###############################################################
#  Generated by:      Cadence Innovus 21.14-e032_1
#  OS:                Linux x86_64(Host ID scc767089)
#  Generated on:      Thu Mar 16 00:29:08 2023
#  Design:            scr1_pipe_top
#  Command:           write_lef_abstract scr1_pipe_top.lef -top_layer 9 -stripe_pins
###############################################################

VERSION 5.8 ;

BUSBITCHARS "[]" ;
DIVIDERCHAR "/" ;

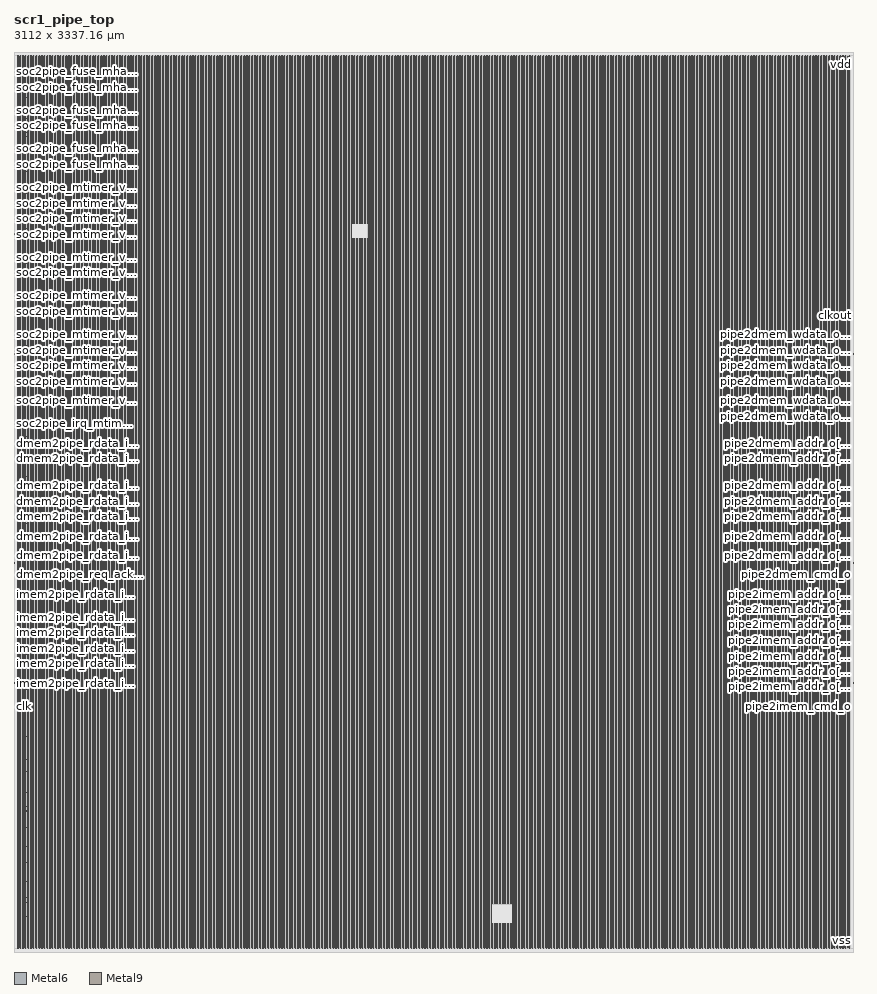
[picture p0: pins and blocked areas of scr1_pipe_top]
MACRO scr1_pipe_top
  CLASS BLOCK ;
  SIZE 3112.000000 BY 3337.160000 ;
  FOREIGN scr1_pipe_top 0.000000 0.000000 ;
  ORIGIN 0 0 ;
  SYMMETRY X Y R90 ;
  PIN pipe_rst_n
    DIRECTION INPUT ;
    USE SIGNAL ;
    PORT
      LAYER Metal6 ;
        RECT 0.000000 896.965000 0.290000 897.035000 ;
    END
  END pipe_rst_n
  PIN clk
    DIRECTION INPUT ;
    USE SIGNAL ;
    PORT
      LAYER Metal6 ;
        RECT 0.000000 911.315000 0.290000 911.385000 ;
    END
  END clk
  PIN pipe2imem_req_o
    DIRECTION OUTPUT ;
    USE SIGNAL ;
    PORT
      LAYER Metal6 ;
        RECT 3111.710000 896.965000 3112.000000 897.035000 ;
    END
  END pipe2imem_req_o
  PIN pipe2imem_cmd_o
    DIRECTION OUTPUT ;
    USE SIGNAL ;
    PORT
      LAYER Metal6 ;
        RECT 3111.710000 911.315000 3112.000000 911.385000 ;
    END
  END pipe2imem_cmd_o
  PIN pipe2imem_addr_o[31]
    DIRECTION OUTPUT ;
    USE SIGNAL ;
    PORT
      LAYER Metal6 ;
        RECT 3111.710000 925.670000 3112.000000 925.740000 ;
    END
  END pipe2imem_addr_o[31]
  PIN pipe2imem_addr_o[30]
    DIRECTION OUTPUT ;
    USE SIGNAL ;
    PORT
      LAYER Metal6 ;
        RECT 3111.710000 940.020000 3112.000000 940.090000 ;
    END
  END pipe2imem_addr_o[30]
  PIN pipe2imem_addr_o[29]
    DIRECTION OUTPUT ;
    USE SIGNAL ;
    PORT
      LAYER Metal6 ;
        RECT 3111.710000 954.375000 3112.000000 954.445000 ;
    END
  END pipe2imem_addr_o[29]
  PIN pipe2imem_addr_o[28]
    DIRECTION OUTPUT ;
    USE SIGNAL ;
    PORT
      LAYER Metal6 ;
        RECT 3111.710000 968.725000 3112.000000 968.795000 ;
    END
  END pipe2imem_addr_o[28]
  PIN pipe2imem_addr_o[27]
    DIRECTION OUTPUT ;
    USE SIGNAL ;
    PORT
      LAYER Metal6 ;
        RECT 3111.710000 983.075000 3112.000000 983.145000 ;
    END
  END pipe2imem_addr_o[27]
  PIN pipe2imem_addr_o[26]
    DIRECTION OUTPUT ;
    USE SIGNAL ;
    PORT
      LAYER Metal6 ;
        RECT 3111.710000 997.430000 3112.000000 997.500000 ;
    END
  END pipe2imem_addr_o[26]
  PIN pipe2imem_addr_o[25]
    DIRECTION OUTPUT ;
    USE SIGNAL ;
    PORT
      LAYER Metal6 ;
        RECT 3111.710000 1011.780000 3112.000000 1011.850000 ;
    END
  END pipe2imem_addr_o[25]
  PIN pipe2imem_addr_o[24]
    DIRECTION OUTPUT ;
    USE SIGNAL ;
    PORT
      LAYER Metal6 ;
        RECT 3111.710000 1026.135000 3112.000000 1026.205000 ;
    END
  END pipe2imem_addr_o[24]
  PIN pipe2imem_addr_o[23]
    DIRECTION OUTPUT ;
    USE SIGNAL ;
    PORT
      LAYER Metal6 ;
        RECT 3111.710000 1040.485000 3112.000000 1040.555000 ;
    END
  END pipe2imem_addr_o[23]
  PIN pipe2imem_addr_o[22]
    DIRECTION OUTPUT ;
    USE SIGNAL ;
    PORT
      LAYER Metal6 ;
        RECT 3111.710000 1054.835000 3112.000000 1054.905000 ;
    END
  END pipe2imem_addr_o[22]
  PIN pipe2imem_addr_o[21]
    DIRECTION OUTPUT ;
    USE SIGNAL ;
    PORT
      LAYER Metal6 ;
        RECT 3111.710000 1069.190000 3112.000000 1069.260000 ;
    END
  END pipe2imem_addr_o[21]
  PIN pipe2imem_addr_o[20]
    DIRECTION OUTPUT ;
    USE SIGNAL ;
    PORT
      LAYER Metal6 ;
        RECT 3111.710000 1083.540000 3112.000000 1083.610000 ;
    END
  END pipe2imem_addr_o[20]
  PIN pipe2imem_addr_o[19]
    DIRECTION OUTPUT ;
    USE SIGNAL ;
    PORT
      LAYER Metal6 ;
        RECT 3111.710000 1097.895000 3112.000000 1097.965000 ;
    END
  END pipe2imem_addr_o[19]
  PIN pipe2imem_addr_o[18]
    DIRECTION OUTPUT ;
    USE SIGNAL ;
    PORT
      LAYER Metal6 ;
        RECT 3111.710000 1112.245000 3112.000000 1112.315000 ;
    END
  END pipe2imem_addr_o[18]
  PIN pipe2imem_addr_o[17]
    DIRECTION OUTPUT ;
    USE SIGNAL ;
    PORT
      LAYER Metal6 ;
        RECT 3111.710000 1126.595000 3112.000000 1126.665000 ;
    END
  END pipe2imem_addr_o[17]
  PIN pipe2imem_addr_o[16]
    DIRECTION OUTPUT ;
    USE SIGNAL ;
    PORT
      LAYER Metal6 ;
        RECT 3111.710000 1140.950000 3112.000000 1141.020000 ;
    END
  END pipe2imem_addr_o[16]
  PIN pipe2imem_addr_o[15]
    DIRECTION OUTPUT ;
    USE SIGNAL ;
    PORT
      LAYER Metal6 ;
        RECT 3111.710000 1155.300000 3112.000000 1155.370000 ;
    END
  END pipe2imem_addr_o[15]
  PIN pipe2imem_addr_o[14]
    DIRECTION OUTPUT ;
    USE SIGNAL ;
    PORT
      LAYER Metal6 ;
        RECT 3111.710000 1169.655000 3112.000000 1169.725000 ;
    END
  END pipe2imem_addr_o[14]
  PIN pipe2imem_addr_o[13]
    DIRECTION OUTPUT ;
    USE SIGNAL ;
    PORT
      LAYER Metal6 ;
        RECT 3111.710000 1184.005000 3112.000000 1184.075000 ;
    END
  END pipe2imem_addr_o[13]
  PIN pipe2imem_addr_o[12]
    DIRECTION OUTPUT ;
    USE SIGNAL ;
    PORT
      LAYER Metal6 ;
        RECT 3111.710000 1198.355000 3112.000000 1198.425000 ;
    END
  END pipe2imem_addr_o[12]
  PIN pipe2imem_addr_o[11]
    DIRECTION OUTPUT ;
    USE SIGNAL ;
    PORT
      LAYER Metal6 ;
        RECT 3111.710000 1212.710000 3112.000000 1212.780000 ;
    END
  END pipe2imem_addr_o[11]
  PIN pipe2imem_addr_o[10]
    DIRECTION OUTPUT ;
    USE SIGNAL ;
    PORT
      LAYER Metal6 ;
        RECT 3111.710000 1227.060000 3112.000000 1227.130000 ;
    END
  END pipe2imem_addr_o[10]
  PIN pipe2imem_addr_o[9]
    DIRECTION OUTPUT ;
    USE SIGNAL ;
    PORT
      LAYER Metal6 ;
        RECT 3111.710000 1241.415000 3112.000000 1241.485000 ;
    END
  END pipe2imem_addr_o[9]
  PIN pipe2imem_addr_o[8]
    DIRECTION OUTPUT ;
    USE SIGNAL ;
    PORT
      LAYER Metal6 ;
        RECT 3111.710000 1255.765000 3112.000000 1255.835000 ;
    END
  END pipe2imem_addr_o[8]
  PIN pipe2imem_addr_o[7]
    DIRECTION OUTPUT ;
    USE SIGNAL ;
    PORT
      LAYER Metal6 ;
        RECT 3111.710000 1270.115000 3112.000000 1270.185000 ;
    END
  END pipe2imem_addr_o[7]
  PIN pipe2imem_addr_o[6]
    DIRECTION OUTPUT ;
    USE SIGNAL ;
    PORT
      LAYER Metal6 ;
        RECT 3111.710000 1284.470000 3112.000000 1284.540000 ;
    END
  END pipe2imem_addr_o[6]
  PIN pipe2imem_addr_o[5]
    DIRECTION OUTPUT ;
    USE SIGNAL ;
    PORT
      LAYER Metal6 ;
        RECT 3111.710000 1298.820000 3112.000000 1298.890000 ;
    END
  END pipe2imem_addr_o[5]
  PIN pipe2imem_addr_o[4]
    DIRECTION OUTPUT ;
    USE SIGNAL ;
    PORT
      LAYER Metal6 ;
        RECT 3111.710000 1313.175000 3112.000000 1313.245000 ;
    END
  END pipe2imem_addr_o[4]
  PIN pipe2imem_addr_o[3]
    DIRECTION OUTPUT ;
    USE SIGNAL ;
    PORT
      LAYER Metal6 ;
        RECT 3111.710000 1327.525000 3112.000000 1327.595000 ;
    END
  END pipe2imem_addr_o[3]
  PIN pipe2imem_addr_o[2]
    DIRECTION OUTPUT ;
    USE SIGNAL ;
    PORT
      LAYER Metal6 ;
        RECT 3111.710000 1341.875000 3112.000000 1341.945000 ;
    END
  END pipe2imem_addr_o[2]
  PIN pipe2imem_addr_o[1]
    DIRECTION OUTPUT ;
    USE SIGNAL ;
    PORT
      LAYER Metal6 ;
        RECT 3111.710000 1356.230000 3112.000000 1356.300000 ;
    END
  END pipe2imem_addr_o[1]
  PIN pipe2imem_addr_o[0]
    DIRECTION OUTPUT ;
    USE SIGNAL ;
    PORT
      LAYER Metal6 ;
        RECT 3111.710000 1370.580000 3112.000000 1370.650000 ;
    END
  END pipe2imem_addr_o[0]
  PIN imem2pipe_req_ack_i
    DIRECTION INPUT ;
    USE SIGNAL ;
    PORT
      LAYER Metal6 ;
        RECT 0.000000 925.670000 0.290000 925.740000 ;
    END
  END imem2pipe_req_ack_i
  PIN imem2pipe_rdata_i[31]
    DIRECTION INPUT ;
    USE SIGNAL ;
    PORT
      LAYER Metal6 ;
        RECT 0.000000 940.020000 0.290000 940.090000 ;
    END
  END imem2pipe_rdata_i[31]
  PIN imem2pipe_rdata_i[30]
    DIRECTION INPUT ;
    USE SIGNAL ;
    PORT
      LAYER Metal6 ;
        RECT 0.000000 954.375000 0.290000 954.445000 ;
    END
  END imem2pipe_rdata_i[30]
  PIN imem2pipe_rdata_i[29]
    DIRECTION INPUT ;
    USE SIGNAL ;
    PORT
      LAYER Metal6 ;
        RECT 0.000000 968.725000 0.290000 968.795000 ;
    END
  END imem2pipe_rdata_i[29]
  PIN imem2pipe_rdata_i[28]
    DIRECTION INPUT ;
    USE SIGNAL ;
    PORT
      LAYER Metal6 ;
        RECT 0.000000 983.075000 0.290000 983.145000 ;
    END
  END imem2pipe_rdata_i[28]
  PIN imem2pipe_rdata_i[27]
    DIRECTION INPUT ;
    USE SIGNAL ;
    PORT
      LAYER Metal6 ;
        RECT 0.000000 997.430000 0.290000 997.500000 ;
    END
  END imem2pipe_rdata_i[27]
  PIN imem2pipe_rdata_i[26]
    DIRECTION INPUT ;
    USE SIGNAL ;
    PORT
      LAYER Metal6 ;
        RECT 0.000000 1011.780000 0.290000 1011.850000 ;
    END
  END imem2pipe_rdata_i[26]
  PIN imem2pipe_rdata_i[25]
    DIRECTION INPUT ;
    USE SIGNAL ;
    PORT
      LAYER Metal6 ;
        RECT 0.000000 1026.135000 0.290000 1026.205000 ;
    END
  END imem2pipe_rdata_i[25]
  PIN imem2pipe_rdata_i[24]
    DIRECTION INPUT ;
    USE SIGNAL ;
    PORT
      LAYER Metal6 ;
        RECT 0.000000 1040.485000 0.290000 1040.555000 ;
    END
  END imem2pipe_rdata_i[24]
  PIN imem2pipe_rdata_i[23]
    DIRECTION INPUT ;
    USE SIGNAL ;
    PORT
      LAYER Metal6 ;
        RECT 0.000000 1054.835000 0.290000 1054.905000 ;
    END
  END imem2pipe_rdata_i[23]
  PIN imem2pipe_rdata_i[22]
    DIRECTION INPUT ;
    USE SIGNAL ;
    PORT
      LAYER Metal6 ;
        RECT 0.000000 1069.190000 0.290000 1069.260000 ;
    END
  END imem2pipe_rdata_i[22]
  PIN imem2pipe_rdata_i[21]
    DIRECTION INPUT ;
    USE SIGNAL ;
    PORT
      LAYER Metal6 ;
        RECT 0.000000 1083.540000 0.290000 1083.610000 ;
    END
  END imem2pipe_rdata_i[21]
  PIN imem2pipe_rdata_i[20]
    DIRECTION INPUT ;
    USE SIGNAL ;
    PORT
      LAYER Metal6 ;
        RECT 0.000000 1097.895000 0.290000 1097.965000 ;
    END
  END imem2pipe_rdata_i[20]
  PIN imem2pipe_rdata_i[19]
    DIRECTION INPUT ;
    USE SIGNAL ;
    PORT
      LAYER Metal6 ;
        RECT 0.000000 1112.245000 0.290000 1112.315000 ;
    END
  END imem2pipe_rdata_i[19]
  PIN imem2pipe_rdata_i[18]
    DIRECTION INPUT ;
    USE SIGNAL ;
    PORT
      LAYER Metal6 ;
        RECT 0.000000 1126.595000 0.290000 1126.665000 ;
    END
  END imem2pipe_rdata_i[18]
  PIN imem2pipe_rdata_i[17]
    DIRECTION INPUT ;
    USE SIGNAL ;
    PORT
      LAYER Metal6 ;
        RECT 0.000000 1140.950000 0.290000 1141.020000 ;
    END
  END imem2pipe_rdata_i[17]
  PIN imem2pipe_rdata_i[16]
    DIRECTION INPUT ;
    USE SIGNAL ;
    PORT
      LAYER Metal6 ;
        RECT 0.000000 1155.300000 0.290000 1155.370000 ;
    END
  END imem2pipe_rdata_i[16]
  PIN imem2pipe_rdata_i[15]
    DIRECTION INPUT ;
    USE SIGNAL ;
    PORT
      LAYER Metal6 ;
        RECT 0.000000 1169.655000 0.290000 1169.725000 ;
    END
  END imem2pipe_rdata_i[15]
  PIN imem2pipe_rdata_i[14]
    DIRECTION INPUT ;
    USE SIGNAL ;
    PORT
      LAYER Metal6 ;
        RECT 0.000000 1184.005000 0.290000 1184.075000 ;
    END
  END imem2pipe_rdata_i[14]
  PIN imem2pipe_rdata_i[13]
    DIRECTION INPUT ;
    USE SIGNAL ;
    PORT
      LAYER Metal6 ;
        RECT 0.000000 1198.355000 0.290000 1198.425000 ;
    END
  END imem2pipe_rdata_i[13]
  PIN imem2pipe_rdata_i[12]
    DIRECTION INPUT ;
    USE SIGNAL ;
    PORT
      LAYER Metal6 ;
        RECT 0.000000 1212.710000 0.290000 1212.780000 ;
    END
  END imem2pipe_rdata_i[12]
  PIN imem2pipe_rdata_i[11]
    DIRECTION INPUT ;
    USE SIGNAL ;
    PORT
      LAYER Metal6 ;
        RECT 0.000000 1227.060000 0.290000 1227.130000 ;
    END
  END imem2pipe_rdata_i[11]
  PIN imem2pipe_rdata_i[10]
    DIRECTION INPUT ;
    USE SIGNAL ;
    PORT
      LAYER Metal6 ;
        RECT 0.000000 1241.415000 0.290000 1241.485000 ;
    END
  END imem2pipe_rdata_i[10]
  PIN imem2pipe_rdata_i[9]
    DIRECTION INPUT ;
    USE SIGNAL ;
    PORT
      LAYER Metal6 ;
        RECT 0.000000 1255.765000 0.290000 1255.835000 ;
    END
  END imem2pipe_rdata_i[9]
  PIN imem2pipe_rdata_i[8]
    DIRECTION INPUT ;
    USE SIGNAL ;
    PORT
      LAYER Metal6 ;
        RECT 0.000000 1270.115000 0.290000 1270.185000 ;
    END
  END imem2pipe_rdata_i[8]
  PIN imem2pipe_rdata_i[7]
    DIRECTION INPUT ;
    USE SIGNAL ;
    PORT
      LAYER Metal6 ;
        RECT 0.000000 1284.470000 0.290000 1284.540000 ;
    END
  END imem2pipe_rdata_i[7]
  PIN imem2pipe_rdata_i[6]
    DIRECTION INPUT ;
    USE SIGNAL ;
    PORT
      LAYER Metal6 ;
        RECT 0.000000 1298.820000 0.290000 1298.890000 ;
    END
  END imem2pipe_rdata_i[6]
  PIN imem2pipe_rdata_i[5]
    DIRECTION INPUT ;
    USE SIGNAL ;
    PORT
      LAYER Metal6 ;
        RECT 0.000000 1313.175000 0.290000 1313.245000 ;
    END
  END imem2pipe_rdata_i[5]
  PIN imem2pipe_rdata_i[4]
    DIRECTION INPUT ;
    USE SIGNAL ;
    PORT
      LAYER Metal6 ;
        RECT 0.000000 1327.525000 0.290000 1327.595000 ;
    END
  END imem2pipe_rdata_i[4]
  PIN imem2pipe_rdata_i[3]
    DIRECTION INPUT ;
    USE SIGNAL ;
    PORT
      LAYER Metal6 ;
        RECT 0.000000 1341.875000 0.290000 1341.945000 ;
    END
  END imem2pipe_rdata_i[3]
  PIN imem2pipe_rdata_i[2]
    DIRECTION INPUT ;
    USE SIGNAL ;
    PORT
      LAYER Metal6 ;
        RECT 0.000000 1356.230000 0.290000 1356.300000 ;
    END
  END imem2pipe_rdata_i[2]
  PIN imem2pipe_rdata_i[1]
    DIRECTION INPUT ;
    USE SIGNAL ;
    PORT
      LAYER Metal6 ;
        RECT 0.000000 1370.580000 0.290000 1370.650000 ;
    END
  END imem2pipe_rdata_i[1]
  PIN imem2pipe_rdata_i[0]
    DIRECTION INPUT ;
    USE SIGNAL ;
    PORT
      LAYER Metal6 ;
        RECT 0.000000 1384.935000 0.290000 1385.005000 ;
    END
  END imem2pipe_rdata_i[0]
  PIN imem2pipe_resp_i[1]
    DIRECTION INPUT ;
    USE SIGNAL ;
    PORT
      LAYER Metal6 ;
        RECT 0.000000 1399.285000 0.290000 1399.355000 ;
    END
  END imem2pipe_resp_i[1]
  PIN imem2pipe_resp_i[0]
    DIRECTION INPUT ;
    USE SIGNAL ;
    PORT
      LAYER Metal6 ;
        RECT 0.000000 1413.635000 0.290000 1413.705000 ;
    END
  END imem2pipe_resp_i[0]
  PIN pipe2dmem_req_o
    DIRECTION OUTPUT ;
    USE SIGNAL ;
    PORT
      LAYER Metal6 ;
        RECT 3111.710000 1384.935000 3112.000000 1385.005000 ;
    END
  END pipe2dmem_req_o
  PIN pipe2dmem_cmd_o
    DIRECTION OUTPUT ;
    USE SIGNAL ;
    PORT
      LAYER Metal6 ;
        RECT 3111.710000 1399.285000 3112.000000 1399.355000 ;
    END
  END pipe2dmem_cmd_o
  PIN pipe2dmem_width_o[1]
    DIRECTION OUTPUT ;
    USE SIGNAL ;
    PORT
      LAYER Metal6 ;
        RECT 3111.710000 1413.635000 3112.000000 1413.705000 ;
    END
  END pipe2dmem_width_o[1]
  PIN pipe2dmem_width_o[0]
    DIRECTION OUTPUT ;
    USE SIGNAL ;
    PORT
      LAYER Metal6 ;
        RECT 3111.710000 1427.990000 3112.000000 1428.060000 ;
    END
  END pipe2dmem_width_o[0]
  PIN pipe2dmem_addr_o[31]
    DIRECTION OUTPUT ;
    USE SIGNAL ;
    PORT
      LAYER Metal6 ;
        RECT 3111.710000 1442.340000 3112.000000 1442.410000 ;
    END
  END pipe2dmem_addr_o[31]
  PIN pipe2dmem_addr_o[30]
    DIRECTION OUTPUT ;
    USE SIGNAL ;
    PORT
      LAYER Metal6 ;
        RECT 3111.710000 1456.695000 3112.000000 1456.765000 ;
    END
  END pipe2dmem_addr_o[30]
  PIN pipe2dmem_addr_o[29]
    DIRECTION OUTPUT ;
    USE SIGNAL ;
    PORT
      LAYER Metal6 ;
        RECT 3111.710000 1471.045000 3112.000000 1471.115000 ;
    END
  END pipe2dmem_addr_o[29]
  PIN pipe2dmem_addr_o[28]
    DIRECTION OUTPUT ;
    USE SIGNAL ;
    PORT
      LAYER Metal6 ;
        RECT 3111.710000 1485.395000 3112.000000 1485.465000 ;
    END
  END pipe2dmem_addr_o[28]
  PIN pipe2dmem_addr_o[27]
    DIRECTION OUTPUT ;
    USE SIGNAL ;
    PORT
      LAYER Metal6 ;
        RECT 3111.710000 1499.750000 3112.000000 1499.820000 ;
    END
  END pipe2dmem_addr_o[27]
  PIN pipe2dmem_addr_o[26]
    DIRECTION OUTPUT ;
    USE SIGNAL ;
    PORT
      LAYER Metal6 ;
        RECT 3111.710000 1514.100000 3112.000000 1514.170000 ;
    END
  END pipe2dmem_addr_o[26]
  PIN pipe2dmem_addr_o[25]
    DIRECTION OUTPUT ;
    USE SIGNAL ;
    PORT
      LAYER Metal6 ;
        RECT 3111.710000 1528.455000 3112.000000 1528.525000 ;
    END
  END pipe2dmem_addr_o[25]
  PIN pipe2dmem_addr_o[24]
    DIRECTION OUTPUT ;
    USE SIGNAL ;
    PORT
      LAYER Metal6 ;
        RECT 3111.710000 1542.805000 3112.000000 1542.875000 ;
    END
  END pipe2dmem_addr_o[24]
  PIN pipe2dmem_addr_o[23]
    DIRECTION OUTPUT ;
    USE SIGNAL ;
    PORT
      LAYER Metal6 ;
        RECT 3111.710000 1557.155000 3112.000000 1557.225000 ;
    END
  END pipe2dmem_addr_o[23]
  PIN pipe2dmem_addr_o[22]
    DIRECTION OUTPUT ;
    USE SIGNAL ;
    PORT
      LAYER Metal6 ;
        RECT 3111.710000 1571.510000 3112.000000 1571.580000 ;
    END
  END pipe2dmem_addr_o[22]
  PIN pipe2dmem_addr_o[21]
    DIRECTION OUTPUT ;
    USE SIGNAL ;
    PORT
      LAYER Metal6 ;
        RECT 3111.710000 1585.860000 3112.000000 1585.930000 ;
    END
  END pipe2dmem_addr_o[21]
  PIN pipe2dmem_addr_o[20]
    DIRECTION OUTPUT ;
    USE SIGNAL ;
    PORT
      LAYER Metal6 ;
        RECT 3111.710000 1600.215000 3112.000000 1600.285000 ;
    END
  END pipe2dmem_addr_o[20]
  PIN pipe2dmem_addr_o[19]
    DIRECTION OUTPUT ;
    USE SIGNAL ;
    PORT
      LAYER Metal6 ;
        RECT 3111.710000 1614.565000 3112.000000 1614.635000 ;
    END
  END pipe2dmem_addr_o[19]
  PIN pipe2dmem_addr_o[18]
    DIRECTION OUTPUT ;
    USE SIGNAL ;
    PORT
      LAYER Metal6 ;
        RECT 3111.710000 1628.915000 3112.000000 1628.985000 ;
    END
  END pipe2dmem_addr_o[18]
  PIN pipe2dmem_addr_o[17]
    DIRECTION OUTPUT ;
    USE SIGNAL ;
    PORT
      LAYER Metal6 ;
        RECT 3111.710000 1643.270000 3112.000000 1643.340000 ;
    END
  END pipe2dmem_addr_o[17]
  PIN pipe2dmem_addr_o[16]
    DIRECTION OUTPUT ;
    USE SIGNAL ;
    PORT
      LAYER Metal6 ;
        RECT 3111.710000 1657.620000 3112.000000 1657.690000 ;
    END
  END pipe2dmem_addr_o[16]
  PIN pipe2dmem_addr_o[15]
    DIRECTION OUTPUT ;
    USE SIGNAL ;
    PORT
      LAYER Metal6 ;
        RECT 3111.710000 1671.975000 3112.000000 1672.045000 ;
    END
  END pipe2dmem_addr_o[15]
  PIN pipe2dmem_addr_o[14]
    DIRECTION OUTPUT ;
    USE SIGNAL ;
    PORT
      LAYER Metal6 ;
        RECT 3111.710000 1686.325000 3112.000000 1686.395000 ;
    END
  END pipe2dmem_addr_o[14]
  PIN pipe2dmem_addr_o[13]
    DIRECTION OUTPUT ;
    USE SIGNAL ;
    PORT
      LAYER Metal6 ;
        RECT 3111.710000 1700.675000 3112.000000 1700.745000 ;
    END
  END pipe2dmem_addr_o[13]
  PIN pipe2dmem_addr_o[12]
    DIRECTION OUTPUT ;
    USE SIGNAL ;
    PORT
      LAYER Metal6 ;
        RECT 3111.710000 1715.030000 3112.000000 1715.100000 ;
    END
  END pipe2dmem_addr_o[12]
  PIN pipe2dmem_addr_o[11]
    DIRECTION OUTPUT ;
    USE SIGNAL ;
    PORT
      LAYER Metal6 ;
        RECT 3111.710000 1729.380000 3112.000000 1729.450000 ;
    END
  END pipe2dmem_addr_o[11]
  PIN pipe2dmem_addr_o[10]
    DIRECTION OUTPUT ;
    USE SIGNAL ;
    PORT
      LAYER Metal6 ;
        RECT 3111.710000 1743.735000 3112.000000 1743.805000 ;
    END
  END pipe2dmem_addr_o[10]
  PIN pipe2dmem_addr_o[9]
    DIRECTION OUTPUT ;
    USE SIGNAL ;
    PORT
      LAYER Metal6 ;
        RECT 3111.710000 1758.085000 3112.000000 1758.155000 ;
    END
  END pipe2dmem_addr_o[9]
  PIN pipe2dmem_addr_o[8]
    DIRECTION OUTPUT ;
    USE SIGNAL ;
    PORT
      LAYER Metal6 ;
        RECT 3111.710000 1772.435000 3112.000000 1772.505000 ;
    END
  END pipe2dmem_addr_o[8]
  PIN pipe2dmem_addr_o[7]
    DIRECTION OUTPUT ;
    USE SIGNAL ;
    PORT
      LAYER Metal6 ;
        RECT 3111.710000 1786.790000 3112.000000 1786.860000 ;
    END
  END pipe2dmem_addr_o[7]
  PIN pipe2dmem_addr_o[6]
    DIRECTION OUTPUT ;
    USE SIGNAL ;
    PORT
      LAYER Metal6 ;
        RECT 3111.710000 1801.140000 3112.000000 1801.210000 ;
    END
  END pipe2dmem_addr_o[6]
  PIN pipe2dmem_addr_o[5]
    DIRECTION OUTPUT ;
    USE SIGNAL ;
    PORT
      LAYER Metal6 ;
        RECT 3111.710000 1815.495000 3112.000000 1815.565000 ;
    END
  END pipe2dmem_addr_o[5]
  PIN pipe2dmem_addr_o[4]
    DIRECTION OUTPUT ;
    USE SIGNAL ;
    PORT
      LAYER Metal6 ;
        RECT 3111.710000 1829.845000 3112.000000 1829.915000 ;
    END
  END pipe2dmem_addr_o[4]
  PIN pipe2dmem_addr_o[3]
    DIRECTION OUTPUT ;
    USE SIGNAL ;
    PORT
      LAYER Metal6 ;
        RECT 3111.710000 1844.195000 3112.000000 1844.265000 ;
    END
  END pipe2dmem_addr_o[3]
  PIN pipe2dmem_addr_o[2]
    DIRECTION OUTPUT ;
    USE SIGNAL ;
    PORT
      LAYER Metal6 ;
        RECT 3111.710000 1858.550000 3112.000000 1858.620000 ;
    END
  END pipe2dmem_addr_o[2]
  PIN pipe2dmem_addr_o[1]
    DIRECTION OUTPUT ;
    USE SIGNAL ;
    PORT
      LAYER Metal6 ;
        RECT 3111.710000 1872.900000 3112.000000 1872.970000 ;
    END
  END pipe2dmem_addr_o[1]
  PIN pipe2dmem_addr_o[0]
    DIRECTION OUTPUT ;
    USE SIGNAL ;
    PORT
      LAYER Metal6 ;
        RECT 3111.710000 1887.255000 3112.000000 1887.325000 ;
    END
  END pipe2dmem_addr_o[0]
  PIN pipe2dmem_wdata_o[31]
    DIRECTION OUTPUT ;
    USE SIGNAL ;
    PORT
      LAYER Metal6 ;
        RECT 3111.710000 1901.605000 3112.000000 1901.675000 ;
    END
  END pipe2dmem_wdata_o[31]
  PIN pipe2dmem_wdata_o[30]
    DIRECTION OUTPUT ;
    USE SIGNAL ;
    PORT
      LAYER Metal6 ;
        RECT 3111.710000 1915.955000 3112.000000 1916.025000 ;
    END
  END pipe2dmem_wdata_o[30]
  PIN pipe2dmem_wdata_o[29]
    DIRECTION OUTPUT ;
    USE SIGNAL ;
    PORT
      LAYER Metal6 ;
        RECT 3111.710000 1930.310000 3112.000000 1930.380000 ;
    END
  END pipe2dmem_wdata_o[29]
  PIN pipe2dmem_wdata_o[28]
    DIRECTION OUTPUT ;
    USE SIGNAL ;
    PORT
      LAYER Metal6 ;
        RECT 3111.710000 1944.660000 3112.000000 1944.730000 ;
    END
  END pipe2dmem_wdata_o[28]
  PIN pipe2dmem_wdata_o[27]
    DIRECTION OUTPUT ;
    USE SIGNAL ;
    PORT
      LAYER Metal6 ;
        RECT 3111.710000 1959.015000 3112.000000 1959.085000 ;
    END
  END pipe2dmem_wdata_o[27]
  PIN pipe2dmem_wdata_o[26]
    DIRECTION OUTPUT ;
    USE SIGNAL ;
    PORT
      LAYER Metal6 ;
        RECT 3111.710000 1973.365000 3112.000000 1973.435000 ;
    END
  END pipe2dmem_wdata_o[26]
  PIN pipe2dmem_wdata_o[25]
    DIRECTION OUTPUT ;
    USE SIGNAL ;
    PORT
      LAYER Metal6 ;
        RECT 3111.710000 1987.715000 3112.000000 1987.785000 ;
    END
  END pipe2dmem_wdata_o[25]
  PIN pipe2dmem_wdata_o[24]
    DIRECTION OUTPUT ;
    USE SIGNAL ;
    PORT
      LAYER Metal6 ;
        RECT 3111.710000 2002.070000 3112.000000 2002.140000 ;
    END
  END pipe2dmem_wdata_o[24]
  PIN pipe2dmem_wdata_o[23]
    DIRECTION OUTPUT ;
    USE SIGNAL ;
    PORT
      LAYER Metal6 ;
        RECT 3111.710000 2016.420000 3112.000000 2016.490000 ;
    END
  END pipe2dmem_wdata_o[23]
  PIN pipe2dmem_wdata_o[22]
    DIRECTION OUTPUT ;
    USE SIGNAL ;
    PORT
      LAYER Metal6 ;
        RECT 3111.710000 2030.775000 3112.000000 2030.845000 ;
    END
  END pipe2dmem_wdata_o[22]
  PIN pipe2dmem_wdata_o[21]
    DIRECTION OUTPUT ;
    USE SIGNAL ;
    PORT
      LAYER Metal6 ;
        RECT 3111.710000 2045.125000 3112.000000 2045.195000 ;
    END
  END pipe2dmem_wdata_o[21]
  PIN pipe2dmem_wdata_o[20]
    DIRECTION OUTPUT ;
    USE SIGNAL ;
    PORT
      LAYER Metal6 ;
        RECT 3111.710000 2059.475000 3112.000000 2059.545000 ;
    END
  END pipe2dmem_wdata_o[20]
  PIN pipe2dmem_wdata_o[19]
    DIRECTION OUTPUT ;
    USE SIGNAL ;
    PORT
      LAYER Metal6 ;
        RECT 3111.710000 2073.830000 3112.000000 2073.900000 ;
    END
  END pipe2dmem_wdata_o[19]
  PIN pipe2dmem_wdata_o[18]
    DIRECTION OUTPUT ;
    USE SIGNAL ;
    PORT
      LAYER Metal6 ;
        RECT 3111.710000 2088.180000 3112.000000 2088.250000 ;
    END
  END pipe2dmem_wdata_o[18]
  PIN pipe2dmem_wdata_o[17]
    DIRECTION OUTPUT ;
    USE SIGNAL ;
    PORT
      LAYER Metal6 ;
        RECT 3111.710000 2102.535000 3112.000000 2102.605000 ;
    END
  END pipe2dmem_wdata_o[17]
  PIN pipe2dmem_wdata_o[16]
    DIRECTION OUTPUT ;
    USE SIGNAL ;
    PORT
      LAYER Metal6 ;
        RECT 3111.710000 2116.885000 3112.000000 2116.955000 ;
    END
  END pipe2dmem_wdata_o[16]
  PIN pipe2dmem_wdata_o[15]
    DIRECTION OUTPUT ;
    USE SIGNAL ;
    PORT
      LAYER Metal6 ;
        RECT 3111.710000 2131.235000 3112.000000 2131.305000 ;
    END
  END pipe2dmem_wdata_o[15]
  PIN pipe2dmem_wdata_o[14]
    DIRECTION OUTPUT ;
    USE SIGNAL ;
    PORT
      LAYER Metal6 ;
        RECT 3111.710000 2145.590000 3112.000000 2145.660000 ;
    END
  END pipe2dmem_wdata_o[14]
  PIN pipe2dmem_wdata_o[13]
    DIRECTION OUTPUT ;
    USE SIGNAL ;
    PORT
      LAYER Metal6 ;
        RECT 3111.710000 2159.940000 3112.000000 2160.010000 ;
    END
  END pipe2dmem_wdata_o[13]
  PIN pipe2dmem_wdata_o[12]
    DIRECTION OUTPUT ;
    USE SIGNAL ;
    PORT
      LAYER Metal6 ;
        RECT 3111.710000 2174.295000 3112.000000 2174.365000 ;
    END
  END pipe2dmem_wdata_o[12]
  PIN pipe2dmem_wdata_o[11]
    DIRECTION OUTPUT ;
    USE SIGNAL ;
    PORT
      LAYER Metal6 ;
        RECT 3111.710000 2188.645000 3112.000000 2188.715000 ;
    END
  END pipe2dmem_wdata_o[11]
  PIN pipe2dmem_wdata_o[10]
    DIRECTION OUTPUT ;
    USE SIGNAL ;
    PORT
      LAYER Metal6 ;
        RECT 3111.710000 2202.995000 3112.000000 2203.065000 ;
    END
  END pipe2dmem_wdata_o[10]
  PIN pipe2dmem_wdata_o[9]
    DIRECTION OUTPUT ;
    USE SIGNAL ;
    PORT
      LAYER Metal6 ;
        RECT 3111.710000 2217.350000 3112.000000 2217.420000 ;
    END
  END pipe2dmem_wdata_o[9]
  PIN pipe2dmem_wdata_o[8]
    DIRECTION OUTPUT ;
    USE SIGNAL ;
    PORT
      LAYER Metal6 ;
        RECT 3111.710000 2231.700000 3112.000000 2231.770000 ;
    END
  END pipe2dmem_wdata_o[8]
  PIN pipe2dmem_wdata_o[7]
    DIRECTION OUTPUT ;
    USE SIGNAL ;
    PORT
      LAYER Metal6 ;
        RECT 3111.710000 2246.055000 3112.000000 2246.125000 ;
    END
  END pipe2dmem_wdata_o[7]
  PIN pipe2dmem_wdata_o[6]
    DIRECTION OUTPUT ;
    USE SIGNAL ;
    PORT
      LAYER Metal6 ;
        RECT 3111.710000 2260.405000 3112.000000 2260.475000 ;
    END
  END pipe2dmem_wdata_o[6]
  PIN pipe2dmem_wdata_o[5]
    DIRECTION OUTPUT ;
    USE SIGNAL ;
    PORT
      LAYER Metal6 ;
        RECT 3111.710000 2274.755000 3112.000000 2274.825000 ;
    END
  END pipe2dmem_wdata_o[5]
  PIN pipe2dmem_wdata_o[4]
    DIRECTION OUTPUT ;
    USE SIGNAL ;
    PORT
      LAYER Metal6 ;
        RECT 3111.710000 2289.110000 3112.000000 2289.180000 ;
    END
  END pipe2dmem_wdata_o[4]
  PIN pipe2dmem_wdata_o[3]
    DIRECTION OUTPUT ;
    USE SIGNAL ;
    PORT
      LAYER Metal6 ;
        RECT 3111.710000 2303.460000 3112.000000 2303.530000 ;
    END
  END pipe2dmem_wdata_o[3]
  PIN pipe2dmem_wdata_o[2]
    DIRECTION OUTPUT ;
    USE SIGNAL ;
    PORT
      LAYER Metal6 ;
        RECT 3111.710000 2317.815000 3112.000000 2317.885000 ;
    END
  END pipe2dmem_wdata_o[2]
  PIN pipe2dmem_wdata_o[1]
    DIRECTION OUTPUT ;
    USE SIGNAL ;
    PORT
      LAYER Metal6 ;
        RECT 3111.710000 2332.165000 3112.000000 2332.235000 ;
    END
  END pipe2dmem_wdata_o[1]
  PIN pipe2dmem_wdata_o[0]
    DIRECTION OUTPUT ;
    USE SIGNAL ;
    PORT
      LAYER Metal6 ;
        RECT 3111.710000 2346.515000 3112.000000 2346.585000 ;
    END
  END pipe2dmem_wdata_o[0]
  PIN dmem2pipe_req_ack_i
    DIRECTION INPUT ;
    USE SIGNAL ;
    PORT
      LAYER Metal6 ;
        RECT 0.000000 1427.990000 0.290000 1428.060000 ;
    END
  END dmem2pipe_req_ack_i
  PIN dmem2pipe_rdata_i[31]
    DIRECTION INPUT ;
    USE SIGNAL ;
    PORT
      LAYER Metal6 ;
        RECT 0.000000 1442.340000 0.290000 1442.410000 ;
    END
  END dmem2pipe_rdata_i[31]
  PIN dmem2pipe_rdata_i[30]
    DIRECTION INPUT ;
    USE SIGNAL ;
    PORT
      LAYER Metal6 ;
        RECT 0.000000 1456.695000 0.290000 1456.765000 ;
    END
  END dmem2pipe_rdata_i[30]
  PIN dmem2pipe_rdata_i[29]
    DIRECTION INPUT ;
    USE SIGNAL ;
    PORT
      LAYER Metal6 ;
        RECT 0.000000 1471.045000 0.290000 1471.115000 ;
    END
  END dmem2pipe_rdata_i[29]
  PIN dmem2pipe_rdata_i[28]
    DIRECTION INPUT ;
    USE SIGNAL ;
    PORT
      LAYER Metal6 ;
        RECT 0.000000 1485.395000 0.290000 1485.465000 ;
    END
  END dmem2pipe_rdata_i[28]
  PIN dmem2pipe_rdata_i[27]
    DIRECTION INPUT ;
    USE SIGNAL ;
    PORT
      LAYER Metal6 ;
        RECT 0.000000 1499.750000 0.290000 1499.820000 ;
    END
  END dmem2pipe_rdata_i[27]
  PIN dmem2pipe_rdata_i[26]
    DIRECTION INPUT ;
    USE SIGNAL ;
    PORT
      LAYER Metal6 ;
        RECT 0.000000 1514.100000 0.290000 1514.170000 ;
    END
  END dmem2pipe_rdata_i[26]
  PIN dmem2pipe_rdata_i[25]
    DIRECTION INPUT ;
    USE SIGNAL ;
    PORT
      LAYER Metal6 ;
        RECT 0.000000 1528.455000 0.290000 1528.525000 ;
    END
  END dmem2pipe_rdata_i[25]
  PIN dmem2pipe_rdata_i[24]
    DIRECTION INPUT ;
    USE SIGNAL ;
    PORT
      LAYER Metal6 ;
        RECT 0.000000 1542.805000 0.290000 1542.875000 ;
    END
  END dmem2pipe_rdata_i[24]
  PIN dmem2pipe_rdata_i[23]
    DIRECTION INPUT ;
    USE SIGNAL ;
    PORT
      LAYER Metal6 ;
        RECT 0.000000 1557.155000 0.290000 1557.225000 ;
    END
  END dmem2pipe_rdata_i[23]
  PIN dmem2pipe_rdata_i[22]
    DIRECTION INPUT ;
    USE SIGNAL ;
    PORT
      LAYER Metal6 ;
        RECT 0.000000 1571.510000 0.290000 1571.580000 ;
    END
  END dmem2pipe_rdata_i[22]
  PIN dmem2pipe_rdata_i[21]
    DIRECTION INPUT ;
    USE SIGNAL ;
    PORT
      LAYER Metal6 ;
        RECT 0.000000 1585.860000 0.290000 1585.930000 ;
    END
  END dmem2pipe_rdata_i[21]
  PIN dmem2pipe_rdata_i[20]
    DIRECTION INPUT ;
    USE SIGNAL ;
    PORT
      LAYER Metal6 ;
        RECT 0.000000 1600.215000 0.290000 1600.285000 ;
    END
  END dmem2pipe_rdata_i[20]
  PIN dmem2pipe_rdata_i[19]
    DIRECTION INPUT ;
    USE SIGNAL ;
    PORT
      LAYER Metal6 ;
        RECT 0.000000 1614.565000 0.290000 1614.635000 ;
    END
  END dmem2pipe_rdata_i[19]
  PIN dmem2pipe_rdata_i[18]
    DIRECTION INPUT ;
    USE SIGNAL ;
    PORT
      LAYER Metal6 ;
        RECT 0.000000 1628.915000 0.290000 1628.985000 ;
    END
  END dmem2pipe_rdata_i[18]
  PIN dmem2pipe_rdata_i[17]
    DIRECTION INPUT ;
    USE SIGNAL ;
    PORT
      LAYER Metal6 ;
        RECT 0.000000 1643.270000 0.290000 1643.340000 ;
    END
  END dmem2pipe_rdata_i[17]
  PIN dmem2pipe_rdata_i[16]
    DIRECTION INPUT ;
    USE SIGNAL ;
    PORT
      LAYER Metal6 ;
        RECT 0.000000 1657.620000 0.290000 1657.690000 ;
    END
  END dmem2pipe_rdata_i[16]
  PIN dmem2pipe_rdata_i[15]
    DIRECTION INPUT ;
    USE SIGNAL ;
    PORT
      LAYER Metal6 ;
        RECT 0.000000 1671.975000 0.290000 1672.045000 ;
    END
  END dmem2pipe_rdata_i[15]
  PIN dmem2pipe_rdata_i[14]
    DIRECTION INPUT ;
    USE SIGNAL ;
    PORT
      LAYER Metal6 ;
        RECT 0.000000 1686.325000 0.290000 1686.395000 ;
    END
  END dmem2pipe_rdata_i[14]
  PIN dmem2pipe_rdata_i[13]
    DIRECTION INPUT ;
    USE SIGNAL ;
    PORT
      LAYER Metal6 ;
        RECT 0.000000 1700.675000 0.290000 1700.745000 ;
    END
  END dmem2pipe_rdata_i[13]
  PIN dmem2pipe_rdata_i[12]
    DIRECTION INPUT ;
    USE SIGNAL ;
    PORT
      LAYER Metal6 ;
        RECT 0.000000 1715.030000 0.290000 1715.100000 ;
    END
  END dmem2pipe_rdata_i[12]
  PIN dmem2pipe_rdata_i[11]
    DIRECTION INPUT ;
    USE SIGNAL ;
    PORT
      LAYER Metal6 ;
        RECT 0.000000 1729.380000 0.290000 1729.450000 ;
    END
  END dmem2pipe_rdata_i[11]
  PIN dmem2pipe_rdata_i[10]
    DIRECTION INPUT ;
    USE SIGNAL ;
    PORT
      LAYER Metal6 ;
        RECT 0.000000 1743.735000 0.290000 1743.805000 ;
    END
  END dmem2pipe_rdata_i[10]
  PIN dmem2pipe_rdata_i[9]
    DIRECTION INPUT ;
    USE SIGNAL ;
    PORT
      LAYER Metal6 ;
        RECT 0.000000 1758.085000 0.290000 1758.155000 ;
    END
  END dmem2pipe_rdata_i[9]
  PIN dmem2pipe_rdata_i[8]
    DIRECTION INPUT ;
    USE SIGNAL ;
    PORT
      LAYER Metal6 ;
        RECT 0.000000 1772.435000 0.290000 1772.505000 ;
    END
  END dmem2pipe_rdata_i[8]
  PIN dmem2pipe_rdata_i[7]
    DIRECTION INPUT ;
    USE SIGNAL ;
    PORT
      LAYER Metal6 ;
        RECT 0.000000 1786.790000 0.290000 1786.860000 ;
    END
  END dmem2pipe_rdata_i[7]
  PIN dmem2pipe_rdata_i[6]
    DIRECTION INPUT ;
    USE SIGNAL ;
    PORT
      LAYER Metal6 ;
        RECT 0.000000 1801.140000 0.290000 1801.210000 ;
    END
  END dmem2pipe_rdata_i[6]
  PIN dmem2pipe_rdata_i[5]
    DIRECTION INPUT ;
    USE SIGNAL ;
    PORT
      LAYER Metal6 ;
        RECT 0.000000 1815.495000 0.290000 1815.565000 ;
    END
  END dmem2pipe_rdata_i[5]
  PIN dmem2pipe_rdata_i[4]
    DIRECTION INPUT ;
    USE SIGNAL ;
    PORT
      LAYER Metal6 ;
        RECT 0.000000 1829.845000 0.290000 1829.915000 ;
    END
  END dmem2pipe_rdata_i[4]
  PIN dmem2pipe_rdata_i[3]
    DIRECTION INPUT ;
    USE SIGNAL ;
    PORT
      LAYER Metal6 ;
        RECT 0.000000 1844.195000 0.290000 1844.265000 ;
    END
  END dmem2pipe_rdata_i[3]
  PIN dmem2pipe_rdata_i[2]
    DIRECTION INPUT ;
    USE SIGNAL ;
    PORT
      LAYER Metal6 ;
        RECT 0.000000 1858.550000 0.290000 1858.620000 ;
    END
  END dmem2pipe_rdata_i[2]
  PIN dmem2pipe_rdata_i[1]
    DIRECTION INPUT ;
    USE SIGNAL ;
    PORT
      LAYER Metal6 ;
        RECT 0.000000 1872.900000 0.290000 1872.970000 ;
    END
  END dmem2pipe_rdata_i[1]
  PIN dmem2pipe_rdata_i[0]
    DIRECTION INPUT ;
    USE SIGNAL ;
    PORT
      LAYER Metal6 ;
        RECT 0.000000 1887.255000 0.290000 1887.325000 ;
    END
  END dmem2pipe_rdata_i[0]
  PIN dmem2pipe_resp_i[1]
    DIRECTION INPUT ;
    USE SIGNAL ;
    PORT
      LAYER Metal6 ;
        RECT 0.000000 1901.605000 0.290000 1901.675000 ;
    END
  END dmem2pipe_resp_i[1]
  PIN dmem2pipe_resp_i[0]
    DIRECTION INPUT ;
    USE SIGNAL ;
    PORT
      LAYER Metal6 ;
        RECT 0.000000 1915.955000 0.290000 1916.025000 ;
    END
  END dmem2pipe_resp_i[0]
  PIN soc2pipe_irq_ext_i
    DIRECTION INPUT ;
    USE SIGNAL ;
    PORT
      LAYER Metal6 ;
        RECT 0.000000 1930.310000 0.290000 1930.380000 ;
    END
  END soc2pipe_irq_ext_i
  PIN soc2pipe_irq_soft_i
    DIRECTION INPUT ;
    USE SIGNAL ;
    PORT
      LAYER Metal6 ;
        RECT 0.000000 1944.660000 0.290000 1944.730000 ;
    END
  END soc2pipe_irq_soft_i
  PIN soc2pipe_irq_mtimer_i
    DIRECTION INPUT ;
    USE SIGNAL ;
    PORT
      LAYER Metal6 ;
        RECT 0.000000 1959.015000 0.290000 1959.085000 ;
    END
  END soc2pipe_irq_mtimer_i
  PIN soc2pipe_mtimer_val_i[63]
    DIRECTION INPUT ;
    USE SIGNAL ;
    PORT
      LAYER Metal6 ;
        RECT 0.000000 1973.365000 0.290000 1973.435000 ;
    END
  END soc2pipe_mtimer_val_i[63]
  PIN soc2pipe_mtimer_val_i[62]
    DIRECTION INPUT ;
    USE SIGNAL ;
    PORT
      LAYER Metal6 ;
        RECT 0.000000 1987.715000 0.290000 1987.785000 ;
    END
  END soc2pipe_mtimer_val_i[62]
  PIN soc2pipe_mtimer_val_i[61]
    DIRECTION INPUT ;
    USE SIGNAL ;
    PORT
      LAYER Metal6 ;
        RECT 0.000000 2002.070000 0.290000 2002.140000 ;
    END
  END soc2pipe_mtimer_val_i[61]
  PIN soc2pipe_mtimer_val_i[60]
    DIRECTION INPUT ;
    USE SIGNAL ;
    PORT
      LAYER Metal6 ;
        RECT 0.000000 2016.420000 0.290000 2016.490000 ;
    END
  END soc2pipe_mtimer_val_i[60]
  PIN soc2pipe_mtimer_val_i[59]
    DIRECTION INPUT ;
    USE SIGNAL ;
    PORT
      LAYER Metal6 ;
        RECT 0.000000 2030.775000 0.290000 2030.845000 ;
    END
  END soc2pipe_mtimer_val_i[59]
  PIN soc2pipe_mtimer_val_i[58]
    DIRECTION INPUT ;
    USE SIGNAL ;
    PORT
      LAYER Metal6 ;
        RECT 0.000000 2045.125000 0.290000 2045.195000 ;
    END
  END soc2pipe_mtimer_val_i[58]
  PIN soc2pipe_mtimer_val_i[57]
    DIRECTION INPUT ;
    USE SIGNAL ;
    PORT
      LAYER Metal6 ;
        RECT 0.000000 2059.475000 0.290000 2059.545000 ;
    END
  END soc2pipe_mtimer_val_i[57]
  PIN soc2pipe_mtimer_val_i[56]
    DIRECTION INPUT ;
    USE SIGNAL ;
    PORT
      LAYER Metal6 ;
        RECT 0.000000 2073.830000 0.290000 2073.900000 ;
    END
  END soc2pipe_mtimer_val_i[56]
  PIN soc2pipe_mtimer_val_i[55]
    DIRECTION INPUT ;
    USE SIGNAL ;
    PORT
      LAYER Metal6 ;
        RECT 0.000000 2088.180000 0.290000 2088.250000 ;
    END
  END soc2pipe_mtimer_val_i[55]
  PIN soc2pipe_mtimer_val_i[54]
    DIRECTION INPUT ;
    USE SIGNAL ;
    PORT
      LAYER Metal6 ;
        RECT 0.000000 2102.535000 0.290000 2102.605000 ;
    END
  END soc2pipe_mtimer_val_i[54]
  PIN soc2pipe_mtimer_val_i[53]
    DIRECTION INPUT ;
    USE SIGNAL ;
    PORT
      LAYER Metal6 ;
        RECT 0.000000 2116.885000 0.290000 2116.955000 ;
    END
  END soc2pipe_mtimer_val_i[53]
  PIN soc2pipe_mtimer_val_i[52]
    DIRECTION INPUT ;
    USE SIGNAL ;
    PORT
      LAYER Metal6 ;
        RECT 0.000000 2131.235000 0.290000 2131.305000 ;
    END
  END soc2pipe_mtimer_val_i[52]
  PIN soc2pipe_mtimer_val_i[51]
    DIRECTION INPUT ;
    USE SIGNAL ;
    PORT
      LAYER Metal6 ;
        RECT 0.000000 2145.590000 0.290000 2145.660000 ;
    END
  END soc2pipe_mtimer_val_i[51]
  PIN soc2pipe_mtimer_val_i[50]
    DIRECTION INPUT ;
    USE SIGNAL ;
    PORT
      LAYER Metal6 ;
        RECT 0.000000 2159.940000 0.290000 2160.010000 ;
    END
  END soc2pipe_mtimer_val_i[50]
  PIN soc2pipe_mtimer_val_i[49]
    DIRECTION INPUT ;
    USE SIGNAL ;
    PORT
      LAYER Metal6 ;
        RECT 0.000000 2174.295000 0.290000 2174.365000 ;
    END
  END soc2pipe_mtimer_val_i[49]
  PIN soc2pipe_mtimer_val_i[48]
    DIRECTION INPUT ;
    USE SIGNAL ;
    PORT
      LAYER Metal6 ;
        RECT 0.000000 2188.645000 0.290000 2188.715000 ;
    END
  END soc2pipe_mtimer_val_i[48]
  PIN soc2pipe_mtimer_val_i[47]
    DIRECTION INPUT ;
    USE SIGNAL ;
    PORT
      LAYER Metal6 ;
        RECT 0.000000 2202.995000 0.290000 2203.065000 ;
    END
  END soc2pipe_mtimer_val_i[47]
  PIN soc2pipe_mtimer_val_i[46]
    DIRECTION INPUT ;
    USE SIGNAL ;
    PORT
      LAYER Metal6 ;
        RECT 0.000000 2217.350000 0.290000 2217.420000 ;
    END
  END soc2pipe_mtimer_val_i[46]
  PIN soc2pipe_mtimer_val_i[45]
    DIRECTION INPUT ;
    USE SIGNAL ;
    PORT
      LAYER Metal6 ;
        RECT 0.000000 2231.700000 0.290000 2231.770000 ;
    END
  END soc2pipe_mtimer_val_i[45]
  PIN soc2pipe_mtimer_val_i[44]
    DIRECTION INPUT ;
    USE SIGNAL ;
    PORT
      LAYER Metal6 ;
        RECT 0.000000 2246.055000 0.290000 2246.125000 ;
    END
  END soc2pipe_mtimer_val_i[44]
  PIN soc2pipe_mtimer_val_i[43]
    DIRECTION INPUT ;
    USE SIGNAL ;
    PORT
      LAYER Metal6 ;
        RECT 0.000000 2260.405000 0.290000 2260.475000 ;
    END
  END soc2pipe_mtimer_val_i[43]
  PIN soc2pipe_mtimer_val_i[42]
    DIRECTION INPUT ;
    USE SIGNAL ;
    PORT
      LAYER Metal6 ;
        RECT 0.000000 2274.755000 0.290000 2274.825000 ;
    END
  END soc2pipe_mtimer_val_i[42]
  PIN soc2pipe_mtimer_val_i[41]
    DIRECTION INPUT ;
    USE SIGNAL ;
    PORT
      LAYER Metal6 ;
        RECT 0.000000 2289.110000 0.290000 2289.180000 ;
    END
  END soc2pipe_mtimer_val_i[41]
  PIN soc2pipe_mtimer_val_i[40]
    DIRECTION INPUT ;
    USE SIGNAL ;
    PORT
      LAYER Metal6 ;
        RECT 0.000000 2303.460000 0.290000 2303.530000 ;
    END
  END soc2pipe_mtimer_val_i[40]
  PIN soc2pipe_mtimer_val_i[39]
    DIRECTION INPUT ;
    USE SIGNAL ;
    PORT
      LAYER Metal6 ;
        RECT 0.000000 2317.815000 0.290000 2317.885000 ;
    END
  END soc2pipe_mtimer_val_i[39]
  PIN soc2pipe_mtimer_val_i[38]
    DIRECTION INPUT ;
    USE SIGNAL ;
    PORT
      LAYER Metal6 ;
        RECT 0.000000 2332.165000 0.290000 2332.235000 ;
    END
  END soc2pipe_mtimer_val_i[38]
  PIN soc2pipe_mtimer_val_i[37]
    DIRECTION INPUT ;
    USE SIGNAL ;
    PORT
      LAYER Metal6 ;
        RECT 0.000000 2346.515000 0.290000 2346.585000 ;
    END
  END soc2pipe_mtimer_val_i[37]
  PIN soc2pipe_mtimer_val_i[36]
    DIRECTION INPUT ;
    USE SIGNAL ;
    PORT
      LAYER Metal6 ;
        RECT 0.000000 2360.870000 0.290000 2360.940000 ;
    END
  END soc2pipe_mtimer_val_i[36]
  PIN soc2pipe_mtimer_val_i[35]
    DIRECTION INPUT ;
    USE SIGNAL ;
    PORT
      LAYER Metal6 ;
        RECT 0.000000 2375.220000 0.290000 2375.290000 ;
    END
  END soc2pipe_mtimer_val_i[35]
  PIN soc2pipe_mtimer_val_i[34]
    DIRECTION INPUT ;
    USE SIGNAL ;
    PORT
      LAYER Metal6 ;
        RECT 0.000000 2389.575000 0.290000 2389.645000 ;
    END
  END soc2pipe_mtimer_val_i[34]
  PIN soc2pipe_mtimer_val_i[33]
    DIRECTION INPUT ;
    USE SIGNAL ;
    PORT
      LAYER Metal6 ;
        RECT 0.000000 2403.925000 0.290000 2403.995000 ;
    END
  END soc2pipe_mtimer_val_i[33]
  PIN soc2pipe_mtimer_val_i[32]
    DIRECTION INPUT ;
    USE SIGNAL ;
    PORT
      LAYER Metal6 ;
        RECT 0.000000 2418.275000 0.290000 2418.345000 ;
    END
  END soc2pipe_mtimer_val_i[32]
  PIN soc2pipe_mtimer_val_i[31]
    DIRECTION INPUT ;
    USE SIGNAL ;
    PORT
      LAYER Metal6 ;
        RECT 0.000000 2432.630000 0.290000 2432.700000 ;
    END
  END soc2pipe_mtimer_val_i[31]
  PIN soc2pipe_mtimer_val_i[30]
    DIRECTION INPUT ;
    USE SIGNAL ;
    PORT
      LAYER Metal6 ;
        RECT 0.000000 2446.980000 0.290000 2447.050000 ;
    END
  END soc2pipe_mtimer_val_i[30]
  PIN soc2pipe_mtimer_val_i[29]
    DIRECTION INPUT ;
    USE SIGNAL ;
    PORT
      LAYER Metal6 ;
        RECT 0.000000 2461.335000 0.290000 2461.405000 ;
    END
  END soc2pipe_mtimer_val_i[29]
  PIN soc2pipe_mtimer_val_i[28]
    DIRECTION INPUT ;
    USE SIGNAL ;
    PORT
      LAYER Metal6 ;
        RECT 0.000000 2475.685000 0.290000 2475.755000 ;
    END
  END soc2pipe_mtimer_val_i[28]
  PIN soc2pipe_mtimer_val_i[27]
    DIRECTION INPUT ;
    USE SIGNAL ;
    PORT
      LAYER Metal6 ;
        RECT 0.000000 2490.035000 0.290000 2490.105000 ;
    END
  END soc2pipe_mtimer_val_i[27]
  PIN soc2pipe_mtimer_val_i[26]
    DIRECTION INPUT ;
    USE SIGNAL ;
    PORT
      LAYER Metal6 ;
        RECT 0.000000 2504.390000 0.290000 2504.460000 ;
    END
  END soc2pipe_mtimer_val_i[26]
  PIN soc2pipe_mtimer_val_i[25]
    DIRECTION INPUT ;
    USE SIGNAL ;
    PORT
      LAYER Metal6 ;
        RECT 0.000000 2518.740000 0.290000 2518.810000 ;
    END
  END soc2pipe_mtimer_val_i[25]
  PIN soc2pipe_mtimer_val_i[24]
    DIRECTION INPUT ;
    USE SIGNAL ;
    PORT
      LAYER Metal6 ;
        RECT 0.000000 2533.095000 0.290000 2533.165000 ;
    END
  END soc2pipe_mtimer_val_i[24]
  PIN soc2pipe_mtimer_val_i[23]
    DIRECTION INPUT ;
    USE SIGNAL ;
    PORT
      LAYER Metal6 ;
        RECT 0.000000 2547.445000 0.290000 2547.515000 ;
    END
  END soc2pipe_mtimer_val_i[23]
  PIN soc2pipe_mtimer_val_i[22]
    DIRECTION INPUT ;
    USE SIGNAL ;
    PORT
      LAYER Metal6 ;
        RECT 0.000000 2561.795000 0.290000 2561.865000 ;
    END
  END soc2pipe_mtimer_val_i[22]
  PIN soc2pipe_mtimer_val_i[21]
    DIRECTION INPUT ;
    USE SIGNAL ;
    PORT
      LAYER Metal6 ;
        RECT 0.000000 2576.150000 0.290000 2576.220000 ;
    END
  END soc2pipe_mtimer_val_i[21]
  PIN soc2pipe_mtimer_val_i[20]
    DIRECTION INPUT ;
    USE SIGNAL ;
    PORT
      LAYER Metal6 ;
        RECT 0.000000 2590.500000 0.290000 2590.570000 ;
    END
  END soc2pipe_mtimer_val_i[20]
  PIN soc2pipe_mtimer_val_i[19]
    DIRECTION INPUT ;
    USE SIGNAL ;
    PORT
      LAYER Metal6 ;
        RECT 0.000000 2604.855000 0.290000 2604.925000 ;
    END
  END soc2pipe_mtimer_val_i[19]
  PIN soc2pipe_mtimer_val_i[18]
    DIRECTION INPUT ;
    USE SIGNAL ;
    PORT
      LAYER Metal6 ;
        RECT 0.000000 2619.205000 0.290000 2619.275000 ;
    END
  END soc2pipe_mtimer_val_i[18]
  PIN soc2pipe_mtimer_val_i[17]
    DIRECTION INPUT ;
    USE SIGNAL ;
    PORT
      LAYER Metal6 ;
        RECT 0.000000 2633.555000 0.290000 2633.625000 ;
    END
  END soc2pipe_mtimer_val_i[17]
  PIN soc2pipe_mtimer_val_i[16]
    DIRECTION INPUT ;
    USE SIGNAL ;
    PORT
      LAYER Metal6 ;
        RECT 0.000000 2647.910000 0.290000 2647.980000 ;
    END
  END soc2pipe_mtimer_val_i[16]
  PIN soc2pipe_mtimer_val_i[15]
    DIRECTION INPUT ;
    USE SIGNAL ;
    PORT
      LAYER Metal6 ;
        RECT 0.000000 2662.260000 0.290000 2662.330000 ;
    END
  END soc2pipe_mtimer_val_i[15]
  PIN soc2pipe_mtimer_val_i[14]
    DIRECTION INPUT ;
    USE SIGNAL ;
    PORT
      LAYER Metal6 ;
        RECT 0.000000 2676.615000 0.290000 2676.685000 ;
    END
  END soc2pipe_mtimer_val_i[14]
  PIN soc2pipe_mtimer_val_i[13]
    DIRECTION INPUT ;
    USE SIGNAL ;
    PORT
      LAYER Metal6 ;
        RECT 0.000000 2690.965000 0.290000 2691.035000 ;
    END
  END soc2pipe_mtimer_val_i[13]
  PIN soc2pipe_mtimer_val_i[12]
    DIRECTION INPUT ;
    USE SIGNAL ;
    PORT
      LAYER Metal6 ;
        RECT 0.000000 2705.315000 0.290000 2705.385000 ;
    END
  END soc2pipe_mtimer_val_i[12]
  PIN soc2pipe_mtimer_val_i[11]
    DIRECTION INPUT ;
    USE SIGNAL ;
    PORT
      LAYER Metal6 ;
        RECT 0.000000 2719.670000 0.290000 2719.740000 ;
    END
  END soc2pipe_mtimer_val_i[11]
  PIN soc2pipe_mtimer_val_i[10]
    DIRECTION INPUT ;
    USE SIGNAL ;
    PORT
      LAYER Metal6 ;
        RECT 0.000000 2734.020000 0.290000 2734.090000 ;
    END
  END soc2pipe_mtimer_val_i[10]
  PIN soc2pipe_mtimer_val_i[9]
    DIRECTION INPUT ;
    USE SIGNAL ;
    PORT
      LAYER Metal6 ;
        RECT 0.000000 2748.375000 0.290000 2748.445000 ;
    END
  END soc2pipe_mtimer_val_i[9]
  PIN soc2pipe_mtimer_val_i[8]
    DIRECTION INPUT ;
    USE SIGNAL ;
    PORT
      LAYER Metal6 ;
        RECT 0.000000 2762.725000 0.290000 2762.795000 ;
    END
  END soc2pipe_mtimer_val_i[8]
  PIN soc2pipe_mtimer_val_i[7]
    DIRECTION INPUT ;
    USE SIGNAL ;
    PORT
      LAYER Metal6 ;
        RECT 0.000000 2777.075000 0.290000 2777.145000 ;
    END
  END soc2pipe_mtimer_val_i[7]
  PIN soc2pipe_mtimer_val_i[6]
    DIRECTION INPUT ;
    USE SIGNAL ;
    PORT
      LAYER Metal6 ;
        RECT 0.000000 2791.430000 0.290000 2791.500000 ;
    END
  END soc2pipe_mtimer_val_i[6]
  PIN soc2pipe_mtimer_val_i[5]
    DIRECTION INPUT ;
    USE SIGNAL ;
    PORT
      LAYER Metal6 ;
        RECT 0.000000 2805.780000 0.290000 2805.850000 ;
    END
  END soc2pipe_mtimer_val_i[5]
  PIN soc2pipe_mtimer_val_i[4]
    DIRECTION INPUT ;
    USE SIGNAL ;
    PORT
      LAYER Metal6 ;
        RECT 0.000000 2820.135000 0.290000 2820.205000 ;
    END
  END soc2pipe_mtimer_val_i[4]
  PIN soc2pipe_mtimer_val_i[3]
    DIRECTION INPUT ;
    USE SIGNAL ;
    PORT
      LAYER Metal6 ;
        RECT 0.000000 2834.485000 0.290000 2834.555000 ;
    END
  END soc2pipe_mtimer_val_i[3]
  PIN soc2pipe_mtimer_val_i[2]
    DIRECTION INPUT ;
    USE SIGNAL ;
    PORT
      LAYER Metal6 ;
        RECT 0.000000 2848.835000 0.290000 2848.905000 ;
    END
  END soc2pipe_mtimer_val_i[2]
  PIN soc2pipe_mtimer_val_i[1]
    DIRECTION INPUT ;
    USE SIGNAL ;
    PORT
      LAYER Metal6 ;
        RECT 0.000000 2863.190000 0.290000 2863.260000 ;
    END
  END soc2pipe_mtimer_val_i[1]
  PIN soc2pipe_mtimer_val_i[0]
    DIRECTION INPUT ;
    USE SIGNAL ;
    PORT
      LAYER Metal6 ;
        RECT 0.000000 2877.540000 0.290000 2877.610000 ;
    END
  END soc2pipe_mtimer_val_i[0]
  PIN soc2pipe_fuse_mhartid_i[31]
    DIRECTION INPUT ;
    USE SIGNAL ;
    PORT
      LAYER Metal6 ;
        RECT 0.000000 2891.895000 0.290000 2891.965000 ;
    END
  END soc2pipe_fuse_mhartid_i[31]
  PIN soc2pipe_fuse_mhartid_i[30]
    DIRECTION INPUT ;
    USE SIGNAL ;
    PORT
      LAYER Metal6 ;
        RECT 0.000000 2906.245000 0.290000 2906.315000 ;
    END
  END soc2pipe_fuse_mhartid_i[30]
  PIN soc2pipe_fuse_mhartid_i[29]
    DIRECTION INPUT ;
    USE SIGNAL ;
    PORT
      LAYER Metal6 ;
        RECT 0.000000 2920.595000 0.290000 2920.665000 ;
    END
  END soc2pipe_fuse_mhartid_i[29]
  PIN soc2pipe_fuse_mhartid_i[28]
    DIRECTION INPUT ;
    USE SIGNAL ;
    PORT
      LAYER Metal6 ;
        RECT 0.000000 2934.950000 0.290000 2935.020000 ;
    END
  END soc2pipe_fuse_mhartid_i[28]
  PIN soc2pipe_fuse_mhartid_i[27]
    DIRECTION INPUT ;
    USE SIGNAL ;
    PORT
      LAYER Metal6 ;
        RECT 0.000000 2949.300000 0.290000 2949.370000 ;
    END
  END soc2pipe_fuse_mhartid_i[27]
  PIN soc2pipe_fuse_mhartid_i[26]
    DIRECTION INPUT ;
    USE SIGNAL ;
    PORT
      LAYER Metal6 ;
        RECT 0.000000 2963.655000 0.290000 2963.725000 ;
    END
  END soc2pipe_fuse_mhartid_i[26]
  PIN soc2pipe_fuse_mhartid_i[25]
    DIRECTION INPUT ;
    USE SIGNAL ;
    PORT
      LAYER Metal6 ;
        RECT 0.000000 2978.005000 0.290000 2978.075000 ;
    END
  END soc2pipe_fuse_mhartid_i[25]
  PIN soc2pipe_fuse_mhartid_i[24]
    DIRECTION INPUT ;
    USE SIGNAL ;
    PORT
      LAYER Metal6 ;
        RECT 0.000000 2992.355000 0.290000 2992.425000 ;
    END
  END soc2pipe_fuse_mhartid_i[24]
  PIN soc2pipe_fuse_mhartid_i[23]
    DIRECTION INPUT ;
    USE SIGNAL ;
    PORT
      LAYER Metal6 ;
        RECT 0.000000 3006.710000 0.290000 3006.780000 ;
    END
  END soc2pipe_fuse_mhartid_i[23]
  PIN soc2pipe_fuse_mhartid_i[22]
    DIRECTION INPUT ;
    USE SIGNAL ;
    PORT
      LAYER Metal6 ;
        RECT 0.000000 3021.060000 0.290000 3021.130000 ;
    END
  END soc2pipe_fuse_mhartid_i[22]
  PIN soc2pipe_fuse_mhartid_i[21]
    DIRECTION INPUT ;
    USE SIGNAL ;
    PORT
      LAYER Metal6 ;
        RECT 0.000000 3035.415000 0.290000 3035.485000 ;
    END
  END soc2pipe_fuse_mhartid_i[21]
  PIN soc2pipe_fuse_mhartid_i[20]
    DIRECTION INPUT ;
    USE SIGNAL ;
    PORT
      LAYER Metal6 ;
        RECT 0.000000 3049.765000 0.290000 3049.835000 ;
    END
  END soc2pipe_fuse_mhartid_i[20]
  PIN soc2pipe_fuse_mhartid_i[19]
    DIRECTION INPUT ;
    USE SIGNAL ;
    PORT
      LAYER Metal6 ;
        RECT 0.000000 3064.115000 0.290000 3064.185000 ;
    END
  END soc2pipe_fuse_mhartid_i[19]
  PIN soc2pipe_fuse_mhartid_i[18]
    DIRECTION INPUT ;
    USE SIGNAL ;
    PORT
      LAYER Metal6 ;
        RECT 0.000000 3078.470000 0.290000 3078.540000 ;
    END
  END soc2pipe_fuse_mhartid_i[18]
  PIN soc2pipe_fuse_mhartid_i[17]
    DIRECTION INPUT ;
    USE SIGNAL ;
    PORT
      LAYER Metal6 ;
        RECT 0.000000 3092.820000 0.290000 3092.890000 ;
    END
  END soc2pipe_fuse_mhartid_i[17]
  PIN soc2pipe_fuse_mhartid_i[16]
    DIRECTION INPUT ;
    USE SIGNAL ;
    PORT
      LAYER Metal6 ;
        RECT 0.000000 3107.175000 0.290000 3107.245000 ;
    END
  END soc2pipe_fuse_mhartid_i[16]
  PIN soc2pipe_fuse_mhartid_i[15]
    DIRECTION INPUT ;
    USE SIGNAL ;
    PORT
      LAYER Metal6 ;
        RECT 0.000000 3121.525000 0.290000 3121.595000 ;
    END
  END soc2pipe_fuse_mhartid_i[15]
  PIN soc2pipe_fuse_mhartid_i[14]
    DIRECTION INPUT ;
    USE SIGNAL ;
    PORT
      LAYER Metal6 ;
        RECT 0.000000 3135.875000 0.290000 3135.945000 ;
    END
  END soc2pipe_fuse_mhartid_i[14]
  PIN soc2pipe_fuse_mhartid_i[13]
    DIRECTION INPUT ;
    USE SIGNAL ;
    PORT
      LAYER Metal6 ;
        RECT 0.000000 3150.230000 0.290000 3150.300000 ;
    END
  END soc2pipe_fuse_mhartid_i[13]
  PIN soc2pipe_fuse_mhartid_i[12]
    DIRECTION INPUT ;
    USE SIGNAL ;
    PORT
      LAYER Metal6 ;
        RECT 0.000000 3164.580000 0.290000 3164.650000 ;
    END
  END soc2pipe_fuse_mhartid_i[12]
  PIN soc2pipe_fuse_mhartid_i[11]
    DIRECTION INPUT ;
    USE SIGNAL ;
    PORT
      LAYER Metal6 ;
        RECT 0.000000 3178.935000 0.290000 3179.005000 ;
    END
  END soc2pipe_fuse_mhartid_i[11]
  PIN soc2pipe_fuse_mhartid_i[10]
    DIRECTION INPUT ;
    USE SIGNAL ;
    PORT
      LAYER Metal6 ;
        RECT 0.000000 3193.285000 0.290000 3193.355000 ;
    END
  END soc2pipe_fuse_mhartid_i[10]
  PIN soc2pipe_fuse_mhartid_i[9]
    DIRECTION INPUT ;
    USE SIGNAL ;
    PORT
      LAYER Metal6 ;
        RECT 0.000000 3207.635000 0.290000 3207.705000 ;
    END
  END soc2pipe_fuse_mhartid_i[9]
  PIN soc2pipe_fuse_mhartid_i[8]
    DIRECTION INPUT ;
    USE SIGNAL ;
    PORT
      LAYER Metal6 ;
        RECT 0.000000 3221.990000 0.290000 3222.060000 ;
    END
  END soc2pipe_fuse_mhartid_i[8]
  PIN soc2pipe_fuse_mhartid_i[7]
    DIRECTION INPUT ;
    USE SIGNAL ;
    PORT
      LAYER Metal6 ;
        RECT 0.000000 3236.340000 0.290000 3236.410000 ;
    END
  END soc2pipe_fuse_mhartid_i[7]
  PIN soc2pipe_fuse_mhartid_i[6]
    DIRECTION INPUT ;
    USE SIGNAL ;
    PORT
      LAYER Metal6 ;
        RECT 0.000000 3250.695000 0.290000 3250.765000 ;
    END
  END soc2pipe_fuse_mhartid_i[6]
  PIN soc2pipe_fuse_mhartid_i[5]
    DIRECTION INPUT ;
    USE SIGNAL ;
    PORT
      LAYER Metal6 ;
        RECT 0.000000 3265.045000 0.290000 3265.115000 ;
    END
  END soc2pipe_fuse_mhartid_i[5]
  PIN soc2pipe_fuse_mhartid_i[4]
    DIRECTION INPUT ;
    USE SIGNAL ;
    PORT
      LAYER Metal6 ;
        RECT 0.000000 3279.395000 0.290000 3279.465000 ;
    END
  END soc2pipe_fuse_mhartid_i[4]
  PIN soc2pipe_fuse_mhartid_i[3]
    DIRECTION INPUT ;
    USE SIGNAL ;
    PORT
      LAYER Metal6 ;
        RECT 0.000000 3293.750000 0.290000 3293.820000 ;
    END
  END soc2pipe_fuse_mhartid_i[3]
  PIN soc2pipe_fuse_mhartid_i[2]
    DIRECTION INPUT ;
    USE SIGNAL ;
    PORT
      LAYER Metal6 ;
        RECT 0.000000 3308.100000 0.290000 3308.170000 ;
    END
  END soc2pipe_fuse_mhartid_i[2]
  PIN soc2pipe_fuse_mhartid_i[1]
    DIRECTION INPUT ;
    USE SIGNAL ;
    PORT
      LAYER Metal6 ;
        RECT 0.000000 3322.455000 0.290000 3322.525000 ;
    END
  END soc2pipe_fuse_mhartid_i[1]
  PIN soc2pipe_fuse_mhartid_i[0]
    DIRECTION INPUT ;
    USE SIGNAL ;
    PORT
      LAYER Metal6 ;
        RECT 0.000000 3336.805000 0.290000 3336.875000 ;
    END
  END soc2pipe_fuse_mhartid_i[0]
  PIN clkout
    DIRECTION OUTPUT ;
    USE SIGNAL ;
    PORT
      LAYER Metal6 ;
        RECT 3111.710000 2360.870000 3112.000000 2360.940000 ;
    END
  END clkout
  PIN vdd
    DIRECTION INPUT ;
    USE POWER ;

# P/G power stripe data as pin
    PORT
      LAYER Metal9 ;
        RECT 20.000000 17.140000 21.000000 3320.020000 ;
        RECT 1780.000000 179.025000 1781.000000 3320.020000 ;
        RECT 1310.000000 17.140000 1311.000000 2644.515000 ;
        RECT 1300.000000 17.140000 1301.000000 2644.335000 ;
        RECT 1290.000000 17.140000 1291.000000 2644.335000 ;
        RECT 1280.000000 17.140000 1281.000000 2644.335000 ;
        RECT 1270.000000 17.140000 1271.000000 2644.335000 ;
        RECT 1260.000000 17.140000 1261.000000 2644.335000 ;
        RECT 3093.000000 17.140000 3095.000000 3320.020000 ;
        RECT 17.000000 17.140000 19.000000 3320.020000 ;
        RECT 17.000000 54.280000 19.935000 54.400000 ;
        RECT 17.000000 132.940000 19.995000 133.060000 ;
        RECT 45.405000 132.940000 51.000000 133.060000 ;
        RECT 17.000000 184.240000 19.980000 184.360000 ;
        RECT 17.000000 201.340000 19.515000 201.460000 ;
        RECT 45.420000 184.240000 51.000000 184.360000 ;
        RECT 45.815000 201.340000 51.000000 201.460000 ;
        RECT 17.000000 262.900000 19.955000 263.020000 ;
        RECT 45.445000 262.900000 51.000000 263.020000 ;
        RECT 17.000000 331.300000 19.515000 331.420000 ;
        RECT 45.770000 331.300000 51.000000 331.420000 ;
        RECT 17.000000 392.860000 19.515000 392.980000 ;
        RECT 45.770000 392.860000 51.000000 392.980000 ;
        RECT 17.000000 461.260000 19.955000 461.380000 ;
        RECT 45.445000 461.260000 51.000000 461.380000 ;
        RECT 17.000000 522.820000 19.515000 522.940000 ;
        RECT 17.000000 539.920000 19.980000 540.040000 ;
        RECT 45.815000 522.820000 51.000000 522.940000 ;
        RECT 45.420000 539.920000 51.000000 540.040000 ;
        RECT 17.000000 591.220000 19.995000 591.340000 ;
        RECT 45.405000 591.220000 51.000000 591.340000 ;
        RECT 17.000000 669.880000 19.935000 670.000000 ;
        RECT 45.480000 669.880000 51.000000 670.000000 ;
        RECT 17.000000 714.340000 19.515000 714.460000 ;
        RECT 45.815000 714.340000 51.000000 714.460000 ;
        RECT 17.000000 799.840000 19.515000 799.960000 ;
        RECT 45.790000 799.840000 51.000000 799.960000 ;
        RECT 1150.000000 132.940000 1152.595000 133.060000 ;
        RECT 1150.000000 184.240000 1152.580000 184.360000 ;
        RECT 1150.000000 201.340000 1152.185000 201.460000 ;
        RECT 1150.000000 262.900000 1152.555000 263.020000 ;
        RECT 1150.000000 331.300000 1152.230000 331.420000 ;
        RECT 1150.000000 392.860000 1152.230000 392.980000 ;
        RECT 1150.000000 461.260000 1152.555000 461.380000 ;
        RECT 1150.000000 522.820000 1152.185000 522.940000 ;
        RECT 1150.000000 539.920000 1152.580000 540.040000 ;
        RECT 1150.000000 584.380000 1152.105000 584.500000 ;
        RECT 1150.000000 591.220000 1152.595000 591.340000 ;
        RECT 1150.000000 669.880000 1152.520000 670.000000 ;
        RECT 1150.000000 714.340000 1152.185000 714.460000 ;
        RECT 1150.000000 799.840000 1152.210000 799.960000 ;
        RECT 17.000000 844.300000 19.515000 844.420000 ;
        RECT 17.000000 974.260000 19.955000 974.380000 ;
        RECT 45.445000 974.260000 51.000000 974.380000 ;
        RECT 17.000000 1052.920000 19.980000 1053.040000 ;
        RECT 45.420000 1052.920000 51.000000 1053.040000 ;
        RECT 17.000000 1104.220000 19.995000 1104.340000 ;
        RECT 17.000000 1121.320000 19.515000 1121.440000 ;
        RECT 45.405000 1104.220000 51.000000 1104.340000 ;
        RECT 45.790000 1121.320000 51.000000 1121.440000 ;
        RECT 17.000000 1182.880000 19.935000 1183.000000 ;
        RECT 45.480000 1182.880000 51.000000 1183.000000 ;
        RECT 17.000000 1251.280000 19.935000 1251.400000 ;
        RECT 45.480000 1251.280000 51.000000 1251.400000 ;
        RECT 45.445000 1459.900000 51.000000 1460.020000 ;
        RECT 17.000000 1459.900000 19.955000 1460.020000 ;
        RECT 17.000000 1312.840000 19.515000 1312.960000 ;
        RECT 17.000000 1329.940000 19.995000 1330.060000 ;
        RECT 45.790000 1312.840000 51.000000 1312.960000 ;
        RECT 45.405000 1329.940000 51.000000 1330.060000 ;
        RECT 17.000000 1381.240000 19.980000 1381.360000 ;
        RECT 45.420000 1381.240000 51.000000 1381.360000 ;
        RECT 17.000000 1589.860000 19.515000 1589.980000 ;
        RECT 45.770000 1589.860000 51.000000 1589.980000 ;
        RECT 17.000000 1634.320000 19.515000 1634.440000 ;
        RECT 1150.000000 974.260000 1152.555000 974.380000 ;
        RECT 1150.000000 981.100000 1151.315000 981.220000 ;
        RECT 1150.000000 991.360000 1152.155000 991.480000 ;
        RECT 1150.000000 1052.920000 1152.580000 1053.040000 ;
        RECT 1150.000000 1104.220000 1152.595000 1104.340000 ;
        RECT 1150.000000 1121.320000 1152.210000 1121.440000 ;
        RECT 1150.000000 1182.880000 1152.520000 1183.000000 ;
        RECT 1150.000000 1251.280000 1152.520000 1251.400000 ;
        RECT 1150.000000 1459.900000 1152.555000 1460.020000 ;
        RECT 1150.000000 1312.840000 1152.210000 1312.960000 ;
        RECT 1150.000000 1329.940000 1152.595000 1330.060000 ;
        RECT 1150.000000 1381.240000 1152.580000 1381.360000 ;
        RECT 1150.000000 1589.860000 1152.230000 1589.980000 ;
        RECT 1780.000000 17.140000 1781.000000 105.375000 ;
        RECT 3092.080000 54.280000 3095.000000 54.400000 ;
        RECT 3092.005000 132.940000 3095.000000 133.060000 ;
        RECT 3092.020000 184.240000 3095.000000 184.360000 ;
        RECT 3092.485000 201.340000 3095.000000 201.460000 ;
        RECT 3092.045000 262.900000 3095.000000 263.020000 ;
        RECT 3092.485000 331.300000 3095.000000 331.420000 ;
        RECT 3092.485000 392.860000 3095.000000 392.980000 ;
        RECT 3092.045000 461.260000 3095.000000 461.380000 ;
        RECT 3092.485000 522.820000 3095.000000 522.940000 ;
        RECT 3092.020000 539.920000 3095.000000 540.040000 ;
        RECT 3092.005000 591.220000 3095.000000 591.340000 ;
        RECT 3092.080000 669.880000 3095.000000 670.000000 ;
        RECT 3092.485000 714.340000 3095.000000 714.460000 ;
        RECT 3092.485000 799.840000 3095.000000 799.960000 ;
        RECT 3092.485000 844.300000 3095.000000 844.420000 ;
        RECT 3092.045000 974.260000 3095.000000 974.380000 ;
        RECT 3092.020000 1052.920000 3095.000000 1053.040000 ;
        RECT 3092.005000 1104.220000 3095.000000 1104.340000 ;
        RECT 3092.485000 1121.320000 3095.000000 1121.440000 ;
        RECT 3092.080000 1182.880000 3095.000000 1183.000000 ;
        RECT 3092.080000 1251.280000 3095.000000 1251.400000 ;
        RECT 3092.045000 1459.900000 3095.000000 1460.020000 ;
        RECT 3092.485000 1312.840000 3095.000000 1312.960000 ;
        RECT 3092.005000 1329.940000 3095.000000 1330.060000 ;
        RECT 3092.020000 1381.240000 3095.000000 1381.360000 ;
        RECT 3092.485000 1589.860000 3095.000000 1589.980000 ;
        RECT 3092.485000 1634.320000 3095.000000 1634.440000 ;
        RECT 17.000000 1719.820000 19.515000 1719.940000 ;
        RECT 45.815000 1719.820000 51.000000 1719.940000 ;
        RECT 17.000000 1764.280000 19.935000 1764.400000 ;
        RECT 45.480000 1764.280000 51.000000 1764.400000 ;
        RECT 17.000000 1842.940000 19.995000 1843.060000 ;
        RECT 45.405000 1842.940000 51.000000 1843.060000 ;
        RECT 17.000000 1894.240000 19.980000 1894.360000 ;
        RECT 17.000000 1911.340000 19.515000 1911.460000 ;
        RECT 45.420000 1894.240000 51.000000 1894.360000 ;
        RECT 45.815000 1911.340000 51.000000 1911.460000 ;
        RECT 17.000000 1972.900000 19.955000 1973.020000 ;
        RECT 45.445000 1972.900000 51.000000 1973.020000 ;
        RECT 17.000000 2041.300000 19.515000 2041.420000 ;
        RECT 45.770000 2041.300000 51.000000 2041.420000 ;
        RECT 17.000000 2102.860000 19.515000 2102.980000 ;
        RECT 45.770000 2102.860000 51.000000 2102.980000 ;
        RECT 17.000000 2171.260000 19.955000 2171.380000 ;
        RECT 45.445000 2171.260000 51.000000 2171.380000 ;
        RECT 17.000000 2232.820000 19.515000 2232.940000 ;
        RECT 45.815000 2232.820000 51.000000 2232.940000 ;
        RECT 17.000000 2249.920000 19.980000 2250.040000 ;
        RECT 45.420000 2249.920000 51.000000 2250.040000 ;
        RECT 17.000000 2301.220000 19.995000 2301.340000 ;
        RECT 45.405000 2301.220000 51.000000 2301.340000 ;
        RECT 17.000000 2379.880000 19.935000 2380.000000 ;
        RECT 45.480000 2379.880000 51.000000 2380.000000 ;
        RECT 17.000000 2424.340000 19.515000 2424.460000 ;
        RECT 45.815000 2424.340000 51.000000 2424.460000 ;
        RECT 1150.000000 1719.820000 1152.185000 1719.940000 ;
        RECT 1150.000000 1764.280000 1152.520000 1764.400000 ;
        RECT 1150.000000 1842.940000 1152.595000 1843.060000 ;
        RECT 1150.000000 1860.040000 1151.315000 1860.160000 ;
        RECT 1150.000000 1894.240000 1152.580000 1894.360000 ;
        RECT 1150.000000 1911.340000 1152.185000 1911.460000 ;
        RECT 1150.000000 1972.900000 1152.555000 1973.020000 ;
        RECT 1150.000000 2041.300000 1152.230000 2041.420000 ;
        RECT 1150.000000 2102.860000 1152.230000 2102.980000 ;
        RECT 1150.000000 2171.260000 1152.555000 2171.380000 ;
        RECT 1150.000000 2232.820000 1152.185000 2232.940000 ;
        RECT 1150.000000 2249.920000 1152.580000 2250.040000 ;
        RECT 1150.000000 2301.220000 1152.595000 2301.340000 ;
        RECT 1150.000000 2379.880000 1152.520000 2380.000000 ;
        RECT 1150.000000 2424.340000 1152.185000 2424.460000 ;
        RECT 17.000000 2509.840000 19.515000 2509.960000 ;
        RECT 17.000000 2554.300000 19.515000 2554.420000 ;
        RECT 45.770000 2554.300000 51.000000 2554.420000 ;
        RECT 17.000000 2684.260000 19.955000 2684.380000 ;
        RECT 45.445000 2684.260000 51.000000 2684.380000 ;
        RECT 17.000000 2762.920000 19.980000 2763.040000 ;
        RECT 45.420000 2762.920000 51.000000 2763.040000 ;
        RECT 17.000000 2814.220000 19.995000 2814.340000 ;
        RECT 45.405000 2814.220000 51.000000 2814.340000 ;
        RECT 17.000000 2831.320000 19.515000 2831.440000 ;
        RECT 45.790000 2831.320000 51.000000 2831.440000 ;
        RECT 17.000000 2892.880000 19.935000 2893.000000 ;
        RECT 45.480000 2892.880000 51.000000 2893.000000 ;
        RECT 17.000000 2961.280000 19.935000 2961.400000 ;
        RECT 45.480000 2961.280000 51.000000 2961.400000 ;
        RECT 17.000000 3022.840000 19.515000 3022.960000 ;
        RECT 45.790000 3022.840000 51.000000 3022.960000 ;
        RECT 17.000000 3039.940000 19.995000 3040.060000 ;
        RECT 45.405000 3039.940000 51.000000 3040.060000 ;
        RECT 17.000000 3091.240000 19.980000 3091.360000 ;
        RECT 45.420000 3091.240000 51.000000 3091.360000 ;
        RECT 17.000000 3169.900000 19.955000 3170.020000 ;
        RECT 45.445000 3169.900000 51.000000 3170.020000 ;
        RECT 17.000000 3299.860000 19.515000 3299.980000 ;
        RECT 1310.000000 2700.705000 1311.000000 3320.020000 ;
        RECT 1300.000000 2700.885000 1301.000000 3320.020000 ;
        RECT 1290.000000 2700.885000 1291.000000 3320.020000 ;
        RECT 1280.000000 2700.885000 1281.000000 3320.020000 ;
        RECT 1270.000000 2700.885000 1271.000000 3320.020000 ;
        RECT 1260.000000 2700.885000 1261.000000 3320.020000 ;
        RECT 1150.000000 2554.300000 1152.230000 2554.420000 ;
        RECT 1150.000000 2684.260000 1152.555000 2684.380000 ;
        RECT 1150.000000 2701.360000 1152.155000 2701.480000 ;
        RECT 1150.000000 2762.920000 1152.580000 2763.040000 ;
        RECT 1150.000000 2814.220000 1152.595000 2814.340000 ;
        RECT 1150.000000 2831.320000 1152.210000 2831.440000 ;
        RECT 1150.000000 2892.880000 1152.520000 2893.000000 ;
        RECT 1150.000000 2961.280000 1152.520000 2961.400000 ;
        RECT 1150.000000 3022.840000 1152.210000 3022.960000 ;
        RECT 1150.000000 3039.940000 1152.595000 3040.060000 ;
        RECT 1150.000000 3091.240000 1152.580000 3091.360000 ;
        RECT 1150.000000 3152.800000 1152.155000 3152.920000 ;
        RECT 1150.000000 3169.900000 1152.555000 3170.020000 ;
        RECT 3092.485000 1719.820000 3095.000000 1719.940000 ;
        RECT 3092.080000 1764.280000 3095.000000 1764.400000 ;
        RECT 3092.005000 1842.940000 3095.000000 1843.060000 ;
        RECT 3092.020000 1894.240000 3095.000000 1894.360000 ;
        RECT 3092.485000 1911.340000 3095.000000 1911.460000 ;
        RECT 3092.045000 1972.900000 3095.000000 1973.020000 ;
        RECT 3092.485000 2041.300000 3095.000000 2041.420000 ;
        RECT 3092.485000 2102.860000 3095.000000 2102.980000 ;
        RECT 3092.045000 2171.260000 3095.000000 2171.380000 ;
        RECT 3092.485000 2232.820000 3095.000000 2232.940000 ;
        RECT 3092.020000 2249.920000 3095.000000 2250.040000 ;
        RECT 3092.005000 2301.220000 3095.000000 2301.340000 ;
        RECT 3092.080000 2379.880000 3095.000000 2380.000000 ;
        RECT 3092.485000 2424.340000 3095.000000 2424.460000 ;
        RECT 1820.000000 2684.260000 1821.315000 2684.380000 ;
        RECT 1820.000000 2831.320000 1821.315000 2831.440000 ;
        RECT 1820.000000 2892.880000 1821.315000 2893.000000 ;
        RECT 1820.000000 2961.280000 1821.315000 2961.400000 ;
        RECT 1820.000000 3022.840000 1821.315000 3022.960000 ;
        RECT 1820.000000 3039.940000 1821.315000 3040.060000 ;
        RECT 1820.000000 3091.240000 1821.315000 3091.360000 ;
        RECT 1820.000000 3169.900000 1821.315000 3170.020000 ;
        RECT 3092.485000 2509.840000 3095.000000 2509.960000 ;
        RECT 3092.485000 2554.300000 3095.000000 2554.420000 ;
        RECT 3092.045000 2684.260000 3095.000000 2684.380000 ;
        RECT 3092.020000 2762.920000 3095.000000 2763.040000 ;
        RECT 3092.005000 2814.220000 3095.000000 2814.340000 ;
        RECT 3092.485000 2831.320000 3095.000000 2831.440000 ;
        RECT 3092.080000 2892.880000 3095.000000 2893.000000 ;
        RECT 3092.080000 2961.280000 3095.000000 2961.400000 ;
        RECT 3092.485000 3022.840000 3095.000000 3022.960000 ;
        RECT 3092.005000 3039.940000 3095.000000 3040.060000 ;
        RECT 3092.020000 3091.240000 3095.000000 3091.360000 ;
        RECT 3092.045000 3169.900000 3095.000000 3170.020000 ;
        RECT 3092.485000 3299.860000 3095.000000 3299.980000 ;
        RECT 1320.000000 17.140000 1321.000000 3320.020000 ;
        RECT 1330.000000 17.140000 1331.000000 3320.020000 ;
        RECT 1340.000000 17.140000 1341.000000 3320.020000 ;
        RECT 1350.000000 17.140000 1351.000000 3320.020000 ;
        RECT 1360.000000 17.140000 1361.000000 3320.020000 ;
        RECT 1370.000000 17.140000 1371.000000 3320.020000 ;
        RECT 1380.000000 17.140000 1381.000000 3320.020000 ;
        RECT 1390.000000 17.140000 1391.000000 3320.020000 ;
        RECT 1400.000000 17.140000 1401.000000 3320.020000 ;
        RECT 1410.000000 17.140000 1411.000000 3320.020000 ;
        RECT 1420.000000 17.140000 1421.000000 3320.020000 ;
        RECT 1430.000000 17.140000 1431.000000 3320.020000 ;
        RECT 1440.000000 17.140000 1441.000000 3320.020000 ;
        RECT 1450.000000 17.140000 1451.000000 3320.020000 ;
        RECT 1460.000000 17.140000 1461.000000 3320.020000 ;
        RECT 1470.000000 17.140000 1471.000000 3320.020000 ;
        RECT 1480.000000 17.140000 1481.000000 3320.020000 ;
        RECT 1490.000000 17.140000 1491.000000 3320.020000 ;
        RECT 1500.000000 17.140000 1501.000000 3320.020000 ;
        RECT 1510.000000 17.140000 1511.000000 3320.020000 ;
        RECT 1520.000000 17.140000 1521.000000 3320.020000 ;
        RECT 1530.000000 17.140000 1531.000000 3320.020000 ;
        RECT 1540.000000 17.140000 1541.000000 3320.020000 ;
        RECT 1550.000000 17.140000 1551.000000 3320.020000 ;
        RECT 1560.000000 17.140000 1561.000000 3320.020000 ;
        RECT 1570.000000 17.140000 1571.000000 3320.020000 ;
        RECT 1580.000000 17.140000 1581.000000 3320.020000 ;
        RECT 1590.000000 17.140000 1591.000000 3320.020000 ;
        RECT 1600.000000 17.140000 1601.000000 3320.020000 ;
        RECT 1610.000000 17.140000 1611.000000 3320.020000 ;
        RECT 1620.000000 17.140000 1621.000000 3320.020000 ;
        RECT 1630.000000 17.140000 1631.000000 3320.020000 ;
        RECT 1640.000000 17.140000 1641.000000 3320.020000 ;
        RECT 1650.000000 17.140000 1651.000000 3320.020000 ;
        RECT 1660.000000 17.140000 1661.000000 3320.020000 ;
        RECT 1670.000000 17.140000 1671.000000 3320.020000 ;
        RECT 1680.000000 17.140000 1681.000000 3320.020000 ;
        RECT 1690.000000 17.140000 1691.000000 3320.020000 ;
        RECT 1700.000000 17.140000 1701.000000 3320.020000 ;
        RECT 1710.000000 17.140000 1711.000000 3320.020000 ;
        RECT 1720.000000 17.140000 1721.000000 3320.020000 ;
        RECT 1730.000000 17.140000 1731.000000 3320.020000 ;
        RECT 1740.000000 17.140000 1741.000000 3320.020000 ;
        RECT 1750.000000 17.140000 1751.000000 3320.020000 ;
        RECT 1760.000000 17.140000 1761.000000 3320.020000 ;
        RECT 1770.000000 17.140000 1771.000000 3320.020000 ;
        RECT 30.000000 17.140000 31.000000 3320.020000 ;
        RECT 40.000000 17.140000 41.000000 3320.020000 ;
        RECT 50.000000 17.140000 51.000000 3320.020000 ;
        RECT 60.000000 17.140000 61.000000 3320.020000 ;
        RECT 70.000000 17.140000 71.000000 3320.020000 ;
        RECT 80.000000 17.140000 81.000000 3320.020000 ;
        RECT 90.000000 17.140000 91.000000 3320.020000 ;
        RECT 100.000000 17.140000 101.000000 3320.020000 ;
        RECT 110.000000 17.140000 111.000000 3320.020000 ;
        RECT 120.000000 17.140000 121.000000 3320.020000 ;
        RECT 130.000000 17.140000 131.000000 3320.020000 ;
        RECT 140.000000 17.140000 141.000000 3320.020000 ;
        RECT 150.000000 17.140000 151.000000 3320.020000 ;
        RECT 160.000000 17.140000 161.000000 3320.020000 ;
        RECT 170.000000 17.140000 171.000000 3320.020000 ;
        RECT 180.000000 17.140000 181.000000 3320.020000 ;
        RECT 190.000000 17.140000 191.000000 3320.020000 ;
        RECT 200.000000 17.140000 201.000000 3320.020000 ;
        RECT 210.000000 17.140000 211.000000 3320.020000 ;
        RECT 220.000000 17.140000 221.000000 3320.020000 ;
        RECT 230.000000 17.140000 231.000000 3320.020000 ;
        RECT 240.000000 17.140000 241.000000 3320.020000 ;
        RECT 250.000000 17.140000 251.000000 3320.020000 ;
        RECT 260.000000 17.140000 261.000000 3320.020000 ;
        RECT 270.000000 17.140000 271.000000 3320.020000 ;
        RECT 280.000000 17.140000 281.000000 3320.020000 ;
        RECT 290.000000 17.140000 291.000000 3320.020000 ;
        RECT 300.000000 17.140000 301.000000 3320.020000 ;
        RECT 310.000000 17.140000 311.000000 3320.020000 ;
        RECT 320.000000 17.140000 321.000000 3320.020000 ;
        RECT 330.000000 17.140000 331.000000 3320.020000 ;
        RECT 340.000000 17.140000 341.000000 3320.020000 ;
        RECT 350.000000 17.140000 351.000000 3320.020000 ;
        RECT 360.000000 17.140000 361.000000 3320.020000 ;
        RECT 370.000000 17.140000 371.000000 3320.020000 ;
        RECT 380.000000 17.140000 381.000000 3320.020000 ;
        RECT 390.000000 17.140000 391.000000 3320.020000 ;
        RECT 400.000000 17.140000 401.000000 3320.020000 ;
        RECT 410.000000 17.140000 411.000000 3320.020000 ;
        RECT 420.000000 17.140000 421.000000 3320.020000 ;
        RECT 430.000000 17.140000 431.000000 3320.020000 ;
        RECT 440.000000 17.140000 441.000000 3320.020000 ;
        RECT 450.000000 17.140000 451.000000 3320.020000 ;
        RECT 460.000000 17.140000 461.000000 3320.020000 ;
        RECT 470.000000 17.140000 471.000000 3320.020000 ;
        RECT 480.000000 17.140000 481.000000 3320.020000 ;
        RECT 490.000000 17.140000 491.000000 3320.020000 ;
        RECT 500.000000 17.140000 501.000000 3320.020000 ;
        RECT 510.000000 17.140000 511.000000 3320.020000 ;
        RECT 520.000000 17.140000 521.000000 3320.020000 ;
        RECT 530.000000 17.140000 531.000000 3320.020000 ;
        RECT 540.000000 17.140000 541.000000 3320.020000 ;
        RECT 550.000000 17.140000 551.000000 3320.020000 ;
        RECT 560.000000 17.140000 561.000000 3320.020000 ;
        RECT 570.000000 17.140000 571.000000 3320.020000 ;
        RECT 580.000000 17.140000 581.000000 3320.020000 ;
        RECT 590.000000 17.140000 591.000000 3320.020000 ;
        RECT 600.000000 17.140000 601.000000 3320.020000 ;
        RECT 610.000000 17.140000 611.000000 3320.020000 ;
        RECT 620.000000 17.140000 621.000000 3320.020000 ;
        RECT 630.000000 17.140000 631.000000 3320.020000 ;
        RECT 640.000000 17.140000 641.000000 3320.020000 ;
        RECT 650.000000 17.140000 651.000000 3320.020000 ;
        RECT 660.000000 17.140000 661.000000 3320.020000 ;
        RECT 670.000000 17.140000 671.000000 3320.020000 ;
        RECT 680.000000 17.140000 681.000000 3320.020000 ;
        RECT 690.000000 17.140000 691.000000 3320.020000 ;
        RECT 700.000000 17.140000 701.000000 3320.020000 ;
        RECT 710.000000 17.140000 711.000000 3320.020000 ;
        RECT 720.000000 17.140000 721.000000 3320.020000 ;
        RECT 730.000000 17.140000 731.000000 3320.020000 ;
        RECT 740.000000 17.140000 741.000000 3320.020000 ;
        RECT 750.000000 17.140000 751.000000 3320.020000 ;
        RECT 760.000000 17.140000 761.000000 3320.020000 ;
        RECT 770.000000 17.140000 771.000000 3320.020000 ;
        RECT 780.000000 17.140000 781.000000 3320.020000 ;
        RECT 790.000000 17.140000 791.000000 3320.020000 ;
        RECT 800.000000 17.140000 801.000000 3320.020000 ;
        RECT 810.000000 17.140000 811.000000 3320.020000 ;
        RECT 820.000000 17.140000 821.000000 3320.020000 ;
        RECT 830.000000 17.140000 831.000000 3320.020000 ;
        RECT 840.000000 17.140000 841.000000 3320.020000 ;
        RECT 850.000000 17.140000 851.000000 3320.020000 ;
        RECT 860.000000 17.140000 861.000000 3320.020000 ;
        RECT 870.000000 17.140000 871.000000 3320.020000 ;
        RECT 880.000000 17.140000 881.000000 3320.020000 ;
        RECT 890.000000 17.140000 891.000000 3320.020000 ;
        RECT 900.000000 17.140000 901.000000 3320.020000 ;
        RECT 910.000000 17.140000 911.000000 3320.020000 ;
        RECT 920.000000 17.140000 921.000000 3320.020000 ;
        RECT 930.000000 17.140000 931.000000 3320.020000 ;
        RECT 940.000000 17.140000 941.000000 3320.020000 ;
        RECT 950.000000 17.140000 951.000000 3320.020000 ;
        RECT 960.000000 17.140000 961.000000 3320.020000 ;
        RECT 970.000000 17.140000 971.000000 3320.020000 ;
        RECT 980.000000 17.140000 981.000000 3320.020000 ;
        RECT 990.000000 17.140000 991.000000 3320.020000 ;
        RECT 1000.000000 17.140000 1001.000000 3320.020000 ;
        RECT 1010.000000 17.140000 1011.000000 3320.020000 ;
        RECT 1020.000000 17.140000 1021.000000 3320.020000 ;
        RECT 1030.000000 17.140000 1031.000000 3320.020000 ;
        RECT 1040.000000 17.140000 1041.000000 3320.020000 ;
        RECT 1050.000000 17.140000 1051.000000 3320.020000 ;
        RECT 1060.000000 17.140000 1061.000000 3320.020000 ;
        RECT 1070.000000 17.140000 1071.000000 3320.020000 ;
        RECT 1080.000000 17.140000 1081.000000 3320.020000 ;
        RECT 1090.000000 17.140000 1091.000000 3320.020000 ;
        RECT 1100.000000 17.140000 1101.000000 3320.020000 ;
        RECT 1110.000000 17.140000 1111.000000 3320.020000 ;
        RECT 1120.000000 17.140000 1121.000000 3320.020000 ;
        RECT 1130.000000 17.140000 1131.000000 3320.020000 ;
        RECT 1140.000000 17.140000 1141.000000 3320.020000 ;
        RECT 1150.000000 17.140000 1151.000000 3320.020000 ;
        RECT 1160.000000 17.140000 1161.000000 3320.020000 ;
        RECT 1170.000000 17.140000 1171.000000 3320.020000 ;
        RECT 1180.000000 17.140000 1181.000000 3320.020000 ;
        RECT 1190.000000 17.140000 1191.000000 3320.020000 ;
        RECT 1200.000000 17.140000 1201.000000 3320.020000 ;
        RECT 1210.000000 17.140000 1211.000000 3320.020000 ;
        RECT 1220.000000 17.140000 1221.000000 3320.020000 ;
        RECT 1230.000000 17.140000 1231.000000 3320.020000 ;
        RECT 1240.000000 17.140000 1241.000000 3320.020000 ;
        RECT 1250.000000 17.140000 1251.000000 3320.020000 ;
        RECT 1850.000000 17.140000 1851.000000 3320.020000 ;
        RECT 1860.000000 17.140000 1861.000000 3320.020000 ;
        RECT 1870.000000 17.140000 1871.000000 3320.020000 ;
        RECT 1880.000000 17.140000 1881.000000 3320.020000 ;
        RECT 1890.000000 17.140000 1891.000000 3320.020000 ;
        RECT 1900.000000 17.140000 1901.000000 3320.020000 ;
        RECT 1910.000000 17.140000 1911.000000 3320.020000 ;
        RECT 1920.000000 17.140000 1921.000000 3320.020000 ;
        RECT 1930.000000 17.140000 1931.000000 3320.020000 ;
        RECT 1940.000000 17.140000 1941.000000 3320.020000 ;
        RECT 1950.000000 17.140000 1951.000000 3320.020000 ;
        RECT 1960.000000 17.140000 1961.000000 3320.020000 ;
        RECT 1970.000000 17.140000 1971.000000 3320.020000 ;
        RECT 1980.000000 17.140000 1981.000000 3320.020000 ;
        RECT 1990.000000 17.140000 1991.000000 3320.020000 ;
        RECT 2000.000000 17.140000 2001.000000 3320.020000 ;
        RECT 2010.000000 17.140000 2011.000000 3320.020000 ;
        RECT 2020.000000 17.140000 2021.000000 3320.020000 ;
        RECT 2030.000000 17.140000 2031.000000 3320.020000 ;
        RECT 2040.000000 17.140000 2041.000000 3320.020000 ;
        RECT 2050.000000 17.140000 2051.000000 3320.020000 ;
        RECT 2060.000000 17.140000 2061.000000 3320.020000 ;
        RECT 2070.000000 17.140000 2071.000000 3320.020000 ;
        RECT 2080.000000 17.140000 2081.000000 3320.020000 ;
        RECT 2090.000000 17.140000 2091.000000 3320.020000 ;
        RECT 2100.000000 17.140000 2101.000000 3320.020000 ;
        RECT 2110.000000 17.140000 2111.000000 3320.020000 ;
        RECT 2120.000000 17.140000 2121.000000 3320.020000 ;
        RECT 2130.000000 17.140000 2131.000000 3320.020000 ;
        RECT 2140.000000 17.140000 2141.000000 3320.020000 ;
        RECT 2150.000000 17.140000 2151.000000 3320.020000 ;
        RECT 2160.000000 17.140000 2161.000000 3320.020000 ;
        RECT 2170.000000 17.140000 2171.000000 3320.020000 ;
        RECT 2180.000000 17.140000 2181.000000 3320.020000 ;
        RECT 2190.000000 17.140000 2191.000000 3320.020000 ;
        RECT 2200.000000 17.140000 2201.000000 3320.020000 ;
        RECT 2210.000000 17.140000 2211.000000 3320.020000 ;
        RECT 2220.000000 17.140000 2221.000000 3320.020000 ;
        RECT 2230.000000 17.140000 2231.000000 3320.020000 ;
        RECT 2240.000000 17.140000 2241.000000 3320.020000 ;
        RECT 2250.000000 17.140000 2251.000000 3320.020000 ;
        RECT 2260.000000 17.140000 2261.000000 3320.020000 ;
        RECT 2270.000000 17.140000 2271.000000 3320.020000 ;
        RECT 2280.000000 17.140000 2281.000000 3320.020000 ;
        RECT 2290.000000 17.140000 2291.000000 3320.020000 ;
        RECT 2300.000000 17.140000 2301.000000 3320.020000 ;
        RECT 2310.000000 17.140000 2311.000000 3320.020000 ;
        RECT 2320.000000 17.140000 2321.000000 3320.020000 ;
        RECT 2330.000000 17.140000 2331.000000 3320.020000 ;
        RECT 2340.000000 17.140000 2341.000000 3320.020000 ;
        RECT 2350.000000 17.140000 2351.000000 3320.020000 ;
        RECT 2360.000000 17.140000 2361.000000 3320.020000 ;
        RECT 2370.000000 17.140000 2371.000000 3320.020000 ;
        RECT 2380.000000 17.140000 2381.000000 3320.020000 ;
        RECT 2390.000000 17.140000 2391.000000 3320.020000 ;
        RECT 2400.000000 17.140000 2401.000000 3320.020000 ;
        RECT 2410.000000 17.140000 2411.000000 3320.020000 ;
        RECT 2420.000000 17.140000 2421.000000 3320.020000 ;
        RECT 2430.000000 17.140000 2431.000000 3320.020000 ;
        RECT 2440.000000 17.140000 2441.000000 3320.020000 ;
        RECT 2450.000000 17.140000 2451.000000 3320.020000 ;
        RECT 2460.000000 17.140000 2461.000000 3320.020000 ;
        RECT 2470.000000 17.140000 2471.000000 3320.020000 ;
        RECT 2480.000000 17.140000 2481.000000 3320.020000 ;
        RECT 2490.000000 17.140000 2491.000000 3320.020000 ;
        RECT 2500.000000 17.140000 2501.000000 3320.020000 ;
        RECT 2510.000000 17.140000 2511.000000 3320.020000 ;
        RECT 2520.000000 17.140000 2521.000000 3320.020000 ;
        RECT 2530.000000 17.140000 2531.000000 3320.020000 ;
        RECT 2540.000000 17.140000 2541.000000 3320.020000 ;
        RECT 2550.000000 17.140000 2551.000000 3320.020000 ;
        RECT 2560.000000 17.140000 2561.000000 3320.020000 ;
        RECT 2570.000000 17.140000 2571.000000 3320.020000 ;
        RECT 2580.000000 17.140000 2581.000000 3320.020000 ;
        RECT 2590.000000 17.140000 2591.000000 3320.020000 ;
        RECT 2600.000000 17.140000 2601.000000 3320.020000 ;
        RECT 2610.000000 17.140000 2611.000000 3320.020000 ;
        RECT 2620.000000 17.140000 2621.000000 3320.020000 ;
        RECT 2630.000000 17.140000 2631.000000 3320.020000 ;
        RECT 2640.000000 17.140000 2641.000000 3320.020000 ;
        RECT 2650.000000 17.140000 2651.000000 3320.020000 ;
        RECT 2660.000000 17.140000 2661.000000 3320.020000 ;
        RECT 2670.000000 17.140000 2671.000000 3320.020000 ;
        RECT 2680.000000 17.140000 2681.000000 3320.020000 ;
        RECT 2690.000000 17.140000 2691.000000 3320.020000 ;
        RECT 2700.000000 17.140000 2701.000000 3320.020000 ;
        RECT 2710.000000 17.140000 2711.000000 3320.020000 ;
        RECT 2720.000000 17.140000 2721.000000 3320.020000 ;
        RECT 2730.000000 17.140000 2731.000000 3320.020000 ;
        RECT 2740.000000 17.140000 2741.000000 3320.020000 ;
        RECT 2750.000000 17.140000 2751.000000 3320.020000 ;
        RECT 2760.000000 17.140000 2761.000000 3320.020000 ;
        RECT 2770.000000 17.140000 2771.000000 3320.020000 ;
        RECT 2780.000000 17.140000 2781.000000 3320.020000 ;
        RECT 2790.000000 17.140000 2791.000000 3320.020000 ;
        RECT 2800.000000 17.140000 2801.000000 3320.020000 ;
        RECT 2810.000000 17.140000 2811.000000 3320.020000 ;
        RECT 2820.000000 17.140000 2821.000000 3320.020000 ;
        RECT 2830.000000 17.140000 2831.000000 3320.020000 ;
        RECT 2840.000000 17.140000 2841.000000 3320.020000 ;
        RECT 2850.000000 17.140000 2851.000000 3320.020000 ;
        RECT 2860.000000 17.140000 2861.000000 3320.020000 ;
        RECT 2870.000000 17.140000 2871.000000 3320.020000 ;
        RECT 2880.000000 17.140000 2881.000000 3320.020000 ;
        RECT 2890.000000 17.140000 2891.000000 3320.020000 ;
        RECT 2900.000000 17.140000 2901.000000 3320.020000 ;
        RECT 2910.000000 17.140000 2911.000000 3320.020000 ;
        RECT 2920.000000 17.140000 2921.000000 3320.020000 ;
        RECT 2930.000000 17.140000 2931.000000 3320.020000 ;
        RECT 2940.000000 17.140000 2941.000000 3320.020000 ;
        RECT 2950.000000 17.140000 2951.000000 3320.020000 ;
        RECT 2960.000000 17.140000 2961.000000 3320.020000 ;
        RECT 2970.000000 17.140000 2971.000000 3320.020000 ;
        RECT 2980.000000 17.140000 2981.000000 3320.020000 ;
        RECT 2990.000000 17.140000 2991.000000 3320.020000 ;
        RECT 3000.000000 17.140000 3001.000000 3320.020000 ;
        RECT 3010.000000 17.140000 3011.000000 3320.020000 ;
        RECT 3020.000000 17.140000 3021.000000 3320.020000 ;
        RECT 3030.000000 17.140000 3031.000000 3320.020000 ;
        RECT 3040.000000 17.140000 3041.000000 3320.020000 ;
        RECT 3050.000000 17.140000 3051.000000 3320.020000 ;
        RECT 3060.000000 17.140000 3061.000000 3320.020000 ;
        RECT 3070.000000 17.140000 3071.000000 3320.020000 ;
        RECT 3080.000000 17.140000 3081.000000 3320.020000 ;
        RECT 3090.000000 17.140000 3091.000000 3320.020000 ;
        RECT 1790.000000 179.025000 1791.000000 3320.020000 ;
        RECT 1800.000000 179.025000 1801.000000 3320.020000 ;
        RECT 1810.000000 179.025000 1811.000000 3320.020000 ;
        RECT 1820.000000 179.025000 1821.000000 3320.020000 ;
        RECT 1830.000000 179.025000 1831.000000 3320.020000 ;
        RECT 1840.000000 179.025000 1841.000000 3320.020000 ;
        RECT 1790.000000 17.140000 1791.000000 105.375000 ;
        RECT 1800.000000 17.140000 1801.000000 105.375000 ;
        RECT 1810.000000 17.140000 1811.000000 105.375000 ;
        RECT 1820.000000 17.140000 1821.000000 105.375000 ;
        RECT 1830.000000 17.140000 1831.000000 105.375000 ;
        RECT 1840.000000 17.140000 1841.000000 105.375000 ;
        RECT 19.935000 20.130000 20.065000 20.210000 ;
        RECT 19.935000 30.340000 20.065000 30.460000 ;
        RECT 19.935000 26.920000 21.000000 27.040000 ;
        RECT 19.935000 37.180000 21.000000 37.300000 ;
        RECT 19.935000 47.440000 21.000000 47.560000 ;
        RECT 19.935000 50.860000 20.065000 50.980000 ;
        RECT 19.935000 40.600000 20.065000 40.720000 ;
        RECT 19.775000 54.280000 20.060000 54.400000 ;
        RECT 19.935000 57.700000 21.000000 57.820000 ;
        RECT 19.935000 64.540000 21.000000 64.660000 ;
        RECT 19.935000 67.960000 21.000000 68.080000 ;
        RECT 19.965000 132.940000 20.095000 133.060000 ;
        RECT 19.935000 160.300000 20.065000 160.420000 ;
        RECT 19.935000 170.560000 20.065000 170.680000 ;
        RECT 19.935000 180.820000 20.065000 180.940000 ;
        RECT 19.965000 184.240000 20.095000 184.360000 ;
        RECT 19.935000 194.500000 21.000000 194.620000 ;
        RECT 19.935000 197.920000 21.000000 198.040000 ;
        RECT 19.430000 201.340000 19.600000 201.460000 ;
        RECT 45.730000 201.340000 45.900000 201.460000 ;
        RECT 19.935000 266.320000 21.000000 266.440000 ;
        RECT 19.935000 269.740000 21.000000 269.860000 ;
        RECT 19.935000 276.580000 21.000000 276.700000 ;
        RECT 19.935000 286.840000 21.000000 286.960000 ;
        RECT 19.935000 290.260000 20.065000 290.380000 ;
        RECT 19.935000 297.100000 21.000000 297.220000 ;
        RECT 19.935000 300.520000 20.065000 300.640000 ;
        RECT 19.935000 307.360000 21.000000 307.480000 ;
        RECT 19.935000 310.780000 20.065000 310.900000 ;
        RECT 19.935000 317.620000 21.000000 317.740000 ;
        RECT 19.935000 324.460000 21.000000 324.580000 ;
        RECT 19.935000 327.880000 21.000000 328.000000 ;
        RECT 19.430000 331.300000 19.600000 331.420000 ;
        RECT 45.685000 331.300000 45.855000 331.420000 ;
        RECT 19.430000 392.860000 19.600000 392.980000 ;
        RECT 19.935000 396.280000 21.000000 396.400000 ;
        RECT 19.935000 399.700000 21.000000 399.820000 ;
        RECT 19.935000 406.540000 21.000000 406.660000 ;
        RECT 19.935000 416.800000 21.000000 416.920000 ;
        RECT 45.685000 392.860000 45.855000 392.980000 ;
        RECT 19.935000 420.220000 20.065000 420.340000 ;
        RECT 19.935000 427.060000 21.000000 427.180000 ;
        RECT 19.935000 430.480000 20.065000 430.600000 ;
        RECT 19.935000 437.320000 21.000000 437.440000 ;
        RECT 19.935000 440.740000 20.065000 440.860000 ;
        RECT 19.935000 447.580000 21.000000 447.700000 ;
        RECT 19.935000 451.000000 20.065000 451.120000 ;
        RECT 19.935000 454.420000 21.000000 454.540000 ;
        RECT 19.935000 457.840000 21.000000 457.960000 ;
        RECT 19.430000 522.820000 19.600000 522.940000 ;
        RECT 19.935000 526.240000 21.000000 526.360000 ;
        RECT 19.935000 529.660000 21.000000 529.780000 ;
        RECT 19.965000 539.920000 20.095000 540.040000 ;
        RECT 19.935000 560.440000 20.065000 560.560000 ;
        RECT 19.935000 550.180000 20.065000 550.300000 ;
        RECT 19.935000 570.700000 20.065000 570.820000 ;
        RECT 45.730000 522.820000 45.900000 522.940000 ;
        RECT 19.935000 580.960000 20.065000 581.080000 ;
        RECT 19.935000 584.390000 21.000000 584.500000 ;
        RECT 19.965000 591.220000 20.095000 591.340000 ;
        RECT 19.935000 652.780000 21.000000 652.890000 ;
        RECT 19.935000 659.620000 21.000000 659.740000 ;
        RECT 19.935000 656.200000 21.000000 656.320000 ;
        RECT 19.775000 669.880000 20.060000 670.000000 ;
        RECT 19.935000 680.140000 20.065000 680.260000 ;
        RECT 19.935000 690.400000 20.065000 690.520000 ;
        RECT 19.935000 700.660000 20.065000 700.780000 ;
        RECT 19.935000 710.920000 20.065000 711.040000 ;
        RECT 19.430000 714.340000 19.600000 714.460000 ;
        RECT 19.430000 799.840000 19.600000 799.960000 ;
        RECT 19.935000 820.360000 20.065000 820.480000 ;
        RECT 19.935000 830.620000 20.065000 830.740000 ;
        RECT 45.705000 799.840000 45.875000 799.960000 ;
        RECT 1152.100000 201.340000 1152.270000 201.460000 ;
        RECT 1152.145000 331.300000 1152.315000 331.420000 ;
        RECT 1152.145000 392.860000 1152.315000 392.980000 ;
        RECT 1152.100000 522.820000 1152.270000 522.940000 ;
        RECT 1152.020000 584.380000 1152.190000 584.500000 ;
        RECT 1152.365000 669.880000 1152.540000 670.000000 ;
        RECT 1152.100000 714.340000 1152.270000 714.460000 ;
        RECT 1152.125000 799.840000 1152.295000 799.960000 ;
        RECT 19.935000 840.880000 20.065000 841.000000 ;
        RECT 19.430000 844.300000 19.600000 844.420000 ;
        RECT 19.935000 950.320000 20.065000 950.440000 ;
        RECT 19.935000 960.580000 20.065000 960.700000 ;
        RECT 19.935000 970.840000 20.065000 970.960000 ;
        RECT 19.935000 984.520000 21.000000 984.640000 ;
        RECT 19.935000 987.940000 21.000000 988.060000 ;
        RECT 19.965000 1052.920000 20.095000 1053.040000 ;
        RECT 19.935000 1056.340000 21.000000 1056.460000 ;
        RECT 19.935000 1059.760000 21.000000 1059.880000 ;
        RECT 19.935000 1066.600000 21.000000 1066.720000 ;
        RECT 19.935000 1080.280000 20.065000 1080.400000 ;
        RECT 19.935000 1076.860000 21.000000 1076.980000 ;
        RECT 19.935000 1087.120000 21.000000 1087.240000 ;
        RECT 19.935000 1090.540000 20.065000 1090.660000 ;
        RECT 19.935000 1097.380000 21.000000 1097.500000 ;
        RECT 19.935000 1100.800000 20.065000 1100.920000 ;
        RECT 19.965000 1104.220000 20.095000 1104.340000 ;
        RECT 19.935000 1107.640000 21.000000 1107.760000 ;
        RECT 19.935000 1114.480000 21.000000 1114.600000 ;
        RECT 19.935000 1117.900000 21.000000 1118.020000 ;
        RECT 19.430000 1121.320000 19.600000 1121.440000 ;
        RECT 45.705000 1121.320000 45.875000 1121.440000 ;
        RECT 19.775000 1182.880000 20.060000 1183.000000 ;
        RECT 19.935000 1186.300000 21.000000 1186.420000 ;
        RECT 19.935000 1189.720000 21.000000 1189.840000 ;
        RECT 19.935000 1196.560000 21.000000 1196.680000 ;
        RECT 19.935000 1206.820000 21.000000 1206.940000 ;
        RECT 19.935000 1210.240000 20.065000 1210.360000 ;
        RECT 19.935000 1217.080000 21.000000 1217.200000 ;
        RECT 19.935000 1220.500000 20.065000 1220.620000 ;
        RECT 19.935000 1227.340000 21.000000 1227.460000 ;
        RECT 19.935000 1230.760000 20.065000 1230.880000 ;
        RECT 19.935000 1237.600000 21.000000 1237.720000 ;
        RECT 19.935000 1241.020000 20.065000 1241.140000 ;
        RECT 19.935000 1244.440000 21.000000 1244.560000 ;
        RECT 19.935000 1247.860000 21.000000 1247.980000 ;
        RECT 19.775000 1251.280000 20.060000 1251.400000 ;
        RECT 19.430000 1312.840000 19.600000 1312.960000 ;
        RECT 19.935000 1316.260000 21.000000 1316.380000 ;
        RECT 19.935000 1319.680000 21.000000 1319.800000 ;
        RECT 19.935000 1326.520000 21.000000 1326.640000 ;
        RECT 19.965000 1329.940000 20.095000 1330.060000 ;
        RECT 19.935000 1336.780000 21.000000 1336.900000 ;
        RECT 19.935000 1340.200000 20.065000 1340.320000 ;
        RECT 19.935000 1347.040000 21.000000 1347.160000 ;
        RECT 19.935000 1350.460000 20.065000 1350.580000 ;
        RECT 45.705000 1312.840000 45.875000 1312.960000 ;
        RECT 19.935000 1360.720000 20.065000 1360.840000 ;
        RECT 19.935000 1357.300000 21.000000 1357.420000 ;
        RECT 19.935000 1367.560000 21.000000 1367.680000 ;
        RECT 19.935000 1370.980000 20.065000 1371.100000 ;
        RECT 19.935000 1374.400000 21.000000 1374.520000 ;
        RECT 19.935000 1377.820000 21.000000 1377.940000 ;
        RECT 19.965000 1381.240000 20.095000 1381.360000 ;
        RECT 19.935000 1442.800000 21.000000 1442.890000 ;
        RECT 19.935000 1446.220000 21.000000 1446.340000 ;
        RECT 19.935000 1449.640000 21.000000 1449.760000 ;
        RECT 19.935000 1470.160000 20.065000 1470.280000 ;
        RECT 19.935000 1480.420000 20.065000 1480.540000 ;
        RECT 19.935000 1490.680000 20.065000 1490.800000 ;
        RECT 19.935000 1500.940000 20.065000 1501.060000 ;
        RECT 19.935000 1504.390000 21.000000 1504.480000 ;
        RECT 19.430000 1589.860000 19.600000 1589.980000 ;
        RECT 19.935000 1610.380000 20.065000 1610.500000 ;
        RECT 45.685000 1589.860000 45.855000 1589.980000 ;
        RECT 19.935000 1620.640000 20.065000 1620.760000 ;
        RECT 19.935000 1630.900000 20.065000 1631.020000 ;
        RECT 19.430000 1634.320000 19.600000 1634.440000 ;
        RECT 1151.250000 981.100000 1151.380000 981.220000 ;
        RECT 1152.070000 991.360000 1152.240000 991.480000 ;
        RECT 1152.125000 1121.320000 1152.295000 1121.440000 ;
        RECT 1152.365000 1182.880000 1152.540000 1183.000000 ;
        RECT 1152.365000 1251.280000 1152.540000 1251.400000 ;
        RECT 1152.125000 1312.840000 1152.295000 1312.960000 ;
        RECT 1152.145000 1589.860000 1152.315000 1589.980000 ;
        RECT 3092.400000 201.340000 3092.570000 201.460000 ;
        RECT 3092.400000 331.300000 3092.570000 331.420000 ;
        RECT 3092.400000 392.860000 3092.570000 392.980000 ;
        RECT 3092.400000 522.820000 3092.570000 522.940000 ;
        RECT 3092.400000 714.340000 3092.570000 714.460000 ;
        RECT 3092.400000 799.840000 3092.570000 799.960000 ;
        RECT 3092.400000 844.300000 3092.570000 844.420000 ;
        RECT 3092.400000 1121.320000 3092.570000 1121.440000 ;
        RECT 3092.400000 1312.840000 3092.570000 1312.960000 ;
        RECT 3092.400000 1589.860000 3092.570000 1589.980000 ;
        RECT 3092.400000 1634.320000 3092.570000 1634.440000 ;
        RECT 19.430000 1719.820000 19.600000 1719.940000 ;
        RECT 45.730000 1719.820000 45.900000 1719.940000 ;
        RECT 19.935000 1740.340000 20.065000 1740.460000 ;
        RECT 19.935000 1750.600000 20.065000 1750.720000 ;
        RECT 19.935000 1760.860000 20.065000 1760.980000 ;
        RECT 19.775000 1764.280000 20.060000 1764.400000 ;
        RECT 19.935000 1774.540000 21.000000 1774.660000 ;
        RECT 19.935000 1777.960000 21.000000 1778.080000 ;
        RECT 19.965000 1842.940000 20.095000 1843.060000 ;
        RECT 19.935000 1870.300000 20.065000 1870.420000 ;
        RECT 19.935000 1880.560000 20.065000 1880.680000 ;
        RECT 19.935000 1890.820000 20.065000 1890.940000 ;
        RECT 19.965000 1894.240000 20.095000 1894.360000 ;
        RECT 19.935000 1904.500000 21.000000 1904.620000 ;
        RECT 19.935000 1907.920000 21.000000 1908.040000 ;
        RECT 19.430000 1911.340000 19.600000 1911.460000 ;
        RECT 45.730000 1911.340000 45.900000 1911.460000 ;
        RECT 19.935000 1976.320000 21.000000 1976.440000 ;
        RECT 19.935000 1979.740000 21.000000 1979.860000 ;
        RECT 19.935000 1986.580000 21.000000 1986.700000 ;
        RECT 19.935000 1996.840000 21.000000 1996.960000 ;
        RECT 19.935000 2000.260000 20.065000 2000.380000 ;
        RECT 19.935000 2007.100000 21.000000 2007.220000 ;
        RECT 19.935000 2010.520000 20.065000 2010.640000 ;
        RECT 19.935000 2017.360000 21.000000 2017.480000 ;
        RECT 19.935000 2020.780000 20.065000 2020.900000 ;
        RECT 19.935000 2027.620000 21.000000 2027.740000 ;
        RECT 19.935000 2034.460000 21.000000 2034.580000 ;
        RECT 19.935000 2037.880000 21.000000 2038.000000 ;
        RECT 19.430000 2041.300000 19.600000 2041.420000 ;
        RECT 45.685000 2041.300000 45.855000 2041.420000 ;
        RECT 19.430000 2102.860000 19.600000 2102.980000 ;
        RECT 19.935000 2106.280000 21.000000 2106.400000 ;
        RECT 19.935000 2109.700000 21.000000 2109.820000 ;
        RECT 19.935000 2116.540000 21.000000 2116.660000 ;
        RECT 19.935000 2126.800000 21.000000 2126.920000 ;
        RECT 19.935000 2130.220000 20.065000 2130.340000 ;
        RECT 19.935000 2137.060000 21.000000 2137.180000 ;
        RECT 45.685000 2102.860000 45.855000 2102.980000 ;
        RECT 19.935000 2140.480000 20.065000 2140.600000 ;
        RECT 19.935000 2147.320000 21.000000 2147.440000 ;
        RECT 19.935000 2150.740000 20.065000 2150.860000 ;
        RECT 19.935000 2157.580000 21.000000 2157.700000 ;
        RECT 19.935000 2161.000000 20.065000 2161.120000 ;
        RECT 19.935000 2164.420000 21.000000 2164.540000 ;
        RECT 19.935000 2167.840000 21.000000 2167.960000 ;
        RECT 19.430000 2232.820000 19.600000 2232.940000 ;
        RECT 19.935000 2236.240000 21.000000 2236.360000 ;
        RECT 19.935000 2239.660000 21.000000 2239.780000 ;
        RECT 45.730000 2232.820000 45.900000 2232.940000 ;
        RECT 19.965000 2249.920000 20.095000 2250.040000 ;
        RECT 19.935000 2260.180000 20.065000 2260.300000 ;
        RECT 19.935000 2270.440000 20.065000 2270.560000 ;
        RECT 19.935000 2280.700000 20.065000 2280.820000 ;
        RECT 19.935000 2290.960000 20.065000 2291.080000 ;
        RECT 19.935000 2294.390000 21.000000 2294.500000 ;
        RECT 19.965000 2301.220000 20.095000 2301.340000 ;
        RECT 19.935000 2362.780000 21.000000 2362.890000 ;
        RECT 19.935000 2369.620000 21.000000 2369.740000 ;
        RECT 19.935000 2366.200000 21.000000 2366.320000 ;
        RECT 19.775000 2379.880000 20.060000 2380.000000 ;
        RECT 19.935000 2390.140000 20.065000 2390.260000 ;
        RECT 19.935000 2400.400000 20.065000 2400.520000 ;
        RECT 19.935000 2410.660000 20.065000 2410.780000 ;
        RECT 19.935000 2420.920000 20.065000 2421.040000 ;
        RECT 19.430000 2424.340000 19.600000 2424.460000 ;
        RECT 45.730000 2424.340000 45.900000 2424.460000 ;
        RECT 1152.100000 1719.820000 1152.270000 1719.940000 ;
        RECT 1152.365000 1764.280000 1152.540000 1764.400000 ;
        RECT 1151.250000 1860.040000 1151.380000 1860.160000 ;
        RECT 1152.100000 1911.340000 1152.270000 1911.460000 ;
        RECT 1152.145000 2041.300000 1152.315000 2041.420000 ;
        RECT 1152.145000 2102.860000 1152.315000 2102.980000 ;
        RECT 1152.100000 2232.820000 1152.270000 2232.940000 ;
        RECT 1152.365000 2379.880000 1152.540000 2380.000000 ;
        RECT 1152.100000 2424.340000 1152.270000 2424.460000 ;
        RECT 19.430000 2509.840000 19.600000 2509.960000 ;
        RECT 19.935000 2530.360000 20.065000 2530.480000 ;
        RECT 19.935000 2540.620000 20.065000 2540.740000 ;
        RECT 19.935000 2550.880000 20.065000 2551.000000 ;
        RECT 19.430000 2554.300000 19.600000 2554.420000 ;
        RECT 45.685000 2554.300000 45.855000 2554.420000 ;
        RECT 19.935000 2660.320000 20.065000 2660.440000 ;
        RECT 19.935000 2670.580000 20.065000 2670.700000 ;
        RECT 19.935000 2680.840000 20.065000 2680.960000 ;
        RECT 19.935000 2694.520000 21.000000 2694.640000 ;
        RECT 19.935000 2697.940000 21.000000 2698.060000 ;
        RECT 19.965000 2762.920000 20.095000 2763.040000 ;
        RECT 19.935000 2776.600000 21.000000 2776.720000 ;
        RECT 19.935000 2766.340000 21.000000 2766.460000 ;
        RECT 19.935000 2769.760000 21.000000 2769.880000 ;
        RECT 19.935000 2786.860000 21.000000 2786.980000 ;
        RECT 19.935000 2790.280000 20.065000 2790.400000 ;
        RECT 19.935000 2797.120000 21.000000 2797.240000 ;
        RECT 19.935000 2800.540000 20.065000 2800.660000 ;
        RECT 19.935000 2807.380000 21.000000 2807.500000 ;
        RECT 19.935000 2810.800000 20.065000 2810.920000 ;
        RECT 19.965000 2814.220000 20.095000 2814.340000 ;
        RECT 19.935000 2817.640000 21.000000 2817.760000 ;
        RECT 19.935000 2824.480000 21.000000 2824.600000 ;
        RECT 19.935000 2827.900000 21.000000 2828.020000 ;
        RECT 19.430000 2831.320000 19.600000 2831.440000 ;
        RECT 45.705000 2831.320000 45.875000 2831.440000 ;
        RECT 19.775000 2892.880000 20.060000 2893.000000 ;
        RECT 19.935000 2896.300000 21.000000 2896.420000 ;
        RECT 19.935000 2899.720000 21.000000 2899.840000 ;
        RECT 19.935000 2906.560000 21.000000 2906.680000 ;
        RECT 19.935000 2916.820000 21.000000 2916.940000 ;
        RECT 19.935000 2920.240000 20.065000 2920.360000 ;
        RECT 19.935000 2927.080000 21.000000 2927.200000 ;
        RECT 19.935000 2930.500000 20.065000 2930.620000 ;
        RECT 19.935000 2937.340000 21.000000 2937.460000 ;
        RECT 19.935000 2940.760000 20.065000 2940.880000 ;
        RECT 19.935000 2947.600000 21.000000 2947.720000 ;
        RECT 19.935000 2951.020000 20.065000 2951.140000 ;
        RECT 19.935000 2954.440000 21.000000 2954.560000 ;
        RECT 19.935000 2957.860000 21.000000 2957.980000 ;
        RECT 19.775000 2961.280000 20.060000 2961.400000 ;
        RECT 19.430000 3022.840000 19.600000 3022.960000 ;
        RECT 45.705000 3022.840000 45.875000 3022.960000 ;
        RECT 19.935000 3026.260000 21.000000 3026.380000 ;
        RECT 19.935000 3029.680000 21.000000 3029.800000 ;
        RECT 19.935000 3036.520000 21.000000 3036.640000 ;
        RECT 19.965000 3039.940000 20.095000 3040.060000 ;
        RECT 19.935000 3046.780000 21.000000 3046.900000 ;
        RECT 19.935000 3050.200000 20.065000 3050.320000 ;
        RECT 19.935000 3057.040000 21.000000 3057.160000 ;
        RECT 19.935000 3060.460000 20.065000 3060.580000 ;
        RECT 19.935000 3067.300000 21.000000 3067.420000 ;
        RECT 19.935000 3070.720000 20.065000 3070.840000 ;
        RECT 19.935000 3077.560000 21.000000 3077.680000 ;
        RECT 19.935000 3080.980000 20.065000 3081.100000 ;
        RECT 19.935000 3087.820000 21.000000 3087.940000 ;
        RECT 19.935000 3084.400000 21.000000 3084.520000 ;
        RECT 19.965000 3091.240000 20.095000 3091.360000 ;
        RECT 19.935000 3152.800000 21.000000 3152.890000 ;
        RECT 19.935000 3156.220000 21.000000 3156.340000 ;
        RECT 19.935000 3159.640000 21.000000 3159.760000 ;
        RECT 19.935000 3180.160000 20.065000 3180.280000 ;
        RECT 19.935000 3190.420000 20.065000 3190.540000 ;
        RECT 19.935000 3200.680000 20.065000 3200.800000 ;
        RECT 19.935000 3210.940000 20.065000 3211.060000 ;
        RECT 19.935000 3214.390000 21.000000 3214.480000 ;
        RECT 19.935000 3296.440000 21.000000 3296.560000 ;
        RECT 19.935000 3306.700000 21.000000 3306.820000 ;
        RECT 19.430000 3299.860000 19.600000 3299.980000 ;
        RECT 19.935000 3316.950000 21.000000 3317.030000 ;
        RECT 1152.145000 2554.300000 1152.315000 2554.420000 ;
        RECT 1152.070000 2701.360000 1152.240000 2701.480000 ;
        RECT 1152.125000 2831.320000 1152.295000 2831.440000 ;
        RECT 1152.365000 2892.880000 1152.540000 2893.000000 ;
        RECT 1152.365000 2961.280000 1152.540000 2961.400000 ;
        RECT 1152.125000 3022.840000 1152.295000 3022.960000 ;
        RECT 1152.070000 3152.800000 1152.240000 3152.920000 ;
        RECT 3092.400000 1719.820000 3092.570000 1719.940000 ;
        RECT 3092.400000 1911.340000 3092.570000 1911.460000 ;
        RECT 3092.400000 2041.300000 3092.570000 2041.420000 ;
        RECT 3092.400000 2102.860000 3092.570000 2102.980000 ;
        RECT 3092.400000 2232.820000 3092.570000 2232.940000 ;
        RECT 3092.400000 2424.340000 3092.570000 2424.460000 ;
        RECT 1821.230000 2684.260000 1821.400000 2684.380000 ;
        RECT 1821.230000 2831.320000 1821.400000 2831.440000 ;
        RECT 1821.230000 2892.880000 1821.400000 2893.000000 ;
        RECT 1821.230000 2961.280000 1821.400000 2961.400000 ;
        RECT 1821.230000 3022.840000 1821.400000 3022.960000 ;
        RECT 1821.230000 3039.940000 1821.400000 3040.060000 ;
        RECT 1821.230000 3091.240000 1821.400000 3091.360000 ;
        RECT 1821.230000 3169.900000 1821.400000 3170.020000 ;
        RECT 3092.400000 2509.840000 3092.570000 2509.960000 ;
        RECT 3092.400000 2554.300000 3092.570000 2554.420000 ;
        RECT 3092.400000 2831.320000 3092.570000 2831.440000 ;
        RECT 3092.400000 3022.840000 3092.570000 3022.960000 ;
        RECT 3092.400000 3299.860000 3092.570000 3299.980000 ;
        RECT 19.935000 1644.580000 21.000000 1644.700000 ;
        RECT 19.935000 1648.000000 21.000000 1648.120000 ;
        RECT 19.935000 1651.420000 21.000000 1651.540000 ;
        RECT 19.935000 1654.840000 21.000000 1654.960000 ;
        RECT 19.935000 1658.260000 21.000000 1658.380000 ;
        RECT 19.935000 1661.680000 21.000000 1661.800000 ;
        RECT 19.935000 1665.100000 21.000000 1665.220000 ;
        RECT 19.935000 1668.520000 21.000000 1668.640000 ;
        RECT 19.935000 1671.940000 21.000000 1672.060000 ;
        RECT 19.935000 1675.360000 21.000000 1675.480000 ;
        RECT 19.935000 1678.780000 21.000000 1678.900000 ;
        RECT 19.935000 1682.200000 21.000000 1682.320000 ;
        RECT 19.935000 1685.620000 21.000000 1685.740000 ;
        RECT 19.935000 1689.040000 21.000000 1689.160000 ;
        RECT 19.935000 1692.460000 21.000000 1692.580000 ;
        RECT 19.935000 1695.880000 21.000000 1696.000000 ;
        RECT 19.935000 1699.300000 21.000000 1699.420000 ;
        RECT 19.935000 1702.720000 21.000000 1702.840000 ;
        RECT 19.935000 1706.140000 21.000000 1706.260000 ;
        RECT 19.935000 1709.560000 21.000000 1709.680000 ;
        RECT 19.935000 796.420000 21.000000 796.540000 ;
        RECT 19.935000 806.680000 21.000000 806.800000 ;
        RECT 19.935000 816.940000 21.000000 817.060000 ;
        RECT 19.935000 827.200000 21.000000 827.320000 ;
        RECT 19.935000 837.460000 21.000000 837.580000 ;
        RECT 19.935000 847.720000 21.000000 847.840000 ;
        RECT 19.935000 204.760000 21.000000 204.880000 ;
        RECT 19.935000 208.180000 21.000000 208.300000 ;
        RECT 19.935000 211.600000 21.000000 211.720000 ;
        RECT 19.935000 215.020000 21.000000 215.140000 ;
        RECT 19.935000 218.440000 21.000000 218.560000 ;
        RECT 19.935000 221.860000 21.000000 221.980000 ;
        RECT 19.935000 225.280000 21.000000 225.400000 ;
        RECT 19.935000 228.700000 21.000000 228.820000 ;
        RECT 19.935000 232.120000 21.000000 232.240000 ;
        RECT 19.935000 235.540000 21.000000 235.660000 ;
        RECT 19.935000 238.960000 21.000000 239.080000 ;
        RECT 19.935000 242.380000 21.000000 242.500000 ;
        RECT 19.935000 245.800000 21.000000 245.920000 ;
        RECT 19.935000 249.220000 21.000000 249.340000 ;
        RECT 19.935000 252.640000 21.000000 252.760000 ;
        RECT 19.935000 256.060000 21.000000 256.180000 ;
        RECT 19.935000 259.480000 21.000000 259.600000 ;
        RECT 19.935000 74.800000 21.000000 74.920000 ;
        RECT 19.935000 78.220000 21.000000 78.340000 ;
        RECT 19.935000 81.640000 21.000000 81.760000 ;
        RECT 19.935000 85.060000 21.000000 85.180000 ;
        RECT 19.935000 88.480000 21.000000 88.600000 ;
        RECT 19.935000 91.900000 21.000000 92.020000 ;
        RECT 19.935000 95.320000 21.000000 95.440000 ;
        RECT 19.935000 98.740000 21.000000 98.860000 ;
        RECT 19.935000 102.160000 21.000000 102.280000 ;
        RECT 19.935000 105.580000 21.000000 105.700000 ;
        RECT 19.935000 109.000000 21.000000 109.120000 ;
        RECT 19.935000 112.420000 21.000000 112.540000 ;
        RECT 19.935000 115.840000 21.000000 115.960000 ;
        RECT 19.935000 119.260000 21.000000 119.380000 ;
        RECT 19.935000 122.680000 21.000000 122.800000 ;
        RECT 19.935000 126.100000 21.000000 126.220000 ;
        RECT 19.935000 129.520000 21.000000 129.640000 ;
        RECT 19.935000 136.360000 21.000000 136.480000 ;
        RECT 19.935000 146.620000 21.000000 146.740000 ;
        RECT 19.935000 156.880000 21.000000 157.000000 ;
        RECT 19.935000 167.140000 21.000000 167.260000 ;
        RECT 19.935000 177.400000 21.000000 177.520000 ;
        RECT 19.935000 187.660000 21.000000 187.780000 ;
        RECT 19.935000 334.720000 21.000000 334.840000 ;
        RECT 19.935000 338.140000 21.000000 338.260000 ;
        RECT 19.935000 341.560000 21.000000 341.680000 ;
        RECT 19.935000 344.980000 21.000000 345.100000 ;
        RECT 19.935000 348.400000 21.000000 348.520000 ;
        RECT 19.935000 351.820000 21.000000 351.940000 ;
        RECT 19.935000 355.240000 21.000000 355.360000 ;
        RECT 19.935000 358.660000 21.000000 358.780000 ;
        RECT 19.935000 362.080000 21.000000 362.200000 ;
        RECT 19.935000 365.500000 21.000000 365.620000 ;
        RECT 19.935000 368.920000 21.000000 369.040000 ;
        RECT 19.935000 372.340000 21.000000 372.460000 ;
        RECT 19.935000 375.760000 21.000000 375.880000 ;
        RECT 19.935000 379.180000 21.000000 379.300000 ;
        RECT 19.935000 382.600000 21.000000 382.720000 ;
        RECT 19.935000 386.020000 21.000000 386.140000 ;
        RECT 19.935000 389.440000 21.000000 389.560000 ;
        RECT 19.935000 594.640000 21.000000 594.760000 ;
        RECT 19.935000 598.060000 21.000000 598.180000 ;
        RECT 19.935000 601.480000 21.000000 601.600000 ;
        RECT 19.935000 604.900000 21.000000 605.020000 ;
        RECT 19.935000 608.320000 21.000000 608.440000 ;
        RECT 19.935000 611.740000 21.000000 611.860000 ;
        RECT 19.935000 615.160000 21.000000 615.280000 ;
        RECT 19.935000 618.580000 21.000000 618.700000 ;
        RECT 19.935000 622.000000 21.000000 622.120000 ;
        RECT 19.935000 625.420000 21.000000 625.540000 ;
        RECT 19.935000 628.840000 21.000000 628.960000 ;
        RECT 19.935000 632.260000 21.000000 632.380000 ;
        RECT 19.935000 635.680000 21.000000 635.800000 ;
        RECT 19.935000 639.100000 21.000000 639.220000 ;
        RECT 19.935000 642.520000 21.000000 642.640000 ;
        RECT 19.935000 645.940000 21.000000 646.060000 ;
        RECT 19.935000 649.360000 21.000000 649.480000 ;
        RECT 19.935000 536.500000 21.000000 536.620000 ;
        RECT 19.935000 546.760000 21.000000 546.880000 ;
        RECT 19.935000 557.020000 21.000000 557.140000 ;
        RECT 19.935000 567.280000 21.000000 567.400000 ;
        RECT 19.935000 577.540000 21.000000 577.660000 ;
        RECT 19.935000 587.800000 21.000000 587.920000 ;
        RECT 19.935000 464.680000 21.000000 464.800000 ;
        RECT 19.935000 468.100000 21.000000 468.220000 ;
        RECT 19.935000 471.520000 21.000000 471.640000 ;
        RECT 19.935000 474.940000 21.000000 475.060000 ;
        RECT 19.935000 478.360000 21.000000 478.480000 ;
        RECT 19.935000 481.780000 21.000000 481.900000 ;
        RECT 19.935000 485.200000 21.000000 485.320000 ;
        RECT 19.935000 488.620000 21.000000 488.740000 ;
        RECT 19.935000 492.040000 21.000000 492.160000 ;
        RECT 19.935000 495.460000 21.000000 495.580000 ;
        RECT 19.935000 498.880000 21.000000 499.000000 ;
        RECT 19.935000 502.300000 21.000000 502.420000 ;
        RECT 19.935000 505.720000 21.000000 505.840000 ;
        RECT 19.935000 509.140000 21.000000 509.260000 ;
        RECT 19.935000 512.560000 21.000000 512.680000 ;
        RECT 19.935000 515.980000 21.000000 516.100000 ;
        RECT 19.935000 519.400000 21.000000 519.520000 ;
        RECT 19.935000 666.460000 21.000000 666.580000 ;
        RECT 19.935000 676.720000 21.000000 676.840000 ;
        RECT 19.935000 686.980000 21.000000 687.100000 ;
        RECT 19.935000 697.240000 21.000000 697.360000 ;
        RECT 19.935000 707.500000 21.000000 707.620000 ;
        RECT 19.935000 717.760000 21.000000 717.880000 ;
        RECT 19.935000 724.600000 21.000000 724.720000 ;
        RECT 19.935000 728.020000 21.000000 728.140000 ;
        RECT 19.935000 731.440000 21.000000 731.560000 ;
        RECT 19.935000 734.860000 21.000000 734.980000 ;
        RECT 19.935000 738.280000 21.000000 738.400000 ;
        RECT 19.935000 741.700000 21.000000 741.820000 ;
        RECT 19.935000 745.120000 21.000000 745.240000 ;
        RECT 19.935000 748.540000 21.000000 748.660000 ;
        RECT 19.935000 751.960000 21.000000 752.080000 ;
        RECT 19.935000 755.380000 21.000000 755.500000 ;
        RECT 19.935000 758.800000 21.000000 758.920000 ;
        RECT 19.935000 762.220000 21.000000 762.340000 ;
        RECT 19.935000 765.640000 21.000000 765.760000 ;
        RECT 19.935000 769.060000 21.000000 769.180000 ;
        RECT 19.935000 772.480000 21.000000 772.600000 ;
        RECT 19.935000 775.900000 21.000000 776.020000 ;
        RECT 19.935000 779.320000 21.000000 779.440000 ;
        RECT 19.935000 782.740000 21.000000 782.860000 ;
        RECT 19.935000 786.160000 21.000000 786.280000 ;
        RECT 19.935000 789.580000 21.000000 789.700000 ;
        RECT 19.935000 994.780000 21.000000 994.900000 ;
        RECT 19.935000 998.200000 21.000000 998.320000 ;
        RECT 19.935000 1001.620000 21.000000 1001.740000 ;
        RECT 19.935000 1005.040000 21.000000 1005.160000 ;
        RECT 19.935000 1008.460000 21.000000 1008.580000 ;
        RECT 19.935000 1011.880000 21.000000 1012.000000 ;
        RECT 19.935000 1015.300000 21.000000 1015.420000 ;
        RECT 19.935000 1018.720000 21.000000 1018.840000 ;
        RECT 19.935000 1022.140000 21.000000 1022.260000 ;
        RECT 19.935000 1025.560000 21.000000 1025.680000 ;
        RECT 19.935000 1028.980000 21.000000 1029.100000 ;
        RECT 19.935000 1032.400000 21.000000 1032.520000 ;
        RECT 19.935000 1035.820000 21.000000 1035.940000 ;
        RECT 19.935000 1039.240000 21.000000 1039.360000 ;
        RECT 19.935000 1042.660000 21.000000 1042.780000 ;
        RECT 19.935000 1046.080000 21.000000 1046.200000 ;
        RECT 19.935000 1049.500000 21.000000 1049.620000 ;
        RECT 19.935000 926.380000 21.000000 926.500000 ;
        RECT 19.935000 936.640000 21.000000 936.760000 ;
        RECT 19.935000 946.900000 21.000000 947.020000 ;
        RECT 19.935000 957.160000 21.000000 957.280000 ;
        RECT 19.935000 967.420000 21.000000 967.540000 ;
        RECT 19.935000 977.680000 21.000000 977.800000 ;
        RECT 19.935000 854.560000 21.000000 854.680000 ;
        RECT 19.935000 857.980000 21.000000 858.100000 ;
        RECT 19.935000 861.400000 21.000000 861.520000 ;
        RECT 19.935000 864.820000 21.000000 864.940000 ;
        RECT 19.935000 868.240000 21.000000 868.360000 ;
        RECT 19.935000 871.660000 21.000000 871.780000 ;
        RECT 19.935000 875.080000 21.000000 875.200000 ;
        RECT 19.935000 878.500000 21.000000 878.620000 ;
        RECT 19.935000 881.920000 21.000000 882.040000 ;
        RECT 19.935000 885.340000 21.000000 885.460000 ;
        RECT 19.935000 888.760000 21.000000 888.880000 ;
        RECT 19.935000 892.180000 21.000000 892.300000 ;
        RECT 19.935000 895.600000 21.000000 895.720000 ;
        RECT 19.935000 899.020000 21.000000 899.140000 ;
        RECT 19.935000 902.440000 21.000000 902.560000 ;
        RECT 19.935000 905.860000 21.000000 905.980000 ;
        RECT 19.935000 909.280000 21.000000 909.400000 ;
        RECT 19.935000 912.700000 21.000000 912.820000 ;
        RECT 19.935000 916.120000 21.000000 916.240000 ;
        RECT 19.935000 919.540000 21.000000 919.660000 ;
        RECT 19.935000 1124.740000 21.000000 1124.860000 ;
        RECT 19.935000 1128.160000 21.000000 1128.280000 ;
        RECT 19.935000 1131.580000 21.000000 1131.700000 ;
        RECT 19.935000 1135.000000 21.000000 1135.120000 ;
        RECT 19.935000 1138.420000 21.000000 1138.540000 ;
        RECT 19.935000 1141.840000 21.000000 1141.960000 ;
        RECT 19.935000 1145.260000 21.000000 1145.380000 ;
        RECT 19.935000 1148.680000 21.000000 1148.800000 ;
        RECT 19.935000 1152.100000 21.000000 1152.220000 ;
        RECT 19.935000 1155.520000 21.000000 1155.640000 ;
        RECT 19.935000 1158.940000 21.000000 1159.060000 ;
        RECT 19.935000 1162.360000 21.000000 1162.480000 ;
        RECT 19.935000 1165.780000 21.000000 1165.900000 ;
        RECT 19.935000 1169.200000 21.000000 1169.320000 ;
        RECT 19.935000 1172.620000 21.000000 1172.740000 ;
        RECT 19.935000 1176.040000 21.000000 1176.160000 ;
        RECT 19.935000 1179.460000 21.000000 1179.580000 ;
        RECT 19.935000 1456.480000 21.000000 1456.600000 ;
        RECT 19.935000 1466.740000 21.000000 1466.860000 ;
        RECT 19.935000 1477.000000 21.000000 1477.120000 ;
        RECT 19.935000 1487.260000 21.000000 1487.380000 ;
        RECT 19.935000 1497.520000 21.000000 1497.640000 ;
        RECT 19.935000 1507.780000 21.000000 1507.900000 ;
        RECT 19.935000 1254.700000 21.000000 1254.820000 ;
        RECT 19.935000 1258.120000 21.000000 1258.240000 ;
        RECT 19.935000 1261.540000 21.000000 1261.660000 ;
        RECT 19.935000 1264.960000 21.000000 1265.080000 ;
        RECT 19.935000 1268.380000 21.000000 1268.500000 ;
        RECT 19.935000 1271.800000 21.000000 1271.920000 ;
        RECT 19.935000 1275.220000 21.000000 1275.340000 ;
        RECT 19.935000 1278.640000 21.000000 1278.760000 ;
        RECT 19.935000 1282.060000 21.000000 1282.180000 ;
        RECT 19.935000 1285.480000 21.000000 1285.600000 ;
        RECT 19.935000 1288.900000 21.000000 1289.020000 ;
        RECT 19.935000 1292.320000 21.000000 1292.440000 ;
        RECT 19.935000 1295.740000 21.000000 1295.860000 ;
        RECT 19.935000 1299.160000 21.000000 1299.280000 ;
        RECT 19.935000 1302.580000 21.000000 1302.700000 ;
        RECT 19.935000 1306.000000 21.000000 1306.120000 ;
        RECT 19.935000 1309.420000 21.000000 1309.540000 ;
        RECT 19.935000 1384.660000 21.000000 1384.780000 ;
        RECT 19.935000 1388.080000 21.000000 1388.200000 ;
        RECT 19.935000 1391.500000 21.000000 1391.620000 ;
        RECT 19.935000 1394.920000 21.000000 1395.040000 ;
        RECT 19.935000 1398.340000 21.000000 1398.460000 ;
        RECT 19.935000 1401.760000 21.000000 1401.880000 ;
        RECT 19.935000 1405.180000 21.000000 1405.300000 ;
        RECT 19.935000 1408.600000 21.000000 1408.720000 ;
        RECT 19.935000 1412.020000 21.000000 1412.140000 ;
        RECT 19.935000 1415.440000 21.000000 1415.560000 ;
        RECT 19.935000 1418.860000 21.000000 1418.980000 ;
        RECT 19.935000 1422.280000 21.000000 1422.400000 ;
        RECT 19.935000 1425.700000 21.000000 1425.820000 ;
        RECT 19.935000 1429.120000 21.000000 1429.240000 ;
        RECT 19.935000 1432.540000 21.000000 1432.660000 ;
        RECT 19.935000 1435.960000 21.000000 1436.080000 ;
        RECT 19.935000 1439.380000 21.000000 1439.500000 ;
        RECT 19.935000 1514.620000 21.000000 1514.740000 ;
        RECT 19.935000 1518.040000 21.000000 1518.160000 ;
        RECT 19.935000 1521.460000 21.000000 1521.580000 ;
        RECT 19.935000 1524.880000 21.000000 1525.000000 ;
        RECT 19.935000 1528.300000 21.000000 1528.420000 ;
        RECT 19.935000 1531.720000 21.000000 1531.840000 ;
        RECT 19.935000 1535.140000 21.000000 1535.260000 ;
        RECT 19.935000 1538.560000 21.000000 1538.680000 ;
        RECT 19.935000 1541.980000 21.000000 1542.100000 ;
        RECT 19.935000 1545.400000 21.000000 1545.520000 ;
        RECT 19.935000 1548.820000 21.000000 1548.940000 ;
        RECT 19.935000 1552.240000 21.000000 1552.360000 ;
        RECT 19.935000 1555.660000 21.000000 1555.780000 ;
        RECT 19.935000 1559.080000 21.000000 1559.200000 ;
        RECT 19.935000 1562.500000 21.000000 1562.620000 ;
        RECT 19.935000 1565.920000 21.000000 1566.040000 ;
        RECT 19.935000 1569.340000 21.000000 1569.460000 ;
        RECT 19.935000 1572.760000 21.000000 1572.880000 ;
        RECT 19.935000 1576.180000 21.000000 1576.300000 ;
        RECT 19.935000 1579.600000 21.000000 1579.720000 ;
        RECT 19.935000 1586.440000 21.000000 1586.560000 ;
        RECT 19.935000 1596.700000 21.000000 1596.820000 ;
        RECT 19.935000 1606.960000 21.000000 1607.080000 ;
        RECT 19.935000 1617.220000 21.000000 1617.340000 ;
        RECT 19.935000 1627.480000 21.000000 1627.600000 ;
        RECT 19.935000 1637.740000 21.000000 1637.860000 ;
        RECT 19.935000 2044.720000 21.000000 2044.840000 ;
        RECT 19.935000 2048.140000 21.000000 2048.260000 ;
        RECT 19.935000 2051.560000 21.000000 2051.680000 ;
        RECT 19.935000 2054.980000 21.000000 2055.100000 ;
        RECT 19.935000 2058.400000 21.000000 2058.520000 ;
        RECT 19.935000 2061.820000 21.000000 2061.940000 ;
        RECT 19.935000 2065.240000 21.000000 2065.360000 ;
        RECT 19.935000 2068.660000 21.000000 2068.780000 ;
        RECT 19.935000 2072.080000 21.000000 2072.200000 ;
        RECT 19.935000 2075.500000 21.000000 2075.620000 ;
        RECT 19.935000 2078.920000 21.000000 2079.040000 ;
        RECT 19.935000 2082.340000 21.000000 2082.460000 ;
        RECT 19.935000 2085.760000 21.000000 2085.880000 ;
        RECT 19.935000 2089.180000 21.000000 2089.300000 ;
        RECT 19.935000 2092.600000 21.000000 2092.720000 ;
        RECT 19.935000 2096.020000 21.000000 2096.140000 ;
        RECT 19.935000 2099.440000 21.000000 2099.560000 ;
        RECT 19.935000 1846.360000 21.000000 1846.480000 ;
        RECT 19.935000 1856.620000 21.000000 1856.740000 ;
        RECT 19.935000 1866.880000 21.000000 1867.000000 ;
        RECT 19.935000 1877.140000 21.000000 1877.260000 ;
        RECT 19.935000 1887.400000 21.000000 1887.520000 ;
        RECT 19.935000 1897.660000 21.000000 1897.780000 ;
        RECT 19.935000 1716.400000 21.000000 1716.520000 ;
        RECT 19.935000 1726.660000 21.000000 1726.780000 ;
        RECT 19.935000 1736.920000 21.000000 1737.040000 ;
        RECT 19.935000 1747.180000 21.000000 1747.300000 ;
        RECT 19.935000 1757.440000 21.000000 1757.560000 ;
        RECT 19.935000 1767.700000 21.000000 1767.820000 ;
        RECT 19.935000 1784.800000 21.000000 1784.920000 ;
        RECT 19.935000 1788.220000 21.000000 1788.340000 ;
        RECT 19.935000 1791.640000 21.000000 1791.760000 ;
        RECT 19.935000 1795.060000 21.000000 1795.180000 ;
        RECT 19.935000 1798.480000 21.000000 1798.600000 ;
        RECT 19.935000 1801.900000 21.000000 1802.020000 ;
        RECT 19.935000 1805.320000 21.000000 1805.440000 ;
        RECT 19.935000 1808.740000 21.000000 1808.860000 ;
        RECT 19.935000 1812.160000 21.000000 1812.280000 ;
        RECT 19.935000 1815.580000 21.000000 1815.700000 ;
        RECT 19.935000 1819.000000 21.000000 1819.120000 ;
        RECT 19.935000 1822.420000 21.000000 1822.540000 ;
        RECT 19.935000 1825.840000 21.000000 1825.960000 ;
        RECT 19.935000 1829.260000 21.000000 1829.380000 ;
        RECT 19.935000 1832.680000 21.000000 1832.800000 ;
        RECT 19.935000 1836.100000 21.000000 1836.220000 ;
        RECT 19.935000 1839.520000 21.000000 1839.640000 ;
        RECT 19.935000 1914.760000 21.000000 1914.880000 ;
        RECT 19.935000 1918.180000 21.000000 1918.300000 ;
        RECT 19.935000 1921.600000 21.000000 1921.720000 ;
        RECT 19.935000 1925.020000 21.000000 1925.140000 ;
        RECT 19.935000 1928.440000 21.000000 1928.560000 ;
        RECT 19.935000 1931.860000 21.000000 1931.980000 ;
        RECT 19.935000 1935.280000 21.000000 1935.400000 ;
        RECT 19.935000 1938.700000 21.000000 1938.820000 ;
        RECT 19.935000 1942.120000 21.000000 1942.240000 ;
        RECT 19.935000 1945.540000 21.000000 1945.660000 ;
        RECT 19.935000 1948.960000 21.000000 1949.080000 ;
        RECT 19.935000 1952.380000 21.000000 1952.500000 ;
        RECT 19.935000 1955.800000 21.000000 1955.920000 ;
        RECT 19.935000 1959.220000 21.000000 1959.340000 ;
        RECT 19.935000 1962.640000 21.000000 1962.760000 ;
        RECT 19.935000 1966.060000 21.000000 1966.180000 ;
        RECT 19.935000 1969.480000 21.000000 1969.600000 ;
        RECT 19.935000 2246.500000 21.000000 2246.620000 ;
        RECT 19.935000 2256.760000 21.000000 2256.880000 ;
        RECT 19.935000 2267.020000 21.000000 2267.140000 ;
        RECT 19.935000 2277.280000 21.000000 2277.400000 ;
        RECT 19.935000 2287.540000 21.000000 2287.660000 ;
        RECT 19.935000 2297.800000 21.000000 2297.920000 ;
        RECT 19.935000 2174.680000 21.000000 2174.800000 ;
        RECT 19.935000 2178.100000 21.000000 2178.220000 ;
        RECT 19.935000 2181.520000 21.000000 2181.640000 ;
        RECT 19.935000 2184.940000 21.000000 2185.060000 ;
        RECT 19.935000 2188.360000 21.000000 2188.480000 ;
        RECT 19.935000 2191.780000 21.000000 2191.900000 ;
        RECT 19.935000 2195.200000 21.000000 2195.320000 ;
        RECT 19.935000 2198.620000 21.000000 2198.740000 ;
        RECT 19.935000 2202.040000 21.000000 2202.160000 ;
        RECT 19.935000 2205.460000 21.000000 2205.580000 ;
        RECT 19.935000 2208.880000 21.000000 2209.000000 ;
        RECT 19.935000 2212.300000 21.000000 2212.420000 ;
        RECT 19.935000 2215.720000 21.000000 2215.840000 ;
        RECT 19.935000 2219.140000 21.000000 2219.260000 ;
        RECT 19.935000 2222.560000 21.000000 2222.680000 ;
        RECT 19.935000 2225.980000 21.000000 2226.100000 ;
        RECT 19.935000 2229.400000 21.000000 2229.520000 ;
        RECT 19.935000 2376.460000 21.000000 2376.580000 ;
        RECT 19.935000 2386.720000 21.000000 2386.840000 ;
        RECT 19.935000 2396.980000 21.000000 2397.100000 ;
        RECT 19.935000 2407.240000 21.000000 2407.360000 ;
        RECT 19.935000 2417.500000 21.000000 2417.620000 ;
        RECT 19.935000 2427.760000 21.000000 2427.880000 ;
        RECT 19.935000 2304.640000 21.000000 2304.760000 ;
        RECT 19.935000 2308.060000 21.000000 2308.180000 ;
        RECT 19.935000 2311.480000 21.000000 2311.600000 ;
        RECT 19.935000 2314.900000 21.000000 2315.020000 ;
        RECT 19.935000 2318.320000 21.000000 2318.440000 ;
        RECT 19.935000 2321.740000 21.000000 2321.860000 ;
        RECT 19.935000 2325.160000 21.000000 2325.280000 ;
        RECT 19.935000 2328.580000 21.000000 2328.700000 ;
        RECT 19.935000 2332.000000 21.000000 2332.120000 ;
        RECT 19.935000 2335.420000 21.000000 2335.540000 ;
        RECT 19.935000 2338.840000 21.000000 2338.960000 ;
        RECT 19.935000 2342.260000 21.000000 2342.380000 ;
        RECT 19.935000 2345.680000 21.000000 2345.800000 ;
        RECT 19.935000 2349.100000 21.000000 2349.220000 ;
        RECT 19.935000 2352.520000 21.000000 2352.640000 ;
        RECT 19.935000 2355.940000 21.000000 2356.060000 ;
        RECT 19.935000 2359.360000 21.000000 2359.480000 ;
        RECT 19.935000 2434.600000 21.000000 2434.720000 ;
        RECT 19.935000 2438.020000 21.000000 2438.140000 ;
        RECT 19.935000 2441.440000 21.000000 2441.560000 ;
        RECT 19.935000 2444.860000 21.000000 2444.980000 ;
        RECT 19.935000 2448.280000 21.000000 2448.400000 ;
        RECT 19.935000 2451.700000 21.000000 2451.820000 ;
        RECT 19.935000 2455.120000 21.000000 2455.240000 ;
        RECT 19.935000 2458.540000 21.000000 2458.660000 ;
        RECT 19.935000 2461.960000 21.000000 2462.080000 ;
        RECT 19.935000 2465.380000 21.000000 2465.500000 ;
        RECT 19.935000 2468.800000 21.000000 2468.920000 ;
        RECT 19.935000 2472.220000 21.000000 2472.340000 ;
        RECT 19.935000 2475.640000 21.000000 2475.760000 ;
        RECT 19.935000 2479.060000 21.000000 2479.180000 ;
        RECT 19.935000 2482.480000 21.000000 2482.600000 ;
        RECT 19.935000 2485.900000 21.000000 2486.020000 ;
        RECT 19.935000 2489.320000 21.000000 2489.440000 ;
        RECT 19.935000 2492.740000 21.000000 2492.860000 ;
        RECT 19.935000 2496.160000 21.000000 2496.280000 ;
        RECT 19.935000 2499.580000 21.000000 2499.700000 ;
        RECT 19.935000 2704.780000 21.000000 2704.900000 ;
        RECT 19.935000 2708.200000 21.000000 2708.320000 ;
        RECT 19.935000 2711.620000 21.000000 2711.740000 ;
        RECT 19.935000 2715.040000 21.000000 2715.160000 ;
        RECT 19.935000 2718.460000 21.000000 2718.580000 ;
        RECT 19.935000 2721.880000 21.000000 2722.000000 ;
        RECT 19.935000 2725.300000 21.000000 2725.420000 ;
        RECT 19.935000 2728.720000 21.000000 2728.840000 ;
        RECT 19.935000 2732.140000 21.000000 2732.260000 ;
        RECT 19.935000 2735.560000 21.000000 2735.680000 ;
        RECT 19.935000 2738.980000 21.000000 2739.100000 ;
        RECT 19.935000 2742.400000 21.000000 2742.520000 ;
        RECT 19.935000 2745.820000 21.000000 2745.940000 ;
        RECT 19.935000 2749.240000 21.000000 2749.360000 ;
        RECT 19.935000 2752.660000 21.000000 2752.780000 ;
        RECT 19.935000 2756.080000 21.000000 2756.200000 ;
        RECT 19.935000 2759.500000 21.000000 2759.620000 ;
        RECT 19.935000 2564.560000 21.000000 2564.680000 ;
        RECT 19.935000 2567.980000 21.000000 2568.100000 ;
        RECT 19.935000 2571.400000 21.000000 2571.520000 ;
        RECT 19.935000 2574.820000 21.000000 2574.940000 ;
        RECT 19.935000 2578.240000 21.000000 2578.360000 ;
        RECT 19.935000 2581.660000 21.000000 2581.780000 ;
        RECT 19.935000 2585.080000 21.000000 2585.200000 ;
        RECT 19.935000 2588.500000 21.000000 2588.620000 ;
        RECT 19.935000 2591.920000 21.000000 2592.040000 ;
        RECT 19.935000 2595.340000 21.000000 2595.460000 ;
        RECT 19.935000 2598.760000 21.000000 2598.880000 ;
        RECT 19.935000 2602.180000 21.000000 2602.300000 ;
        RECT 19.935000 2605.600000 21.000000 2605.720000 ;
        RECT 19.935000 2609.020000 21.000000 2609.140000 ;
        RECT 19.935000 2612.440000 21.000000 2612.560000 ;
        RECT 19.935000 2615.860000 21.000000 2615.980000 ;
        RECT 19.935000 2619.280000 21.000000 2619.400000 ;
        RECT 19.935000 2622.700000 21.000000 2622.820000 ;
        RECT 19.935000 2626.120000 21.000000 2626.240000 ;
        RECT 19.935000 2629.540000 21.000000 2629.660000 ;
        RECT 19.935000 2506.420000 21.000000 2506.540000 ;
        RECT 19.935000 2516.680000 21.000000 2516.800000 ;
        RECT 19.935000 2526.940000 21.000000 2527.060000 ;
        RECT 19.935000 2537.200000 21.000000 2537.320000 ;
        RECT 19.935000 2547.460000 21.000000 2547.580000 ;
        RECT 19.935000 2557.720000 21.000000 2557.840000 ;
        RECT 19.935000 2636.380000 21.000000 2636.500000 ;
        RECT 19.935000 2646.640000 21.000000 2646.760000 ;
        RECT 19.935000 2656.900000 21.000000 2657.020000 ;
        RECT 19.935000 2667.160000 21.000000 2667.280000 ;
        RECT 19.935000 2677.420000 21.000000 2677.540000 ;
        RECT 19.935000 2687.680000 21.000000 2687.800000 ;
        RECT 19.935000 2834.740000 21.000000 2834.860000 ;
        RECT 19.935000 2838.160000 21.000000 2838.280000 ;
        RECT 19.935000 2841.580000 21.000000 2841.700000 ;
        RECT 19.935000 2845.000000 21.000000 2845.120000 ;
        RECT 19.935000 2848.420000 21.000000 2848.540000 ;
        RECT 19.935000 2851.840000 21.000000 2851.960000 ;
        RECT 19.935000 2855.260000 21.000000 2855.380000 ;
        RECT 19.935000 2858.680000 21.000000 2858.800000 ;
        RECT 19.935000 2862.100000 21.000000 2862.220000 ;
        RECT 19.935000 2865.520000 21.000000 2865.640000 ;
        RECT 19.935000 2868.940000 21.000000 2869.060000 ;
        RECT 19.935000 2872.360000 21.000000 2872.480000 ;
        RECT 19.935000 2875.780000 21.000000 2875.900000 ;
        RECT 19.935000 2879.200000 21.000000 2879.320000 ;
        RECT 19.935000 2882.620000 21.000000 2882.740000 ;
        RECT 19.935000 2886.040000 21.000000 2886.160000 ;
        RECT 19.935000 2889.460000 21.000000 2889.580000 ;
        RECT 19.935000 3094.660000 21.000000 3094.780000 ;
        RECT 19.935000 3098.080000 21.000000 3098.200000 ;
        RECT 19.935000 3101.500000 21.000000 3101.620000 ;
        RECT 19.935000 3104.920000 21.000000 3105.040000 ;
        RECT 19.935000 3108.340000 21.000000 3108.460000 ;
        RECT 19.935000 3111.760000 21.000000 3111.880000 ;
        RECT 19.935000 3115.180000 21.000000 3115.300000 ;
        RECT 19.935000 3118.600000 21.000000 3118.720000 ;
        RECT 19.935000 3122.020000 21.000000 3122.140000 ;
        RECT 19.935000 3125.440000 21.000000 3125.560000 ;
        RECT 19.935000 3128.860000 21.000000 3128.980000 ;
        RECT 19.935000 3132.280000 21.000000 3132.400000 ;
        RECT 19.935000 3135.700000 21.000000 3135.820000 ;
        RECT 19.935000 3139.120000 21.000000 3139.240000 ;
        RECT 19.935000 3142.540000 21.000000 3142.660000 ;
        RECT 19.935000 3145.960000 21.000000 3146.080000 ;
        RECT 19.935000 3149.380000 21.000000 3149.500000 ;
        RECT 19.935000 2964.700000 21.000000 2964.820000 ;
        RECT 19.935000 2968.120000 21.000000 2968.240000 ;
        RECT 19.935000 2971.540000 21.000000 2971.660000 ;
        RECT 19.935000 2974.960000 21.000000 2975.080000 ;
        RECT 19.935000 2978.380000 21.000000 2978.500000 ;
        RECT 19.935000 2981.800000 21.000000 2981.920000 ;
        RECT 19.935000 2985.220000 21.000000 2985.340000 ;
        RECT 19.935000 2988.640000 21.000000 2988.760000 ;
        RECT 19.935000 2992.060000 21.000000 2992.180000 ;
        RECT 19.935000 2995.480000 21.000000 2995.600000 ;
        RECT 19.935000 2998.900000 21.000000 2999.020000 ;
        RECT 19.935000 3002.320000 21.000000 3002.440000 ;
        RECT 19.935000 3005.740000 21.000000 3005.860000 ;
        RECT 19.935000 3009.160000 21.000000 3009.280000 ;
        RECT 19.935000 3012.580000 21.000000 3012.700000 ;
        RECT 19.935000 3016.000000 21.000000 3016.120000 ;
        RECT 19.935000 3019.420000 21.000000 3019.540000 ;
        RECT 19.935000 3166.480000 21.000000 3166.600000 ;
        RECT 19.935000 3176.740000 21.000000 3176.860000 ;
        RECT 19.935000 3187.000000 21.000000 3187.120000 ;
        RECT 19.935000 3197.260000 21.000000 3197.380000 ;
        RECT 19.935000 3207.520000 21.000000 3207.640000 ;
        RECT 19.935000 3217.780000 21.000000 3217.900000 ;
        RECT 19.935000 3224.620000 21.000000 3224.740000 ;
        RECT 19.935000 3228.040000 21.000000 3228.160000 ;
        RECT 19.935000 3231.460000 21.000000 3231.580000 ;
        RECT 19.935000 3234.880000 21.000000 3235.000000 ;
        RECT 19.935000 3238.300000 21.000000 3238.420000 ;
        RECT 19.935000 3241.720000 21.000000 3241.840000 ;
        RECT 19.935000 3245.140000 21.000000 3245.260000 ;
        RECT 19.935000 3248.560000 21.000000 3248.680000 ;
        RECT 19.935000 3251.980000 21.000000 3252.100000 ;
        RECT 19.935000 3255.400000 21.000000 3255.520000 ;
        RECT 19.935000 3258.820000 21.000000 3258.940000 ;
        RECT 19.935000 3262.240000 21.000000 3262.360000 ;
        RECT 19.935000 3265.660000 21.000000 3265.780000 ;
        RECT 19.935000 3269.080000 21.000000 3269.200000 ;
        RECT 19.935000 3272.500000 21.000000 3272.620000 ;
        RECT 19.935000 3275.920000 21.000000 3276.040000 ;
        RECT 19.935000 3279.340000 21.000000 3279.460000 ;
        RECT 19.935000 3282.760000 21.000000 3282.880000 ;
        RECT 19.935000 3286.180000 21.000000 3286.300000 ;
        RECT 19.935000 3289.600000 21.000000 3289.720000 ;
    END
# end of P/G power stripe data as pin

  END vdd
  PIN vss
    DIRECTION INPUT ;
    USE GROUND ;

# P/G power stripe data as pin
    PORT
      LAYER Metal9 ;
        RECT 23.000000 13.140000 24.000000 3324.020000 ;
        RECT 1773.000000 179.025000 1774.000000 3324.020000 ;
        RECT 1303.000000 13.140000 1304.000000 2644.335000 ;
        RECT 1293.000000 13.140000 1294.000000 2644.335000 ;
        RECT 1283.000000 13.140000 1284.000000 2644.335000 ;
        RECT 1273.000000 13.140000 1274.000000 2644.335000 ;
        RECT 1263.000000 13.140000 1264.000000 2644.335000 ;
        RECT 1253.000000 13.140000 1254.000000 2644.335000 ;
        RECT 3097.000000 13.140000 3099.000000 3324.020000 ;
        RECT 13.000000 13.140000 15.000000 3324.020000 ;
        RECT 1143.000000 1034.110000 1144.375000 1034.230000 ;
        RECT 1143.000000 1123.030000 1144.375000 1123.150000 ;
        RECT 1773.000000 13.140000 1774.000000 105.375000 ;
        RECT 1943.000000 131.230000 1945.385000 131.350000 ;
        RECT 1771.860000 209.890000 1774.000000 210.010000 ;
        RECT 1943.000000 209.890000 1945.340000 210.010000 ;
        RECT 3053.000000 1034.110000 3054.375000 1034.230000 ;
        RECT 3053.000000 1123.030000 3054.375000 1123.150000 ;
        RECT 1143.000000 1913.050000 1144.375000 1913.170000 ;
        RECT 1303.000000 2700.885000 1304.000000 3324.020000 ;
        RECT 1293.000000 2700.885000 1294.000000 3324.020000 ;
        RECT 1283.000000 2700.885000 1284.000000 3324.020000 ;
        RECT 1273.000000 2700.885000 1274.000000 3324.020000 ;
        RECT 1263.000000 2700.885000 1264.000000 3324.020000 ;
        RECT 1253.000000 2700.885000 1254.000000 3324.020000 ;
        RECT 1252.685000 2709.910000 1254.000000 2710.030000 ;
        RECT 1143.000000 2744.110000 1144.375000 2744.230000 ;
        RECT 1252.685000 2761.210000 1254.000000 2761.330000 ;
        RECT 1143.000000 2833.030000 1144.375000 2833.150000 ;
        RECT 1252.685000 2839.870000 1254.000000 2839.990000 ;
        RECT 1252.685000 2884.330000 1254.000000 2884.450000 ;
        RECT 1252.685000 2969.830000 1254.000000 2969.950000 ;
        RECT 1252.685000 3014.290000 1254.000000 3014.410000 ;
        RECT 1252.685000 3092.950000 1254.000000 3093.070000 ;
        RECT 1252.685000 3144.250000 1254.000000 3144.370000 ;
        RECT 3053.000000 1913.050000 3054.375000 1913.170000 ;
        RECT 3053.000000 2744.110000 3054.375000 2744.230000 ;
        RECT 3053.000000 2833.030000 3054.375000 2833.150000 ;
        RECT 1313.000000 13.140000 1314.000000 3324.020000 ;
        RECT 1323.000000 13.140000 1324.000000 3324.020000 ;
        RECT 1333.000000 13.140000 1334.000000 3324.020000 ;
        RECT 1343.000000 13.140000 1344.000000 3324.020000 ;
        RECT 1353.000000 13.140000 1354.000000 3324.020000 ;
        RECT 1363.000000 13.140000 1364.000000 3324.020000 ;
        RECT 1373.000000 13.140000 1374.000000 3324.020000 ;
        RECT 1383.000000 13.140000 1384.000000 3324.020000 ;
        RECT 1393.000000 13.140000 1394.000000 3324.020000 ;
        RECT 1403.000000 13.140000 1404.000000 3324.020000 ;
        RECT 1413.000000 13.140000 1414.000000 3324.020000 ;
        RECT 1423.000000 13.140000 1424.000000 3324.020000 ;
        RECT 1433.000000 13.140000 1434.000000 3324.020000 ;
        RECT 1443.000000 13.140000 1444.000000 3324.020000 ;
        RECT 1453.000000 13.140000 1454.000000 3324.020000 ;
        RECT 1463.000000 13.140000 1464.000000 3324.020000 ;
        RECT 1473.000000 13.140000 1474.000000 3324.020000 ;
        RECT 1483.000000 13.140000 1484.000000 3324.020000 ;
        RECT 1493.000000 13.140000 1494.000000 3324.020000 ;
        RECT 1503.000000 13.140000 1504.000000 3324.020000 ;
        RECT 1513.000000 13.140000 1514.000000 3324.020000 ;
        RECT 1523.000000 13.140000 1524.000000 3324.020000 ;
        RECT 1533.000000 13.140000 1534.000000 3324.020000 ;
        RECT 1543.000000 13.140000 1544.000000 3324.020000 ;
        RECT 1553.000000 13.140000 1554.000000 3324.020000 ;
        RECT 1563.000000 13.140000 1564.000000 3324.020000 ;
        RECT 1573.000000 13.140000 1574.000000 3324.020000 ;
        RECT 1583.000000 13.140000 1584.000000 3324.020000 ;
        RECT 1593.000000 13.140000 1594.000000 3324.020000 ;
        RECT 1603.000000 13.140000 1604.000000 3324.020000 ;
        RECT 1613.000000 13.140000 1614.000000 3324.020000 ;
        RECT 1623.000000 13.140000 1624.000000 3324.020000 ;
        RECT 1633.000000 13.140000 1634.000000 3324.020000 ;
        RECT 1643.000000 13.140000 1644.000000 3324.020000 ;
        RECT 1653.000000 13.140000 1654.000000 3324.020000 ;
        RECT 1663.000000 13.140000 1664.000000 3324.020000 ;
        RECT 1673.000000 13.140000 1674.000000 3324.020000 ;
        RECT 1683.000000 13.140000 1684.000000 3324.020000 ;
        RECT 1693.000000 13.140000 1694.000000 3324.020000 ;
        RECT 1703.000000 13.140000 1704.000000 3324.020000 ;
        RECT 1713.000000 13.140000 1714.000000 3324.020000 ;
        RECT 1723.000000 13.140000 1724.000000 3324.020000 ;
        RECT 1733.000000 13.140000 1734.000000 3324.020000 ;
        RECT 1743.000000 13.140000 1744.000000 3324.020000 ;
        RECT 1753.000000 13.140000 1754.000000 3324.020000 ;
        RECT 1763.000000 13.140000 1764.000000 3324.020000 ;
        RECT 33.000000 13.140000 34.000000 3324.020000 ;
        RECT 43.000000 13.140000 44.000000 3324.020000 ;
        RECT 53.000000 13.140000 54.000000 3324.020000 ;
        RECT 63.000000 13.140000 64.000000 3324.020000 ;
        RECT 73.000000 13.140000 74.000000 3324.020000 ;
        RECT 83.000000 13.140000 84.000000 3324.020000 ;
        RECT 93.000000 13.140000 94.000000 3324.020000 ;
        RECT 103.000000 13.140000 104.000000 3324.020000 ;
        RECT 113.000000 13.140000 114.000000 3324.020000 ;
        RECT 123.000000 13.140000 124.000000 3324.020000 ;
        RECT 133.000000 13.140000 134.000000 3324.020000 ;
        RECT 143.000000 13.140000 144.000000 3324.020000 ;
        RECT 153.000000 13.140000 154.000000 3324.020000 ;
        RECT 163.000000 13.140000 164.000000 3324.020000 ;
        RECT 173.000000 13.140000 174.000000 3324.020000 ;
        RECT 183.000000 13.140000 184.000000 3324.020000 ;
        RECT 193.000000 13.140000 194.000000 3324.020000 ;
        RECT 203.000000 13.140000 204.000000 3324.020000 ;
        RECT 213.000000 13.140000 214.000000 3324.020000 ;
        RECT 223.000000 13.140000 224.000000 3324.020000 ;
        RECT 233.000000 13.140000 234.000000 3324.020000 ;
        RECT 243.000000 13.140000 244.000000 3324.020000 ;
        RECT 253.000000 13.140000 254.000000 3324.020000 ;
        RECT 263.000000 13.140000 264.000000 3324.020000 ;
        RECT 273.000000 13.140000 274.000000 3324.020000 ;
        RECT 283.000000 13.140000 284.000000 3324.020000 ;
        RECT 293.000000 13.140000 294.000000 3324.020000 ;
        RECT 303.000000 13.140000 304.000000 3324.020000 ;
        RECT 313.000000 13.140000 314.000000 3324.020000 ;
        RECT 323.000000 13.140000 324.000000 3324.020000 ;
        RECT 333.000000 13.140000 334.000000 3324.020000 ;
        RECT 343.000000 13.140000 344.000000 3324.020000 ;
        RECT 353.000000 13.140000 354.000000 3324.020000 ;
        RECT 363.000000 13.140000 364.000000 3324.020000 ;
        RECT 373.000000 13.140000 374.000000 3324.020000 ;
        RECT 383.000000 13.140000 384.000000 3324.020000 ;
        RECT 393.000000 13.140000 394.000000 3324.020000 ;
        RECT 403.000000 13.140000 404.000000 3324.020000 ;
        RECT 413.000000 13.140000 414.000000 3324.020000 ;
        RECT 423.000000 13.140000 424.000000 3324.020000 ;
        RECT 433.000000 13.140000 434.000000 3324.020000 ;
        RECT 443.000000 13.140000 444.000000 3324.020000 ;
        RECT 453.000000 13.140000 454.000000 3324.020000 ;
        RECT 463.000000 13.140000 464.000000 3324.020000 ;
        RECT 473.000000 13.140000 474.000000 3324.020000 ;
        RECT 483.000000 13.140000 484.000000 3324.020000 ;
        RECT 493.000000 13.140000 494.000000 3324.020000 ;
        RECT 503.000000 13.140000 504.000000 3324.020000 ;
        RECT 513.000000 13.140000 514.000000 3324.020000 ;
        RECT 523.000000 13.140000 524.000000 3324.020000 ;
        RECT 533.000000 13.140000 534.000000 3324.020000 ;
        RECT 543.000000 13.140000 544.000000 3324.020000 ;
        RECT 553.000000 13.140000 554.000000 3324.020000 ;
        RECT 563.000000 13.140000 564.000000 3324.020000 ;
        RECT 573.000000 13.140000 574.000000 3324.020000 ;
        RECT 583.000000 13.140000 584.000000 3324.020000 ;
        RECT 593.000000 13.140000 594.000000 3324.020000 ;
        RECT 603.000000 13.140000 604.000000 3324.020000 ;
        RECT 613.000000 13.140000 614.000000 3324.020000 ;
        RECT 623.000000 13.140000 624.000000 3324.020000 ;
        RECT 633.000000 13.140000 634.000000 3324.020000 ;
        RECT 643.000000 13.140000 644.000000 3324.020000 ;
        RECT 653.000000 13.140000 654.000000 3324.020000 ;
        RECT 663.000000 13.140000 664.000000 3324.020000 ;
        RECT 673.000000 13.140000 674.000000 3324.020000 ;
        RECT 683.000000 13.140000 684.000000 3324.020000 ;
        RECT 693.000000 13.140000 694.000000 3324.020000 ;
        RECT 703.000000 13.140000 704.000000 3324.020000 ;
        RECT 713.000000 13.140000 714.000000 3324.020000 ;
        RECT 723.000000 13.140000 724.000000 3324.020000 ;
        RECT 733.000000 13.140000 734.000000 3324.020000 ;
        RECT 743.000000 13.140000 744.000000 3324.020000 ;
        RECT 753.000000 13.140000 754.000000 3324.020000 ;
        RECT 763.000000 13.140000 764.000000 3324.020000 ;
        RECT 773.000000 13.140000 774.000000 3324.020000 ;
        RECT 783.000000 13.140000 784.000000 3324.020000 ;
        RECT 793.000000 13.140000 794.000000 3324.020000 ;
        RECT 803.000000 13.140000 804.000000 3324.020000 ;
        RECT 813.000000 13.140000 814.000000 3324.020000 ;
        RECT 823.000000 13.140000 824.000000 3324.020000 ;
        RECT 833.000000 13.140000 834.000000 3324.020000 ;
        RECT 843.000000 13.140000 844.000000 3324.020000 ;
        RECT 853.000000 13.140000 854.000000 3324.020000 ;
        RECT 863.000000 13.140000 864.000000 3324.020000 ;
        RECT 873.000000 13.140000 874.000000 3324.020000 ;
        RECT 883.000000 13.140000 884.000000 3324.020000 ;
        RECT 893.000000 13.140000 894.000000 3324.020000 ;
        RECT 903.000000 13.140000 904.000000 3324.020000 ;
        RECT 913.000000 13.140000 914.000000 3324.020000 ;
        RECT 923.000000 13.140000 924.000000 3324.020000 ;
        RECT 933.000000 13.140000 934.000000 3324.020000 ;
        RECT 943.000000 13.140000 944.000000 3324.020000 ;
        RECT 953.000000 13.140000 954.000000 3324.020000 ;
        RECT 963.000000 13.140000 964.000000 3324.020000 ;
        RECT 973.000000 13.140000 974.000000 3324.020000 ;
        RECT 983.000000 13.140000 984.000000 3324.020000 ;
        RECT 993.000000 13.140000 994.000000 3324.020000 ;
        RECT 1003.000000 13.140000 1004.000000 3324.020000 ;
        RECT 1013.000000 13.140000 1014.000000 3324.020000 ;
        RECT 1023.000000 13.140000 1024.000000 3324.020000 ;
        RECT 1033.000000 13.140000 1034.000000 3324.020000 ;
        RECT 1043.000000 13.140000 1044.000000 3324.020000 ;
        RECT 1053.000000 13.140000 1054.000000 3324.020000 ;
        RECT 1063.000000 13.140000 1064.000000 3324.020000 ;
        RECT 1073.000000 13.140000 1074.000000 3324.020000 ;
        RECT 1083.000000 13.140000 1084.000000 3324.020000 ;
        RECT 1093.000000 13.140000 1094.000000 3324.020000 ;
        RECT 1103.000000 13.140000 1104.000000 3324.020000 ;
        RECT 1113.000000 13.140000 1114.000000 3324.020000 ;
        RECT 1123.000000 13.140000 1124.000000 3324.020000 ;
        RECT 1133.000000 13.140000 1134.000000 3324.020000 ;
        RECT 1143.000000 13.140000 1144.000000 3324.020000 ;
        RECT 1153.000000 13.140000 1154.000000 3324.020000 ;
        RECT 1163.000000 13.140000 1164.000000 3324.020000 ;
        RECT 1173.000000 13.140000 1174.000000 3324.020000 ;
        RECT 1183.000000 13.140000 1184.000000 3324.020000 ;
        RECT 1193.000000 13.140000 1194.000000 3324.020000 ;
        RECT 1203.000000 13.140000 1204.000000 3324.020000 ;
        RECT 1213.000000 13.140000 1214.000000 3324.020000 ;
        RECT 1223.000000 13.140000 1224.000000 3324.020000 ;
        RECT 1233.000000 13.140000 1234.000000 3324.020000 ;
        RECT 1243.000000 13.140000 1244.000000 3324.020000 ;
        RECT 1853.000000 13.140000 1854.000000 3324.020000 ;
        RECT 1863.000000 13.140000 1864.000000 3324.020000 ;
        RECT 1873.000000 13.140000 1874.000000 3324.020000 ;
        RECT 1883.000000 13.140000 1884.000000 3324.020000 ;
        RECT 1893.000000 13.140000 1894.000000 3324.020000 ;
        RECT 1903.000000 13.140000 1904.000000 3324.020000 ;
        RECT 1913.000000 13.140000 1914.000000 3324.020000 ;
        RECT 1923.000000 13.140000 1924.000000 3324.020000 ;
        RECT 1933.000000 13.140000 1934.000000 3324.020000 ;
        RECT 1943.000000 13.140000 1944.000000 3324.020000 ;
        RECT 1953.000000 13.140000 1954.000000 3324.020000 ;
        RECT 1963.000000 13.140000 1964.000000 3324.020000 ;
        RECT 1973.000000 13.140000 1974.000000 3324.020000 ;
        RECT 1983.000000 13.140000 1984.000000 3324.020000 ;
        RECT 1993.000000 13.140000 1994.000000 3324.020000 ;
        RECT 2003.000000 13.140000 2004.000000 3324.020000 ;
        RECT 2013.000000 13.140000 2014.000000 3324.020000 ;
        RECT 2023.000000 13.140000 2024.000000 3324.020000 ;
        RECT 2033.000000 13.140000 2034.000000 3324.020000 ;
        RECT 2043.000000 13.140000 2044.000000 3324.020000 ;
        RECT 2053.000000 13.140000 2054.000000 3324.020000 ;
        RECT 2063.000000 13.140000 2064.000000 3324.020000 ;
        RECT 2073.000000 13.140000 2074.000000 3324.020000 ;
        RECT 2083.000000 13.140000 2084.000000 3324.020000 ;
        RECT 2093.000000 13.140000 2094.000000 3324.020000 ;
        RECT 2103.000000 13.140000 2104.000000 3324.020000 ;
        RECT 2113.000000 13.140000 2114.000000 3324.020000 ;
        RECT 2123.000000 13.140000 2124.000000 3324.020000 ;
        RECT 2133.000000 13.140000 2134.000000 3324.020000 ;
        RECT 2143.000000 13.140000 2144.000000 3324.020000 ;
        RECT 2153.000000 13.140000 2154.000000 3324.020000 ;
        RECT 2163.000000 13.140000 2164.000000 3324.020000 ;
        RECT 2173.000000 13.140000 2174.000000 3324.020000 ;
        RECT 2183.000000 13.140000 2184.000000 3324.020000 ;
        RECT 2193.000000 13.140000 2194.000000 3324.020000 ;
        RECT 2203.000000 13.140000 2204.000000 3324.020000 ;
        RECT 2213.000000 13.140000 2214.000000 3324.020000 ;
        RECT 2223.000000 13.140000 2224.000000 3324.020000 ;
        RECT 2233.000000 13.140000 2234.000000 3324.020000 ;
        RECT 2243.000000 13.140000 2244.000000 3324.020000 ;
        RECT 2253.000000 13.140000 2254.000000 3324.020000 ;
        RECT 2263.000000 13.140000 2264.000000 3324.020000 ;
        RECT 2273.000000 13.140000 2274.000000 3324.020000 ;
        RECT 2283.000000 13.140000 2284.000000 3324.020000 ;
        RECT 2293.000000 13.140000 2294.000000 3324.020000 ;
        RECT 2303.000000 13.140000 2304.000000 3324.020000 ;
        RECT 2313.000000 13.140000 2314.000000 3324.020000 ;
        RECT 2323.000000 13.140000 2324.000000 3324.020000 ;
        RECT 2333.000000 13.140000 2334.000000 3324.020000 ;
        RECT 2343.000000 13.140000 2344.000000 3324.020000 ;
        RECT 2353.000000 13.140000 2354.000000 3324.020000 ;
        RECT 2363.000000 13.140000 2364.000000 3324.020000 ;
        RECT 2373.000000 13.140000 2374.000000 3324.020000 ;
        RECT 2383.000000 13.140000 2384.000000 3324.020000 ;
        RECT 2393.000000 13.140000 2394.000000 3324.020000 ;
        RECT 2403.000000 13.140000 2404.000000 3324.020000 ;
        RECT 2413.000000 13.140000 2414.000000 3324.020000 ;
        RECT 2423.000000 13.140000 2424.000000 3324.020000 ;
        RECT 2433.000000 13.140000 2434.000000 3324.020000 ;
        RECT 2443.000000 13.140000 2444.000000 3324.020000 ;
        RECT 2453.000000 13.140000 2454.000000 3324.020000 ;
        RECT 2463.000000 13.140000 2464.000000 3324.020000 ;
        RECT 2473.000000 13.140000 2474.000000 3324.020000 ;
        RECT 2483.000000 13.140000 2484.000000 3324.020000 ;
        RECT 2493.000000 13.140000 2494.000000 3324.020000 ;
        RECT 2503.000000 13.140000 2504.000000 3324.020000 ;
        RECT 2513.000000 13.140000 2514.000000 3324.020000 ;
        RECT 2523.000000 13.140000 2524.000000 3324.020000 ;
        RECT 2533.000000 13.140000 2534.000000 3324.020000 ;
        RECT 2543.000000 13.140000 2544.000000 3324.020000 ;
        RECT 2553.000000 13.140000 2554.000000 3324.020000 ;
        RECT 2563.000000 13.140000 2564.000000 3324.020000 ;
        RECT 2573.000000 13.140000 2574.000000 3324.020000 ;
        RECT 2583.000000 13.140000 2584.000000 3324.020000 ;
        RECT 2593.000000 13.140000 2594.000000 3324.020000 ;
        RECT 2603.000000 13.140000 2604.000000 3324.020000 ;
        RECT 2613.000000 13.140000 2614.000000 3324.020000 ;
        RECT 2623.000000 13.140000 2624.000000 3324.020000 ;
        RECT 2633.000000 13.140000 2634.000000 3324.020000 ;
        RECT 2643.000000 13.140000 2644.000000 3324.020000 ;
        RECT 2653.000000 13.140000 2654.000000 3324.020000 ;
        RECT 2663.000000 13.140000 2664.000000 3324.020000 ;
        RECT 2673.000000 13.140000 2674.000000 3324.020000 ;
        RECT 2683.000000 13.140000 2684.000000 3324.020000 ;
        RECT 2693.000000 13.140000 2694.000000 3324.020000 ;
        RECT 2703.000000 13.140000 2704.000000 3324.020000 ;
        RECT 2713.000000 13.140000 2714.000000 3324.020000 ;
        RECT 2723.000000 13.140000 2724.000000 3324.020000 ;
        RECT 2733.000000 13.140000 2734.000000 3324.020000 ;
        RECT 2743.000000 13.140000 2744.000000 3324.020000 ;
        RECT 2753.000000 13.140000 2754.000000 3324.020000 ;
        RECT 2763.000000 13.140000 2764.000000 3324.020000 ;
        RECT 2773.000000 13.140000 2774.000000 3324.020000 ;
        RECT 2783.000000 13.140000 2784.000000 3324.020000 ;
        RECT 2793.000000 13.140000 2794.000000 3324.020000 ;
        RECT 2803.000000 13.140000 2804.000000 3324.020000 ;
        RECT 2813.000000 13.140000 2814.000000 3324.020000 ;
        RECT 2823.000000 13.140000 2824.000000 3324.020000 ;
        RECT 2833.000000 13.140000 2834.000000 3324.020000 ;
        RECT 2843.000000 13.140000 2844.000000 3324.020000 ;
        RECT 2853.000000 13.140000 2854.000000 3324.020000 ;
        RECT 2863.000000 13.140000 2864.000000 3324.020000 ;
        RECT 2873.000000 13.140000 2874.000000 3324.020000 ;
        RECT 2883.000000 13.140000 2884.000000 3324.020000 ;
        RECT 2893.000000 13.140000 2894.000000 3324.020000 ;
        RECT 2903.000000 13.140000 2904.000000 3324.020000 ;
        RECT 2913.000000 13.140000 2914.000000 3324.020000 ;
        RECT 2923.000000 13.140000 2924.000000 3324.020000 ;
        RECT 2933.000000 13.140000 2934.000000 3324.020000 ;
        RECT 2943.000000 13.140000 2944.000000 3324.020000 ;
        RECT 2953.000000 13.140000 2954.000000 3324.020000 ;
        RECT 2963.000000 13.140000 2964.000000 3324.020000 ;
        RECT 2973.000000 13.140000 2974.000000 3324.020000 ;
        RECT 2983.000000 13.140000 2984.000000 3324.020000 ;
        RECT 2993.000000 13.140000 2994.000000 3324.020000 ;
        RECT 3003.000000 13.140000 3004.000000 3324.020000 ;
        RECT 3013.000000 13.140000 3014.000000 3324.020000 ;
        RECT 3023.000000 13.140000 3024.000000 3324.020000 ;
        RECT 3033.000000 13.140000 3034.000000 3324.020000 ;
        RECT 3043.000000 13.140000 3044.000000 3324.020000 ;
        RECT 3053.000000 13.140000 3054.000000 3324.020000 ;
        RECT 3063.000000 13.140000 3064.000000 3324.020000 ;
        RECT 3073.000000 13.140000 3074.000000 3324.020000 ;
        RECT 3083.000000 13.140000 3084.000000 3324.020000 ;
        RECT 1783.000000 179.025000 1784.000000 3324.020000 ;
        RECT 1793.000000 179.025000 1794.000000 3324.020000 ;
        RECT 1803.000000 179.025000 1804.000000 3324.020000 ;
        RECT 1813.000000 179.025000 1814.000000 3324.020000 ;
        RECT 1823.000000 179.025000 1824.000000 3324.020000 ;
        RECT 1833.000000 179.025000 1834.000000 3324.020000 ;
        RECT 1843.000000 179.025000 1844.000000 3324.020000 ;
        RECT 1783.000000 13.140000 1784.000000 105.375000 ;
        RECT 1793.000000 13.140000 1794.000000 105.375000 ;
        RECT 1803.000000 13.140000 1804.000000 105.375000 ;
        RECT 1813.000000 13.140000 1814.000000 105.375000 ;
        RECT 1823.000000 13.140000 1824.000000 105.375000 ;
        RECT 1833.000000 13.140000 1834.000000 105.375000 ;
        RECT 1843.000000 13.140000 1844.000000 105.375000 ;
        RECT 1144.280000 1034.110000 1144.410000 1034.230000 ;
        RECT 1144.280000 1123.030000 1144.410000 1123.150000 ;
        RECT 1945.175000 209.890000 1945.350000 210.010000 ;
        RECT 3054.280000 1034.110000 3054.410000 1034.230000 ;
        RECT 3054.280000 1123.030000 3054.410000 1123.150000 ;
        RECT 1144.280000 1913.050000 1144.410000 1913.170000 ;
        RECT 1252.600000 2709.910000 1252.770000 2710.030000 ;
        RECT 1144.280000 2744.110000 1144.410000 2744.230000 ;
        RECT 1252.600000 2761.210000 1252.770000 2761.330000 ;
        RECT 1144.280000 2833.030000 1144.410000 2833.150000 ;
        RECT 1252.600000 2839.870000 1252.770000 2839.990000 ;
        RECT 1252.600000 2884.330000 1252.770000 2884.450000 ;
        RECT 1252.600000 2969.830000 1252.770000 2969.950000 ;
        RECT 1252.600000 3014.290000 1252.770000 3014.410000 ;
        RECT 1252.600000 3092.950000 1252.770000 3093.070000 ;
        RECT 1252.600000 3144.250000 1252.770000 3144.370000 ;
        RECT 3054.280000 1913.050000 3054.410000 1913.170000 ;
        RECT 3054.280000 2744.110000 3054.410000 2744.230000 ;
        RECT 3054.280000 2833.030000 3054.410000 2833.150000 ;
    END
# end of P/G power stripe data as pin

  END vss
  OBS
    LAYER Metal1 ;
      RECT 0.000000 0.000000 3112.000000 3337.160000 ;
    LAYER Metal2 ;
      RECT 0.000000 0.000000 3112.000000 3337.160000 ;
    LAYER Metal3 ;
      RECT 0.000000 0.000000 3112.000000 3337.160000 ;
    LAYER Metal4 ;
      RECT 0.000000 0.000000 3112.000000 3337.160000 ;
    LAYER Metal5 ;
      RECT 0.000000 0.000000 3112.000000 3337.160000 ;
    LAYER Metal6 ;
      RECT 0.000000 3337.025000 3112.000000 3337.160000 ;
      RECT 0.440000 3336.655000 3112.000000 3337.025000 ;
      RECT 0.000000 3322.675000 3112.000000 3336.655000 ;
      RECT 0.440000 3322.305000 3112.000000 3322.675000 ;
      RECT 0.000000 3308.320000 3112.000000 3322.305000 ;
      RECT 0.440000 3307.950000 3112.000000 3308.320000 ;
      RECT 0.000000 3293.970000 3112.000000 3307.950000 ;
      RECT 0.440000 3293.600000 3112.000000 3293.970000 ;
      RECT 0.000000 3279.615000 3112.000000 3293.600000 ;
      RECT 0.440000 3279.245000 3112.000000 3279.615000 ;
      RECT 0.000000 3265.265000 3112.000000 3279.245000 ;
      RECT 0.440000 3264.895000 3112.000000 3265.265000 ;
      RECT 0.000000 3250.915000 3112.000000 3264.895000 ;
      RECT 0.440000 3250.545000 3112.000000 3250.915000 ;
      RECT 0.000000 3236.560000 3112.000000 3250.545000 ;
      RECT 0.440000 3236.190000 3112.000000 3236.560000 ;
      RECT 0.000000 3222.210000 3112.000000 3236.190000 ;
      RECT 0.440000 3221.840000 3112.000000 3222.210000 ;
      RECT 0.000000 3207.855000 3112.000000 3221.840000 ;
      RECT 0.440000 3207.485000 3112.000000 3207.855000 ;
      RECT 0.000000 3193.505000 3112.000000 3207.485000 ;
      RECT 0.440000 3193.135000 3112.000000 3193.505000 ;
      RECT 0.000000 3179.155000 3112.000000 3193.135000 ;
      RECT 0.440000 3178.785000 3112.000000 3179.155000 ;
      RECT 0.000000 3164.800000 3112.000000 3178.785000 ;
      RECT 0.440000 3164.430000 3112.000000 3164.800000 ;
      RECT 0.000000 3150.450000 3112.000000 3164.430000 ;
      RECT 0.440000 3150.080000 3112.000000 3150.450000 ;
      RECT 0.000000 3136.095000 3112.000000 3150.080000 ;
      RECT 0.440000 3135.725000 3112.000000 3136.095000 ;
      RECT 0.000000 3121.745000 3112.000000 3135.725000 ;
      RECT 0.440000 3121.375000 3112.000000 3121.745000 ;
      RECT 0.000000 3107.395000 3112.000000 3121.375000 ;
      RECT 0.440000 3107.025000 3112.000000 3107.395000 ;
      RECT 0.000000 3093.040000 3112.000000 3107.025000 ;
      RECT 0.440000 3092.670000 3112.000000 3093.040000 ;
      RECT 0.000000 3078.690000 3112.000000 3092.670000 ;
      RECT 0.440000 3078.320000 3112.000000 3078.690000 ;
      RECT 0.000000 3064.335000 3112.000000 3078.320000 ;
      RECT 0.440000 3063.965000 3112.000000 3064.335000 ;
      RECT 0.000000 3049.985000 3112.000000 3063.965000 ;
      RECT 0.440000 3049.615000 3112.000000 3049.985000 ;
      RECT 0.000000 3035.635000 3112.000000 3049.615000 ;
      RECT 0.440000 3035.265000 3112.000000 3035.635000 ;
      RECT 0.000000 3021.280000 3112.000000 3035.265000 ;
      RECT 0.440000 3020.910000 3112.000000 3021.280000 ;
      RECT 0.000000 3006.930000 3112.000000 3020.910000 ;
      RECT 0.440000 3006.560000 3112.000000 3006.930000 ;
      RECT 0.000000 2992.575000 3112.000000 3006.560000 ;
      RECT 0.440000 2992.205000 3112.000000 2992.575000 ;
      RECT 0.000000 2978.225000 3112.000000 2992.205000 ;
      RECT 0.440000 2977.855000 3112.000000 2978.225000 ;
      RECT 0.000000 2963.875000 3112.000000 2977.855000 ;
      RECT 0.440000 2963.505000 3112.000000 2963.875000 ;
      RECT 0.000000 2949.520000 3112.000000 2963.505000 ;
      RECT 0.440000 2949.150000 3112.000000 2949.520000 ;
      RECT 0.000000 2935.170000 3112.000000 2949.150000 ;
      RECT 0.440000 2934.800000 3112.000000 2935.170000 ;
      RECT 0.000000 2920.815000 3112.000000 2934.800000 ;
      RECT 0.440000 2920.445000 3112.000000 2920.815000 ;
      RECT 0.000000 2906.465000 3112.000000 2920.445000 ;
      RECT 0.440000 2906.095000 3112.000000 2906.465000 ;
      RECT 0.000000 2892.115000 3112.000000 2906.095000 ;
      RECT 0.440000 2891.745000 3112.000000 2892.115000 ;
      RECT 0.000000 2877.760000 3112.000000 2891.745000 ;
      RECT 0.440000 2877.390000 3112.000000 2877.760000 ;
      RECT 0.000000 2863.410000 3112.000000 2877.390000 ;
      RECT 0.440000 2863.040000 3112.000000 2863.410000 ;
      RECT 0.000000 2849.055000 3112.000000 2863.040000 ;
      RECT 0.440000 2848.685000 3112.000000 2849.055000 ;
      RECT 0.000000 2834.705000 3112.000000 2848.685000 ;
      RECT 0.440000 2834.335000 3112.000000 2834.705000 ;
      RECT 0.000000 2820.355000 3112.000000 2834.335000 ;
      RECT 0.440000 2819.985000 3112.000000 2820.355000 ;
      RECT 0.000000 2806.000000 3112.000000 2819.985000 ;
      RECT 0.440000 2805.630000 3112.000000 2806.000000 ;
      RECT 0.000000 2791.650000 3112.000000 2805.630000 ;
      RECT 0.440000 2791.280000 3112.000000 2791.650000 ;
      RECT 0.000000 2777.295000 3112.000000 2791.280000 ;
      RECT 0.440000 2776.925000 3112.000000 2777.295000 ;
      RECT 0.000000 2762.945000 3112.000000 2776.925000 ;
      RECT 0.440000 2762.575000 3112.000000 2762.945000 ;
      RECT 0.000000 2748.595000 3112.000000 2762.575000 ;
      RECT 0.440000 2748.225000 3112.000000 2748.595000 ;
      RECT 0.000000 2734.240000 3112.000000 2748.225000 ;
      RECT 0.440000 2733.870000 3112.000000 2734.240000 ;
      RECT 0.000000 2719.890000 3112.000000 2733.870000 ;
      RECT 0.440000 2719.520000 3112.000000 2719.890000 ;
      RECT 0.000000 2705.535000 3112.000000 2719.520000 ;
      RECT 0.440000 2705.165000 3112.000000 2705.535000 ;
      RECT 0.000000 2691.185000 3112.000000 2705.165000 ;
      RECT 0.440000 2690.815000 3112.000000 2691.185000 ;
      RECT 0.000000 2676.835000 3112.000000 2690.815000 ;
      RECT 0.440000 2676.465000 3112.000000 2676.835000 ;
      RECT 0.000000 2662.480000 3112.000000 2676.465000 ;
      RECT 0.440000 2662.110000 3112.000000 2662.480000 ;
      RECT 0.000000 2648.130000 3112.000000 2662.110000 ;
      RECT 0.440000 2647.760000 3112.000000 2648.130000 ;
      RECT 0.000000 2633.775000 3112.000000 2647.760000 ;
      RECT 0.440000 2633.405000 3112.000000 2633.775000 ;
      RECT 0.000000 2619.425000 3112.000000 2633.405000 ;
      RECT 0.440000 2619.055000 3112.000000 2619.425000 ;
      RECT 0.000000 2605.075000 3112.000000 2619.055000 ;
      RECT 0.440000 2604.705000 3112.000000 2605.075000 ;
      RECT 0.000000 2590.720000 3112.000000 2604.705000 ;
      RECT 0.440000 2590.350000 3112.000000 2590.720000 ;
      RECT 0.000000 2576.370000 3112.000000 2590.350000 ;
      RECT 0.440000 2576.000000 3112.000000 2576.370000 ;
      RECT 0.000000 2562.015000 3112.000000 2576.000000 ;
      RECT 0.440000 2561.645000 3112.000000 2562.015000 ;
      RECT 0.000000 2547.665000 3112.000000 2561.645000 ;
      RECT 0.440000 2547.295000 3112.000000 2547.665000 ;
      RECT 0.000000 2533.315000 3112.000000 2547.295000 ;
      RECT 0.440000 2532.945000 3112.000000 2533.315000 ;
      RECT 0.000000 2518.960000 3112.000000 2532.945000 ;
      RECT 0.440000 2518.590000 3112.000000 2518.960000 ;
      RECT 0.000000 2504.610000 3112.000000 2518.590000 ;
      RECT 0.440000 2504.240000 3112.000000 2504.610000 ;
      RECT 0.000000 2490.255000 3112.000000 2504.240000 ;
      RECT 0.440000 2489.885000 3112.000000 2490.255000 ;
      RECT 0.000000 2475.905000 3112.000000 2489.885000 ;
      RECT 0.440000 2475.535000 3112.000000 2475.905000 ;
      RECT 0.000000 2461.555000 3112.000000 2475.535000 ;
      RECT 0.440000 2461.185000 3112.000000 2461.555000 ;
      RECT 0.000000 2447.200000 3112.000000 2461.185000 ;
      RECT 0.440000 2446.830000 3112.000000 2447.200000 ;
      RECT 0.000000 2432.850000 3112.000000 2446.830000 ;
      RECT 0.440000 2432.480000 3112.000000 2432.850000 ;
      RECT 0.000000 2418.495000 3112.000000 2432.480000 ;
      RECT 0.440000 2418.125000 3112.000000 2418.495000 ;
      RECT 0.000000 2404.145000 3112.000000 2418.125000 ;
      RECT 0.440000 2403.775000 3112.000000 2404.145000 ;
      RECT 0.000000 2389.795000 3112.000000 2403.775000 ;
      RECT 0.440000 2389.425000 3112.000000 2389.795000 ;
      RECT 0.000000 2375.440000 3112.000000 2389.425000 ;
      RECT 0.440000 2375.070000 3112.000000 2375.440000 ;
      RECT 0.000000 2361.090000 3112.000000 2375.070000 ;
      RECT 0.440000 2360.720000 3111.560000 2361.090000 ;
      RECT 0.000000 2346.735000 3112.000000 2360.720000 ;
      RECT 0.440000 2346.365000 3111.560000 2346.735000 ;
      RECT 0.000000 2332.385000 3112.000000 2346.365000 ;
      RECT 0.440000 2332.015000 3111.560000 2332.385000 ;
      RECT 0.000000 2318.035000 3112.000000 2332.015000 ;
      RECT 0.440000 2317.665000 3111.560000 2318.035000 ;
      RECT 0.000000 2303.680000 3112.000000 2317.665000 ;
      RECT 0.440000 2303.310000 3111.560000 2303.680000 ;
      RECT 0.000000 2289.330000 3112.000000 2303.310000 ;
      RECT 0.440000 2288.960000 3111.560000 2289.330000 ;
      RECT 0.000000 2274.975000 3112.000000 2288.960000 ;
      RECT 0.440000 2274.605000 3111.560000 2274.975000 ;
      RECT 0.000000 2260.625000 3112.000000 2274.605000 ;
      RECT 0.440000 2260.255000 3111.560000 2260.625000 ;
      RECT 0.000000 2246.275000 3112.000000 2260.255000 ;
      RECT 0.440000 2245.905000 3111.560000 2246.275000 ;
      RECT 0.000000 2231.920000 3112.000000 2245.905000 ;
      RECT 0.440000 2231.550000 3111.560000 2231.920000 ;
      RECT 0.000000 2217.570000 3112.000000 2231.550000 ;
      RECT 0.440000 2217.200000 3111.560000 2217.570000 ;
      RECT 0.000000 2203.215000 3112.000000 2217.200000 ;
      RECT 0.440000 2202.845000 3111.560000 2203.215000 ;
      RECT 0.000000 2188.865000 3112.000000 2202.845000 ;
      RECT 0.440000 2188.495000 3111.560000 2188.865000 ;
      RECT 0.000000 2174.515000 3112.000000 2188.495000 ;
      RECT 0.440000 2174.145000 3111.560000 2174.515000 ;
      RECT 0.000000 2160.160000 3112.000000 2174.145000 ;
      RECT 0.440000 2159.790000 3111.560000 2160.160000 ;
      RECT 0.000000 2145.810000 3112.000000 2159.790000 ;
      RECT 0.440000 2145.440000 3111.560000 2145.810000 ;
      RECT 0.000000 2131.455000 3112.000000 2145.440000 ;
      RECT 0.440000 2131.085000 3111.560000 2131.455000 ;
      RECT 0.000000 2117.105000 3112.000000 2131.085000 ;
      RECT 0.440000 2116.735000 3111.560000 2117.105000 ;
      RECT 0.000000 2102.755000 3112.000000 2116.735000 ;
      RECT 0.440000 2102.385000 3111.560000 2102.755000 ;
      RECT 0.000000 2088.400000 3112.000000 2102.385000 ;
      RECT 0.440000 2088.030000 3111.560000 2088.400000 ;
      RECT 0.000000 2074.050000 3112.000000 2088.030000 ;
      RECT 0.440000 2073.680000 3111.560000 2074.050000 ;
      RECT 0.000000 2059.695000 3112.000000 2073.680000 ;
      RECT 0.440000 2059.325000 3111.560000 2059.695000 ;
      RECT 0.000000 2045.345000 3112.000000 2059.325000 ;
      RECT 0.440000 2044.975000 3111.560000 2045.345000 ;
      RECT 0.000000 2030.995000 3112.000000 2044.975000 ;
      RECT 0.440000 2030.625000 3111.560000 2030.995000 ;
      RECT 0.000000 2016.640000 3112.000000 2030.625000 ;
      RECT 0.440000 2016.270000 3111.560000 2016.640000 ;
      RECT 0.000000 2002.290000 3112.000000 2016.270000 ;
      RECT 0.440000 2001.920000 3111.560000 2002.290000 ;
      RECT 0.000000 1987.935000 3112.000000 2001.920000 ;
      RECT 0.440000 1987.565000 3111.560000 1987.935000 ;
      RECT 0.000000 1973.585000 3112.000000 1987.565000 ;
      RECT 0.440000 1973.215000 3111.560000 1973.585000 ;
      RECT 0.000000 1959.235000 3112.000000 1973.215000 ;
      RECT 0.440000 1958.865000 3111.560000 1959.235000 ;
      RECT 0.000000 1944.880000 3112.000000 1958.865000 ;
      RECT 0.440000 1944.510000 3111.560000 1944.880000 ;
      RECT 0.000000 1930.530000 3112.000000 1944.510000 ;
      RECT 0.440000 1930.160000 3111.560000 1930.530000 ;
      RECT 0.000000 1916.175000 3112.000000 1930.160000 ;
      RECT 0.440000 1915.805000 3111.560000 1916.175000 ;
      RECT 0.000000 1901.825000 3112.000000 1915.805000 ;
      RECT 0.440000 1901.455000 3111.560000 1901.825000 ;
      RECT 0.000000 1887.475000 3112.000000 1901.455000 ;
      RECT 0.440000 1887.105000 3111.560000 1887.475000 ;
      RECT 0.000000 1873.120000 3112.000000 1887.105000 ;
      RECT 0.440000 1872.750000 3111.560000 1873.120000 ;
      RECT 0.000000 1858.770000 3112.000000 1872.750000 ;
      RECT 0.440000 1858.400000 3111.560000 1858.770000 ;
      RECT 0.000000 1844.415000 3112.000000 1858.400000 ;
      RECT 0.440000 1844.045000 3111.560000 1844.415000 ;
      RECT 0.000000 1830.065000 3112.000000 1844.045000 ;
      RECT 0.440000 1829.695000 3111.560000 1830.065000 ;
      RECT 0.000000 1815.715000 3112.000000 1829.695000 ;
      RECT 0.440000 1815.345000 3111.560000 1815.715000 ;
      RECT 0.000000 1801.360000 3112.000000 1815.345000 ;
      RECT 0.440000 1800.990000 3111.560000 1801.360000 ;
      RECT 0.000000 1787.010000 3112.000000 1800.990000 ;
      RECT 0.440000 1786.640000 3111.560000 1787.010000 ;
      RECT 0.000000 1772.655000 3112.000000 1786.640000 ;
      RECT 0.440000 1772.285000 3111.560000 1772.655000 ;
      RECT 0.000000 1758.305000 3112.000000 1772.285000 ;
      RECT 0.440000 1757.935000 3111.560000 1758.305000 ;
      RECT 0.000000 1743.955000 3112.000000 1757.935000 ;
      RECT 0.440000 1743.585000 3111.560000 1743.955000 ;
      RECT 0.000000 1729.600000 3112.000000 1743.585000 ;
      RECT 0.440000 1729.230000 3111.560000 1729.600000 ;
      RECT 0.000000 1715.250000 3112.000000 1729.230000 ;
      RECT 0.440000 1714.880000 3111.560000 1715.250000 ;
      RECT 0.000000 1700.895000 3112.000000 1714.880000 ;
      RECT 0.440000 1700.525000 3111.560000 1700.895000 ;
      RECT 0.000000 1686.545000 3112.000000 1700.525000 ;
      RECT 0.440000 1686.175000 3111.560000 1686.545000 ;
      RECT 0.000000 1672.195000 3112.000000 1686.175000 ;
      RECT 0.440000 1671.825000 3111.560000 1672.195000 ;
      RECT 0.000000 1657.840000 3112.000000 1671.825000 ;
      RECT 0.440000 1657.470000 3111.560000 1657.840000 ;
      RECT 0.000000 1643.490000 3112.000000 1657.470000 ;
      RECT 0.440000 1643.120000 3111.560000 1643.490000 ;
      RECT 0.000000 1629.135000 3112.000000 1643.120000 ;
      RECT 0.440000 1628.765000 3111.560000 1629.135000 ;
      RECT 0.000000 1614.785000 3112.000000 1628.765000 ;
      RECT 0.440000 1614.415000 3111.560000 1614.785000 ;
      RECT 0.000000 1600.435000 3112.000000 1614.415000 ;
      RECT 0.440000 1600.065000 3111.560000 1600.435000 ;
      RECT 0.000000 1586.080000 3112.000000 1600.065000 ;
      RECT 0.440000 1585.710000 3111.560000 1586.080000 ;
      RECT 0.000000 1571.730000 3112.000000 1585.710000 ;
      RECT 0.440000 1571.360000 3111.560000 1571.730000 ;
      RECT 0.000000 1557.375000 3112.000000 1571.360000 ;
      RECT 0.440000 1557.005000 3111.560000 1557.375000 ;
      RECT 0.000000 1543.025000 3112.000000 1557.005000 ;
      RECT 0.440000 1542.655000 3111.560000 1543.025000 ;
      RECT 0.000000 1528.675000 3112.000000 1542.655000 ;
      RECT 0.440000 1528.305000 3111.560000 1528.675000 ;
      RECT 0.000000 1514.320000 3112.000000 1528.305000 ;
      RECT 0.440000 1513.950000 3111.560000 1514.320000 ;
      RECT 0.000000 1499.970000 3112.000000 1513.950000 ;
      RECT 0.440000 1499.600000 3111.560000 1499.970000 ;
      RECT 0.000000 1485.615000 3112.000000 1499.600000 ;
      RECT 0.440000 1485.245000 3111.560000 1485.615000 ;
      RECT 0.000000 1471.265000 3112.000000 1485.245000 ;
      RECT 0.440000 1470.895000 3111.560000 1471.265000 ;
      RECT 0.000000 1456.915000 3112.000000 1470.895000 ;
      RECT 0.440000 1456.545000 3111.560000 1456.915000 ;
      RECT 0.000000 1442.560000 3112.000000 1456.545000 ;
      RECT 0.440000 1442.190000 3111.560000 1442.560000 ;
      RECT 0.000000 1428.210000 3112.000000 1442.190000 ;
      RECT 0.440000 1427.840000 3111.560000 1428.210000 ;
      RECT 0.000000 1413.855000 3112.000000 1427.840000 ;
      RECT 0.440000 1413.485000 3111.560000 1413.855000 ;
      RECT 0.000000 1399.505000 3112.000000 1413.485000 ;
      RECT 0.440000 1399.135000 3111.560000 1399.505000 ;
      RECT 0.000000 1385.155000 3112.000000 1399.135000 ;
      RECT 0.440000 1384.785000 3111.560000 1385.155000 ;
      RECT 0.000000 1370.800000 3112.000000 1384.785000 ;
      RECT 0.440000 1370.430000 3111.560000 1370.800000 ;
      RECT 0.000000 1356.450000 3112.000000 1370.430000 ;
      RECT 0.440000 1356.080000 3111.560000 1356.450000 ;
      RECT 0.000000 1342.095000 3112.000000 1356.080000 ;
      RECT 0.440000 1341.725000 3111.560000 1342.095000 ;
      RECT 0.000000 1327.745000 3112.000000 1341.725000 ;
      RECT 0.440000 1327.375000 3111.560000 1327.745000 ;
      RECT 0.000000 1313.395000 3112.000000 1327.375000 ;
      RECT 0.440000 1313.025000 3111.560000 1313.395000 ;
      RECT 0.000000 1299.040000 3112.000000 1313.025000 ;
      RECT 0.440000 1298.670000 3111.560000 1299.040000 ;
      RECT 0.000000 1284.690000 3112.000000 1298.670000 ;
      RECT 0.440000 1284.320000 3111.560000 1284.690000 ;
      RECT 0.000000 1270.335000 3112.000000 1284.320000 ;
      RECT 0.440000 1269.965000 3111.560000 1270.335000 ;
      RECT 0.000000 1255.985000 3112.000000 1269.965000 ;
      RECT 0.440000 1255.615000 3111.560000 1255.985000 ;
      RECT 0.000000 1241.635000 3112.000000 1255.615000 ;
      RECT 0.440000 1241.265000 3111.560000 1241.635000 ;
      RECT 0.000000 1227.280000 3112.000000 1241.265000 ;
      RECT 0.440000 1226.910000 3111.560000 1227.280000 ;
      RECT 0.000000 1212.930000 3112.000000 1226.910000 ;
      RECT 0.440000 1212.560000 3111.560000 1212.930000 ;
      RECT 0.000000 1198.575000 3112.000000 1212.560000 ;
      RECT 0.440000 1198.205000 3111.560000 1198.575000 ;
      RECT 0.000000 1184.225000 3112.000000 1198.205000 ;
      RECT 0.440000 1183.855000 3111.560000 1184.225000 ;
      RECT 0.000000 1169.875000 3112.000000 1183.855000 ;
      RECT 0.440000 1169.505000 3111.560000 1169.875000 ;
      RECT 0.000000 1155.520000 3112.000000 1169.505000 ;
      RECT 0.440000 1155.150000 3111.560000 1155.520000 ;
      RECT 0.000000 1141.170000 3112.000000 1155.150000 ;
      RECT 0.440000 1140.800000 3111.560000 1141.170000 ;
      RECT 0.000000 1126.815000 3112.000000 1140.800000 ;
      RECT 0.440000 1126.445000 3111.560000 1126.815000 ;
      RECT 0.000000 1112.465000 3112.000000 1126.445000 ;
      RECT 0.440000 1112.095000 3111.560000 1112.465000 ;
      RECT 0.000000 1098.115000 3112.000000 1112.095000 ;
      RECT 0.440000 1097.745000 3111.560000 1098.115000 ;
      RECT 0.000000 1083.760000 3112.000000 1097.745000 ;
      RECT 0.440000 1083.390000 3111.560000 1083.760000 ;
      RECT 0.000000 1069.410000 3112.000000 1083.390000 ;
      RECT 0.440000 1069.040000 3111.560000 1069.410000 ;
      RECT 0.000000 1055.055000 3112.000000 1069.040000 ;
      RECT 0.440000 1054.685000 3111.560000 1055.055000 ;
      RECT 0.000000 1040.705000 3112.000000 1054.685000 ;
      RECT 0.440000 1040.335000 3111.560000 1040.705000 ;
      RECT 0.000000 1026.355000 3112.000000 1040.335000 ;
      RECT 0.440000 1025.985000 3111.560000 1026.355000 ;
      RECT 0.000000 1012.000000 3112.000000 1025.985000 ;
      RECT 0.440000 1011.630000 3111.560000 1012.000000 ;
      RECT 0.000000 997.650000 3112.000000 1011.630000 ;
      RECT 0.440000 997.280000 3111.560000 997.650000 ;
      RECT 0.000000 983.295000 3112.000000 997.280000 ;
      RECT 0.440000 982.925000 3111.560000 983.295000 ;
      RECT 0.000000 968.945000 3112.000000 982.925000 ;
      RECT 0.440000 968.575000 3111.560000 968.945000 ;
      RECT 0.000000 954.595000 3112.000000 968.575000 ;
      RECT 0.440000 954.225000 3111.560000 954.595000 ;
      RECT 0.000000 940.240000 3112.000000 954.225000 ;
      RECT 0.440000 939.870000 3111.560000 940.240000 ;
      RECT 0.000000 925.890000 3112.000000 939.870000 ;
      RECT 0.440000 925.520000 3111.560000 925.890000 ;
      RECT 0.000000 911.535000 3112.000000 925.520000 ;
      RECT 0.440000 911.165000 3111.560000 911.535000 ;
      RECT 0.000000 897.185000 3112.000000 911.165000 ;
      RECT 0.440000 896.815000 3111.560000 897.185000 ;
      RECT 0.000000 0.000000 3112.000000 896.815000 ;
    LAYER Metal7 ;
      RECT 0.000000 0.000000 3112.000000 3337.160000 ;
    LAYER Metal8 ;
      RECT 0.000000 0.000000 3112.000000 3337.160000 ;
    LAYER Metal9 ;
      RECT 0.000000 3325.270000 3112.000000 3337.160000 ;
      RECT 3085.250000 3321.270000 3095.750000 3325.270000 ;
      RECT 3075.250000 3321.270000 3081.750000 3325.270000 ;
      RECT 3065.250000 3321.270000 3071.750000 3325.270000 ;
      RECT 3055.250000 3321.270000 3061.750000 3325.270000 ;
      RECT 3045.250000 3321.270000 3051.750000 3325.270000 ;
      RECT 3035.250000 3321.270000 3041.750000 3325.270000 ;
      RECT 3025.250000 3321.270000 3031.750000 3325.270000 ;
      RECT 3015.250000 3321.270000 3021.750000 3325.270000 ;
      RECT 3005.250000 3321.270000 3011.750000 3325.270000 ;
      RECT 2995.250000 3321.270000 3001.750000 3325.270000 ;
      RECT 2985.250000 3321.270000 2991.750000 3325.270000 ;
      RECT 2975.250000 3321.270000 2981.750000 3325.270000 ;
      RECT 2965.250000 3321.270000 2971.750000 3325.270000 ;
      RECT 2955.250000 3321.270000 2961.750000 3325.270000 ;
      RECT 2945.250000 3321.270000 2951.750000 3325.270000 ;
      RECT 2935.250000 3321.270000 2941.750000 3325.270000 ;
      RECT 2925.250000 3321.270000 2931.750000 3325.270000 ;
      RECT 2915.250000 3321.270000 2921.750000 3325.270000 ;
      RECT 2905.250000 3321.270000 2911.750000 3325.270000 ;
      RECT 2895.250000 3321.270000 2901.750000 3325.270000 ;
      RECT 2885.250000 3321.270000 2891.750000 3325.270000 ;
      RECT 2875.250000 3321.270000 2881.750000 3325.270000 ;
      RECT 2865.250000 3321.270000 2871.750000 3325.270000 ;
      RECT 2855.250000 3321.270000 2861.750000 3325.270000 ;
      RECT 2845.250000 3321.270000 2851.750000 3325.270000 ;
      RECT 2835.250000 3321.270000 2841.750000 3325.270000 ;
      RECT 2825.250000 3321.270000 2831.750000 3325.270000 ;
      RECT 2815.250000 3321.270000 2821.750000 3325.270000 ;
      RECT 2805.250000 3321.270000 2811.750000 3325.270000 ;
      RECT 2795.250000 3321.270000 2801.750000 3325.270000 ;
      RECT 2785.250000 3321.270000 2791.750000 3325.270000 ;
      RECT 2775.250000 3321.270000 2781.750000 3325.270000 ;
      RECT 2765.250000 3321.270000 2771.750000 3325.270000 ;
      RECT 2755.250000 3321.270000 2761.750000 3325.270000 ;
      RECT 2745.250000 3321.270000 2751.750000 3325.270000 ;
      RECT 2735.250000 3321.270000 2741.750000 3325.270000 ;
      RECT 2725.250000 3321.270000 2731.750000 3325.270000 ;
      RECT 2715.250000 3321.270000 2721.750000 3325.270000 ;
      RECT 2705.250000 3321.270000 2711.750000 3325.270000 ;
      RECT 2695.250000 3321.270000 2701.750000 3325.270000 ;
      RECT 2685.250000 3321.270000 2691.750000 3325.270000 ;
      RECT 2675.250000 3321.270000 2681.750000 3325.270000 ;
      RECT 2665.250000 3321.270000 2671.750000 3325.270000 ;
      RECT 2655.250000 3321.270000 2661.750000 3325.270000 ;
      RECT 2645.250000 3321.270000 2651.750000 3325.270000 ;
      RECT 2635.250000 3321.270000 2641.750000 3325.270000 ;
      RECT 2625.250000 3321.270000 2631.750000 3325.270000 ;
      RECT 2615.250000 3321.270000 2621.750000 3325.270000 ;
      RECT 2605.250000 3321.270000 2611.750000 3325.270000 ;
      RECT 2595.250000 3321.270000 2601.750000 3325.270000 ;
      RECT 2585.250000 3321.270000 2591.750000 3325.270000 ;
      RECT 2575.250000 3321.270000 2581.750000 3325.270000 ;
      RECT 2565.250000 3321.270000 2571.750000 3325.270000 ;
      RECT 2555.250000 3321.270000 2561.750000 3325.270000 ;
      RECT 2545.250000 3321.270000 2551.750000 3325.270000 ;
      RECT 2535.250000 3321.270000 2541.750000 3325.270000 ;
      RECT 2525.250000 3321.270000 2531.750000 3325.270000 ;
      RECT 2515.250000 3321.270000 2521.750000 3325.270000 ;
      RECT 2505.250000 3321.270000 2511.750000 3325.270000 ;
      RECT 2495.250000 3321.270000 2501.750000 3325.270000 ;
      RECT 2485.250000 3321.270000 2491.750000 3325.270000 ;
      RECT 2475.250000 3321.270000 2481.750000 3325.270000 ;
      RECT 2465.250000 3321.270000 2471.750000 3325.270000 ;
      RECT 2455.250000 3321.270000 2461.750000 3325.270000 ;
      RECT 2445.250000 3321.270000 2451.750000 3325.270000 ;
      RECT 2435.250000 3321.270000 2441.750000 3325.270000 ;
      RECT 2425.250000 3321.270000 2431.750000 3325.270000 ;
      RECT 2415.250000 3321.270000 2421.750000 3325.270000 ;
      RECT 2405.250000 3321.270000 2411.750000 3325.270000 ;
      RECT 2395.250000 3321.270000 2401.750000 3325.270000 ;
      RECT 2385.250000 3321.270000 2391.750000 3325.270000 ;
      RECT 2375.250000 3321.270000 2381.750000 3325.270000 ;
      RECT 2365.250000 3321.270000 2371.750000 3325.270000 ;
      RECT 2355.250000 3321.270000 2361.750000 3325.270000 ;
      RECT 2345.250000 3321.270000 2351.750000 3325.270000 ;
      RECT 2335.250000 3321.270000 2341.750000 3325.270000 ;
      RECT 2325.250000 3321.270000 2331.750000 3325.270000 ;
      RECT 2315.250000 3321.270000 2321.750000 3325.270000 ;
      RECT 2305.250000 3321.270000 2311.750000 3325.270000 ;
      RECT 2295.250000 3321.270000 2301.750000 3325.270000 ;
      RECT 2285.250000 3321.270000 2291.750000 3325.270000 ;
      RECT 2275.250000 3321.270000 2281.750000 3325.270000 ;
      RECT 2265.250000 3321.270000 2271.750000 3325.270000 ;
      RECT 2255.250000 3321.270000 2261.750000 3325.270000 ;
      RECT 2245.250000 3321.270000 2251.750000 3325.270000 ;
      RECT 2235.250000 3321.270000 2241.750000 3325.270000 ;
      RECT 2225.250000 3321.270000 2231.750000 3325.270000 ;
      RECT 2215.250000 3321.270000 2221.750000 3325.270000 ;
      RECT 2205.250000 3321.270000 2211.750000 3325.270000 ;
      RECT 2195.250000 3321.270000 2201.750000 3325.270000 ;
      RECT 2185.250000 3321.270000 2191.750000 3325.270000 ;
      RECT 2175.250000 3321.270000 2181.750000 3325.270000 ;
      RECT 2165.250000 3321.270000 2171.750000 3325.270000 ;
      RECT 2155.250000 3321.270000 2161.750000 3325.270000 ;
      RECT 2145.250000 3321.270000 2151.750000 3325.270000 ;
      RECT 2135.250000 3321.270000 2141.750000 3325.270000 ;
      RECT 2125.250000 3321.270000 2131.750000 3325.270000 ;
      RECT 2115.250000 3321.270000 2121.750000 3325.270000 ;
      RECT 2105.250000 3321.270000 2111.750000 3325.270000 ;
      RECT 2095.250000 3321.270000 2101.750000 3325.270000 ;
      RECT 2085.250000 3321.270000 2091.750000 3325.270000 ;
      RECT 2075.250000 3321.270000 2081.750000 3325.270000 ;
      RECT 2065.250000 3321.270000 2071.750000 3325.270000 ;
      RECT 2055.250000 3321.270000 2061.750000 3325.270000 ;
      RECT 2045.250000 3321.270000 2051.750000 3325.270000 ;
      RECT 2035.250000 3321.270000 2041.750000 3325.270000 ;
      RECT 2025.250000 3321.270000 2031.750000 3325.270000 ;
      RECT 2015.250000 3321.270000 2021.750000 3325.270000 ;
      RECT 2005.250000 3321.270000 2011.750000 3325.270000 ;
      RECT 1995.250000 3321.270000 2001.750000 3325.270000 ;
      RECT 1985.250000 3321.270000 1991.750000 3325.270000 ;
      RECT 1975.250000 3321.270000 1981.750000 3325.270000 ;
      RECT 1965.250000 3321.270000 1971.750000 3325.270000 ;
      RECT 1955.250000 3321.270000 1961.750000 3325.270000 ;
      RECT 1945.250000 3321.270000 1951.750000 3325.270000 ;
      RECT 1935.250000 3321.270000 1941.750000 3325.270000 ;
      RECT 1925.250000 3321.270000 1931.750000 3325.270000 ;
      RECT 1915.250000 3321.270000 1921.750000 3325.270000 ;
      RECT 1905.250000 3321.270000 1911.750000 3325.270000 ;
      RECT 1895.250000 3321.270000 1901.750000 3325.270000 ;
      RECT 1885.250000 3321.270000 1891.750000 3325.270000 ;
      RECT 1875.250000 3321.270000 1881.750000 3325.270000 ;
      RECT 1865.250000 3321.270000 1871.750000 3325.270000 ;
      RECT 1855.250000 3321.270000 1861.750000 3325.270000 ;
      RECT 1845.250000 3321.270000 1851.750000 3325.270000 ;
      RECT 1835.250000 3321.270000 1841.750000 3325.270000 ;
      RECT 1825.250000 3321.270000 1831.750000 3325.270000 ;
      RECT 1815.250000 3321.270000 1821.750000 3325.270000 ;
      RECT 1805.250000 3321.270000 1811.750000 3325.270000 ;
      RECT 1795.250000 3321.270000 1801.750000 3325.270000 ;
      RECT 1785.250000 3321.270000 1791.750000 3325.270000 ;
      RECT 1775.250000 3321.270000 1781.750000 3325.270000 ;
      RECT 1765.250000 3321.270000 1771.750000 3325.270000 ;
      RECT 1755.250000 3321.270000 1761.750000 3325.270000 ;
      RECT 1745.250000 3321.270000 1751.750000 3325.270000 ;
      RECT 1735.250000 3321.270000 1741.750000 3325.270000 ;
      RECT 1725.250000 3321.270000 1731.750000 3325.270000 ;
      RECT 1715.250000 3321.270000 1721.750000 3325.270000 ;
      RECT 1705.250000 3321.270000 1711.750000 3325.270000 ;
      RECT 1695.250000 3321.270000 1701.750000 3325.270000 ;
      RECT 1685.250000 3321.270000 1691.750000 3325.270000 ;
      RECT 1675.250000 3321.270000 1681.750000 3325.270000 ;
      RECT 1665.250000 3321.270000 1671.750000 3325.270000 ;
      RECT 1655.250000 3321.270000 1661.750000 3325.270000 ;
      RECT 1645.250000 3321.270000 1651.750000 3325.270000 ;
      RECT 1635.250000 3321.270000 1641.750000 3325.270000 ;
      RECT 1625.250000 3321.270000 1631.750000 3325.270000 ;
      RECT 1615.250000 3321.270000 1621.750000 3325.270000 ;
      RECT 1605.250000 3321.270000 1611.750000 3325.270000 ;
      RECT 1595.250000 3321.270000 1601.750000 3325.270000 ;
      RECT 1585.250000 3321.270000 1591.750000 3325.270000 ;
      RECT 1575.250000 3321.270000 1581.750000 3325.270000 ;
      RECT 1565.250000 3321.270000 1571.750000 3325.270000 ;
      RECT 1555.250000 3321.270000 1561.750000 3325.270000 ;
      RECT 1545.250000 3321.270000 1551.750000 3325.270000 ;
      RECT 1535.250000 3321.270000 1541.750000 3325.270000 ;
      RECT 1525.250000 3321.270000 1531.750000 3325.270000 ;
      RECT 1515.250000 3321.270000 1521.750000 3325.270000 ;
      RECT 1505.250000 3321.270000 1511.750000 3325.270000 ;
      RECT 1495.250000 3321.270000 1501.750000 3325.270000 ;
      RECT 1485.250000 3321.270000 1491.750000 3325.270000 ;
      RECT 1475.250000 3321.270000 1481.750000 3325.270000 ;
      RECT 1465.250000 3321.270000 1471.750000 3325.270000 ;
      RECT 1455.250000 3321.270000 1461.750000 3325.270000 ;
      RECT 1445.250000 3321.270000 1451.750000 3325.270000 ;
      RECT 1435.250000 3321.270000 1441.750000 3325.270000 ;
      RECT 1425.250000 3321.270000 1431.750000 3325.270000 ;
      RECT 1415.250000 3321.270000 1421.750000 3325.270000 ;
      RECT 1405.250000 3321.270000 1411.750000 3325.270000 ;
      RECT 1395.250000 3321.270000 1401.750000 3325.270000 ;
      RECT 1385.250000 3321.270000 1391.750000 3325.270000 ;
      RECT 1375.250000 3321.270000 1381.750000 3325.270000 ;
      RECT 1365.250000 3321.270000 1371.750000 3325.270000 ;
      RECT 1355.250000 3321.270000 1361.750000 3325.270000 ;
      RECT 1345.250000 3321.270000 1351.750000 3325.270000 ;
      RECT 1335.250000 3321.270000 1341.750000 3325.270000 ;
      RECT 1325.250000 3321.270000 1331.750000 3325.270000 ;
      RECT 1315.250000 3321.270000 1321.750000 3325.270000 ;
      RECT 1305.250000 3321.270000 1311.750000 3325.270000 ;
      RECT 1295.250000 3321.270000 1301.750000 3325.270000 ;
      RECT 1285.250000 3321.270000 1291.750000 3325.270000 ;
      RECT 1275.250000 3321.270000 1281.750000 3325.270000 ;
      RECT 1265.250000 3321.270000 1271.750000 3325.270000 ;
      RECT 1255.250000 3321.270000 1261.750000 3325.270000 ;
      RECT 1245.250000 3321.270000 1251.750000 3325.270000 ;
      RECT 1235.250000 3321.270000 1241.750000 3325.270000 ;
      RECT 1225.250000 3321.270000 1231.750000 3325.270000 ;
      RECT 1215.250000 3321.270000 1221.750000 3325.270000 ;
      RECT 1205.250000 3321.270000 1211.750000 3325.270000 ;
      RECT 1195.250000 3321.270000 1201.750000 3325.270000 ;
      RECT 1185.250000 3321.270000 1191.750000 3325.270000 ;
      RECT 1175.250000 3321.270000 1181.750000 3325.270000 ;
      RECT 1165.250000 3321.270000 1171.750000 3325.270000 ;
      RECT 1155.250000 3321.270000 1161.750000 3325.270000 ;
      RECT 1145.250000 3321.270000 1151.750000 3325.270000 ;
      RECT 1135.250000 3321.270000 1141.750000 3325.270000 ;
      RECT 1125.250000 3321.270000 1131.750000 3325.270000 ;
      RECT 1115.250000 3321.270000 1121.750000 3325.270000 ;
      RECT 1105.250000 3321.270000 1111.750000 3325.270000 ;
      RECT 1095.250000 3321.270000 1101.750000 3325.270000 ;
      RECT 1085.250000 3321.270000 1091.750000 3325.270000 ;
      RECT 1075.250000 3321.270000 1081.750000 3325.270000 ;
      RECT 1065.250000 3321.270000 1071.750000 3325.270000 ;
      RECT 1055.250000 3321.270000 1061.750000 3325.270000 ;
      RECT 1045.250000 3321.270000 1051.750000 3325.270000 ;
      RECT 1035.250000 3321.270000 1041.750000 3325.270000 ;
      RECT 1025.250000 3321.270000 1031.750000 3325.270000 ;
      RECT 1015.250000 3321.270000 1021.750000 3325.270000 ;
      RECT 1005.250000 3321.270000 1011.750000 3325.270000 ;
      RECT 995.250000 3321.270000 1001.750000 3325.270000 ;
      RECT 985.250000 3321.270000 991.750000 3325.270000 ;
      RECT 975.250000 3321.270000 981.750000 3325.270000 ;
      RECT 965.250000 3321.270000 971.750000 3325.270000 ;
      RECT 955.250000 3321.270000 961.750000 3325.270000 ;
      RECT 945.250000 3321.270000 951.750000 3325.270000 ;
      RECT 935.250000 3321.270000 941.750000 3325.270000 ;
      RECT 925.250000 3321.270000 931.750000 3325.270000 ;
      RECT 915.250000 3321.270000 921.750000 3325.270000 ;
      RECT 905.250000 3321.270000 911.750000 3325.270000 ;
      RECT 895.250000 3321.270000 901.750000 3325.270000 ;
      RECT 885.250000 3321.270000 891.750000 3325.270000 ;
      RECT 875.250000 3321.270000 881.750000 3325.270000 ;
      RECT 865.250000 3321.270000 871.750000 3325.270000 ;
      RECT 855.250000 3321.270000 861.750000 3325.270000 ;
      RECT 845.250000 3321.270000 851.750000 3325.270000 ;
      RECT 835.250000 3321.270000 841.750000 3325.270000 ;
      RECT 825.250000 3321.270000 831.750000 3325.270000 ;
      RECT 815.250000 3321.270000 821.750000 3325.270000 ;
      RECT 805.250000 3321.270000 811.750000 3325.270000 ;
      RECT 795.250000 3321.270000 801.750000 3325.270000 ;
      RECT 785.250000 3321.270000 791.750000 3325.270000 ;
      RECT 775.250000 3321.270000 781.750000 3325.270000 ;
      RECT 765.250000 3321.270000 771.750000 3325.270000 ;
      RECT 755.250000 3321.270000 761.750000 3325.270000 ;
      RECT 745.250000 3321.270000 751.750000 3325.270000 ;
      RECT 735.250000 3321.270000 741.750000 3325.270000 ;
      RECT 725.250000 3321.270000 731.750000 3325.270000 ;
      RECT 715.250000 3321.270000 721.750000 3325.270000 ;
      RECT 705.250000 3321.270000 711.750000 3325.270000 ;
      RECT 695.250000 3321.270000 701.750000 3325.270000 ;
      RECT 685.250000 3321.270000 691.750000 3325.270000 ;
      RECT 675.250000 3321.270000 681.750000 3325.270000 ;
      RECT 665.250000 3321.270000 671.750000 3325.270000 ;
      RECT 655.250000 3321.270000 661.750000 3325.270000 ;
      RECT 645.250000 3321.270000 651.750000 3325.270000 ;
      RECT 635.250000 3321.270000 641.750000 3325.270000 ;
      RECT 625.250000 3321.270000 631.750000 3325.270000 ;
      RECT 615.250000 3321.270000 621.750000 3325.270000 ;
      RECT 605.250000 3321.270000 611.750000 3325.270000 ;
      RECT 595.250000 3321.270000 601.750000 3325.270000 ;
      RECT 585.250000 3321.270000 591.750000 3325.270000 ;
      RECT 575.250000 3321.270000 581.750000 3325.270000 ;
      RECT 565.250000 3321.270000 571.750000 3325.270000 ;
      RECT 555.250000 3321.270000 561.750000 3325.270000 ;
      RECT 545.250000 3321.270000 551.750000 3325.270000 ;
      RECT 535.250000 3321.270000 541.750000 3325.270000 ;
      RECT 525.250000 3321.270000 531.750000 3325.270000 ;
      RECT 515.250000 3321.270000 521.750000 3325.270000 ;
      RECT 505.250000 3321.270000 511.750000 3325.270000 ;
      RECT 495.250000 3321.270000 501.750000 3325.270000 ;
      RECT 485.250000 3321.270000 491.750000 3325.270000 ;
      RECT 475.250000 3321.270000 481.750000 3325.270000 ;
      RECT 465.250000 3321.270000 471.750000 3325.270000 ;
      RECT 455.250000 3321.270000 461.750000 3325.270000 ;
      RECT 445.250000 3321.270000 451.750000 3325.270000 ;
      RECT 435.250000 3321.270000 441.750000 3325.270000 ;
      RECT 425.250000 3321.270000 431.750000 3325.270000 ;
      RECT 415.250000 3321.270000 421.750000 3325.270000 ;
      RECT 405.250000 3321.270000 411.750000 3325.270000 ;
      RECT 395.250000 3321.270000 401.750000 3325.270000 ;
      RECT 385.250000 3321.270000 391.750000 3325.270000 ;
      RECT 375.250000 3321.270000 381.750000 3325.270000 ;
      RECT 365.250000 3321.270000 371.750000 3325.270000 ;
      RECT 355.250000 3321.270000 361.750000 3325.270000 ;
      RECT 345.250000 3321.270000 351.750000 3325.270000 ;
      RECT 335.250000 3321.270000 341.750000 3325.270000 ;
      RECT 325.250000 3321.270000 331.750000 3325.270000 ;
      RECT 315.250000 3321.270000 321.750000 3325.270000 ;
      RECT 305.250000 3321.270000 311.750000 3325.270000 ;
      RECT 295.250000 3321.270000 301.750000 3325.270000 ;
      RECT 285.250000 3321.270000 291.750000 3325.270000 ;
      RECT 275.250000 3321.270000 281.750000 3325.270000 ;
      RECT 265.250000 3321.270000 271.750000 3325.270000 ;
      RECT 255.250000 3321.270000 261.750000 3325.270000 ;
      RECT 245.250000 3321.270000 251.750000 3325.270000 ;
      RECT 235.250000 3321.270000 241.750000 3325.270000 ;
      RECT 225.250000 3321.270000 231.750000 3325.270000 ;
      RECT 215.250000 3321.270000 221.750000 3325.270000 ;
      RECT 205.250000 3321.270000 211.750000 3325.270000 ;
      RECT 195.250000 3321.270000 201.750000 3325.270000 ;
      RECT 185.250000 3321.270000 191.750000 3325.270000 ;
      RECT 175.250000 3321.270000 181.750000 3325.270000 ;
      RECT 165.250000 3321.270000 171.750000 3325.270000 ;
      RECT 155.250000 3321.270000 161.750000 3325.270000 ;
      RECT 145.250000 3321.270000 151.750000 3325.270000 ;
      RECT 135.250000 3321.270000 141.750000 3325.270000 ;
      RECT 125.250000 3321.270000 131.750000 3325.270000 ;
      RECT 115.250000 3321.270000 121.750000 3325.270000 ;
      RECT 105.250000 3321.270000 111.750000 3325.270000 ;
      RECT 95.250000 3321.270000 101.750000 3325.270000 ;
      RECT 85.250000 3321.270000 91.750000 3325.270000 ;
      RECT 75.250000 3321.270000 81.750000 3325.270000 ;
      RECT 65.250000 3321.270000 71.750000 3325.270000 ;
      RECT 55.250000 3321.270000 61.750000 3325.270000 ;
      RECT 45.250000 3321.270000 51.750000 3325.270000 ;
      RECT 35.250000 3321.270000 41.750000 3325.270000 ;
      RECT 25.250000 3321.270000 31.750000 3325.270000 ;
      RECT 16.250000 3321.270000 21.750000 3325.270000 ;
      RECT 45.250000 3170.170000 48.750000 3321.270000 ;
      RECT 45.250000 3169.750000 45.295000 3170.170000 ;
      RECT 45.250000 3091.510000 48.750000 3169.750000 ;
      RECT 45.250000 3091.090000 45.270000 3091.510000 ;
      RECT 45.250000 3040.210000 48.750000 3091.090000 ;
      RECT 45.250000 3039.790000 45.255000 3040.210000 ;
      RECT 45.250000 3023.110000 48.750000 3039.790000 ;
      RECT 45.250000 3022.690000 45.555000 3023.110000 ;
      RECT 45.250000 2961.550000 48.750000 3022.690000 ;
      RECT 45.250000 2961.130000 45.330000 2961.550000 ;
      RECT 45.250000 2893.150000 48.750000 2961.130000 ;
      RECT 45.250000 2892.730000 45.330000 2893.150000 ;
      RECT 45.250000 2831.590000 48.750000 2892.730000 ;
      RECT 45.250000 2831.170000 45.555000 2831.590000 ;
      RECT 45.250000 2814.490000 48.750000 2831.170000 ;
      RECT 45.250000 2814.070000 45.255000 2814.490000 ;
      RECT 45.250000 2763.190000 48.750000 2814.070000 ;
      RECT 45.250000 2762.770000 45.270000 2763.190000 ;
      RECT 1305.250000 2699.635000 1308.750000 3321.270000 ;
      RECT 1295.250000 2699.635000 1298.750000 3321.270000 ;
      RECT 1285.250000 2699.635000 1288.750000 3321.270000 ;
      RECT 1275.250000 2699.635000 1278.750000 3321.270000 ;
      RECT 1265.250000 2699.635000 1268.750000 3321.270000 ;
      RECT 1255.250000 2699.635000 1258.750000 3321.270000 ;
      RECT 1252.250000 2699.455000 1308.750000 2699.635000 ;
      RECT 45.250000 2684.530000 48.750000 2762.770000 ;
      RECT 45.250000 2684.110000 45.295000 2684.530000 ;
      RECT 1252.250000 2645.765000 1311.750000 2699.455000 ;
      RECT 1252.250000 2645.585000 1308.750000 2645.765000 ;
      RECT 45.250000 2554.570000 48.750000 2684.110000 ;
      RECT 45.250000 2554.150000 45.535000 2554.570000 ;
      RECT 45.250000 2424.610000 48.750000 2554.150000 ;
      RECT 45.250000 2424.190000 45.580000 2424.610000 ;
      RECT 45.250000 2380.150000 48.750000 2424.190000 ;
      RECT 45.250000 2379.730000 45.330000 2380.150000 ;
      RECT 45.250000 2301.490000 48.750000 2379.730000 ;
      RECT 45.250000 2301.070000 45.255000 2301.490000 ;
      RECT 45.250000 2250.190000 48.750000 2301.070000 ;
      RECT 45.250000 2249.770000 45.270000 2250.190000 ;
      RECT 45.250000 2233.090000 48.750000 2249.770000 ;
      RECT 45.250000 2232.670000 45.580000 2233.090000 ;
      RECT 45.250000 2171.530000 48.750000 2232.670000 ;
      RECT 45.250000 2171.110000 45.295000 2171.530000 ;
      RECT 45.250000 2103.130000 48.750000 2171.110000 ;
      RECT 45.250000 2102.710000 45.535000 2103.130000 ;
      RECT 45.250000 2041.570000 48.750000 2102.710000 ;
      RECT 45.250000 2041.150000 45.535000 2041.570000 ;
      RECT 45.250000 1973.170000 48.750000 2041.150000 ;
      RECT 45.250000 1972.750000 45.295000 1973.170000 ;
      RECT 45.250000 1911.610000 48.750000 1972.750000 ;
      RECT 45.250000 1911.190000 45.580000 1911.610000 ;
      RECT 45.250000 1894.510000 48.750000 1911.190000 ;
      RECT 45.250000 1894.090000 45.270000 1894.510000 ;
      RECT 45.250000 1843.210000 48.750000 1894.090000 ;
      RECT 45.250000 1842.790000 45.255000 1843.210000 ;
      RECT 45.250000 1764.550000 48.750000 1842.790000 ;
      RECT 45.250000 1764.130000 45.330000 1764.550000 ;
      RECT 45.250000 1720.090000 48.750000 1764.130000 ;
      RECT 45.250000 1719.670000 45.580000 1720.090000 ;
      RECT 45.250000 1590.130000 48.750000 1719.670000 ;
      RECT 45.250000 1589.710000 45.535000 1590.130000 ;
      RECT 45.250000 1460.170000 48.750000 1589.710000 ;
      RECT 45.250000 1459.750000 45.295000 1460.170000 ;
      RECT 45.250000 1381.510000 48.750000 1459.750000 ;
      RECT 45.250000 1381.090000 45.270000 1381.510000 ;
      RECT 45.250000 1330.210000 48.750000 1381.090000 ;
      RECT 45.250000 1329.790000 45.255000 1330.210000 ;
      RECT 45.250000 1313.110000 48.750000 1329.790000 ;
      RECT 45.250000 1312.690000 45.555000 1313.110000 ;
      RECT 45.250000 1251.550000 48.750000 1312.690000 ;
      RECT 45.250000 1251.130000 45.330000 1251.550000 ;
      RECT 45.250000 1183.150000 48.750000 1251.130000 ;
      RECT 45.250000 1182.730000 45.330000 1183.150000 ;
      RECT 45.250000 1121.590000 48.750000 1182.730000 ;
      RECT 45.250000 1121.170000 45.555000 1121.590000 ;
      RECT 45.250000 1104.490000 48.750000 1121.170000 ;
      RECT 45.250000 1104.070000 45.255000 1104.490000 ;
      RECT 45.250000 1053.190000 48.750000 1104.070000 ;
      RECT 45.250000 1052.770000 45.270000 1053.190000 ;
      RECT 45.250000 974.530000 48.750000 1052.770000 ;
      RECT 45.250000 974.110000 45.295000 974.530000 ;
      RECT 45.250000 800.110000 48.750000 974.110000 ;
      RECT 45.250000 799.690000 45.555000 800.110000 ;
      RECT 45.250000 714.610000 48.750000 799.690000 ;
      RECT 45.250000 714.190000 45.665000 714.610000 ;
      RECT 45.250000 670.150000 48.750000 714.190000 ;
      RECT 45.250000 669.730000 45.330000 670.150000 ;
      RECT 45.250000 591.490000 48.750000 669.730000 ;
      RECT 45.250000 591.070000 45.255000 591.490000 ;
      RECT 45.250000 540.190000 48.750000 591.070000 ;
      RECT 45.250000 539.770000 45.270000 540.190000 ;
      RECT 45.250000 523.090000 48.750000 539.770000 ;
      RECT 45.250000 522.670000 45.580000 523.090000 ;
      RECT 45.250000 461.530000 48.750000 522.670000 ;
      RECT 45.250000 461.110000 45.295000 461.530000 ;
      RECT 45.250000 393.130000 48.750000 461.110000 ;
      RECT 45.250000 392.710000 45.535000 393.130000 ;
      RECT 45.250000 331.570000 48.750000 392.710000 ;
      RECT 45.250000 331.150000 45.535000 331.570000 ;
      RECT 45.250000 263.170000 48.750000 331.150000 ;
      RECT 45.250000 262.750000 45.295000 263.170000 ;
      RECT 1945.250000 210.160000 1948.750000 3321.270000 ;
      RECT 1945.500000 209.740000 1948.750000 210.160000 ;
      RECT 45.250000 201.610000 48.750000 262.750000 ;
      RECT 45.250000 201.190000 45.580000 201.610000 ;
      RECT 45.250000 184.510000 48.750000 201.190000 ;
      RECT 45.250000 184.090000 45.270000 184.510000 ;
      RECT 1845.250000 177.775000 1848.750000 3321.270000 ;
      RECT 1835.250000 177.775000 1838.750000 3321.270000 ;
      RECT 1825.250000 177.775000 1828.750000 3321.270000 ;
      RECT 1815.250000 177.775000 1818.750000 3321.270000 ;
      RECT 1805.250000 177.775000 1808.750000 3321.270000 ;
      RECT 1795.250000 177.775000 1798.750000 3321.270000 ;
      RECT 1785.250000 177.775000 1788.750000 3321.270000 ;
      RECT 1775.250000 177.775000 1778.750000 3321.270000 ;
      RECT 45.250000 133.210000 48.750000 184.090000 ;
      RECT 45.250000 132.790000 45.255000 133.210000 ;
      RECT 1945.250000 131.500000 1948.750000 209.740000 ;
      RECT 1945.535000 131.080000 1948.750000 131.500000 ;
      RECT 1772.250000 106.625000 1848.750000 177.775000 ;
      RECT 3085.250000 15.890000 3088.750000 3321.270000 ;
      RECT 3075.250000 15.890000 3078.750000 3321.270000 ;
      RECT 3065.250000 15.890000 3068.750000 3321.270000 ;
      RECT 3055.250000 15.890000 3058.750000 3321.270000 ;
      RECT 3045.250000 15.890000 3048.750000 3321.270000 ;
      RECT 3035.250000 15.890000 3038.750000 3321.270000 ;
      RECT 3025.250000 15.890000 3028.750000 3321.270000 ;
      RECT 3015.250000 15.890000 3018.750000 3321.270000 ;
      RECT 3005.250000 15.890000 3008.750000 3321.270000 ;
      RECT 2995.250000 15.890000 2998.750000 3321.270000 ;
      RECT 2985.250000 15.890000 2988.750000 3321.270000 ;
      RECT 2975.250000 15.890000 2978.750000 3321.270000 ;
      RECT 2965.250000 15.890000 2968.750000 3321.270000 ;
      RECT 2955.250000 15.890000 2958.750000 3321.270000 ;
      RECT 2945.250000 15.890000 2948.750000 3321.270000 ;
      RECT 2935.250000 15.890000 2938.750000 3321.270000 ;
      RECT 2925.250000 15.890000 2928.750000 3321.270000 ;
      RECT 2915.250000 15.890000 2918.750000 3321.270000 ;
      RECT 2905.250000 15.890000 2908.750000 3321.270000 ;
      RECT 2895.250000 15.890000 2898.750000 3321.270000 ;
      RECT 2885.250000 15.890000 2888.750000 3321.270000 ;
      RECT 2875.250000 15.890000 2878.750000 3321.270000 ;
      RECT 2865.250000 15.890000 2868.750000 3321.270000 ;
      RECT 2855.250000 15.890000 2858.750000 3321.270000 ;
      RECT 2845.250000 15.890000 2848.750000 3321.270000 ;
      RECT 2835.250000 15.890000 2838.750000 3321.270000 ;
      RECT 2825.250000 15.890000 2828.750000 3321.270000 ;
      RECT 2815.250000 15.890000 2818.750000 3321.270000 ;
      RECT 2805.250000 15.890000 2808.750000 3321.270000 ;
      RECT 2795.250000 15.890000 2798.750000 3321.270000 ;
      RECT 2785.250000 15.890000 2788.750000 3321.270000 ;
      RECT 2775.250000 15.890000 2778.750000 3321.270000 ;
      RECT 2765.250000 15.890000 2768.750000 3321.270000 ;
      RECT 2755.250000 15.890000 2758.750000 3321.270000 ;
      RECT 2745.250000 15.890000 2748.750000 3321.270000 ;
      RECT 2735.250000 15.890000 2738.750000 3321.270000 ;
      RECT 2725.250000 15.890000 2728.750000 3321.270000 ;
      RECT 2715.250000 15.890000 2718.750000 3321.270000 ;
      RECT 2705.250000 15.890000 2708.750000 3321.270000 ;
      RECT 2695.250000 15.890000 2698.750000 3321.270000 ;
      RECT 2685.250000 15.890000 2688.750000 3321.270000 ;
      RECT 2675.250000 15.890000 2678.750000 3321.270000 ;
      RECT 2665.250000 15.890000 2668.750000 3321.270000 ;
      RECT 2655.250000 15.890000 2658.750000 3321.270000 ;
      RECT 2645.250000 15.890000 2648.750000 3321.270000 ;
      RECT 2635.250000 15.890000 2638.750000 3321.270000 ;
      RECT 2625.250000 15.890000 2628.750000 3321.270000 ;
      RECT 2615.250000 15.890000 2618.750000 3321.270000 ;
      RECT 2605.250000 15.890000 2608.750000 3321.270000 ;
      RECT 2595.250000 15.890000 2598.750000 3321.270000 ;
      RECT 2585.250000 15.890000 2588.750000 3321.270000 ;
      RECT 2575.250000 15.890000 2578.750000 3321.270000 ;
      RECT 2565.250000 15.890000 2568.750000 3321.270000 ;
      RECT 2555.250000 15.890000 2558.750000 3321.270000 ;
      RECT 2545.250000 15.890000 2548.750000 3321.270000 ;
      RECT 2535.250000 15.890000 2538.750000 3321.270000 ;
      RECT 2525.250000 15.890000 2528.750000 3321.270000 ;
      RECT 2515.250000 15.890000 2518.750000 3321.270000 ;
      RECT 2505.250000 15.890000 2508.750000 3321.270000 ;
      RECT 2495.250000 15.890000 2498.750000 3321.270000 ;
      RECT 2485.250000 15.890000 2488.750000 3321.270000 ;
      RECT 2475.250000 15.890000 2478.750000 3321.270000 ;
      RECT 2465.250000 15.890000 2468.750000 3321.270000 ;
      RECT 2455.250000 15.890000 2458.750000 3321.270000 ;
      RECT 2445.250000 15.890000 2448.750000 3321.270000 ;
      RECT 2435.250000 15.890000 2438.750000 3321.270000 ;
      RECT 2425.250000 15.890000 2428.750000 3321.270000 ;
      RECT 2415.250000 15.890000 2418.750000 3321.270000 ;
      RECT 2405.250000 15.890000 2408.750000 3321.270000 ;
      RECT 2395.250000 15.890000 2398.750000 3321.270000 ;
      RECT 2385.250000 15.890000 2388.750000 3321.270000 ;
      RECT 2375.250000 15.890000 2378.750000 3321.270000 ;
      RECT 2365.250000 15.890000 2368.750000 3321.270000 ;
      RECT 2355.250000 15.890000 2358.750000 3321.270000 ;
      RECT 2345.250000 15.890000 2348.750000 3321.270000 ;
      RECT 2335.250000 15.890000 2338.750000 3321.270000 ;
      RECT 2325.250000 15.890000 2328.750000 3321.270000 ;
      RECT 2315.250000 15.890000 2318.750000 3321.270000 ;
      RECT 2305.250000 15.890000 2308.750000 3321.270000 ;
      RECT 2295.250000 15.890000 2298.750000 3321.270000 ;
      RECT 2285.250000 15.890000 2288.750000 3321.270000 ;
      RECT 2275.250000 15.890000 2278.750000 3321.270000 ;
      RECT 2265.250000 15.890000 2268.750000 3321.270000 ;
      RECT 2255.250000 15.890000 2258.750000 3321.270000 ;
      RECT 2245.250000 15.890000 2248.750000 3321.270000 ;
      RECT 2235.250000 15.890000 2238.750000 3321.270000 ;
      RECT 2225.250000 15.890000 2228.750000 3321.270000 ;
      RECT 2215.250000 15.890000 2218.750000 3321.270000 ;
      RECT 2205.250000 15.890000 2208.750000 3321.270000 ;
      RECT 2195.250000 15.890000 2198.750000 3321.270000 ;
      RECT 2185.250000 15.890000 2188.750000 3321.270000 ;
      RECT 2175.250000 15.890000 2178.750000 3321.270000 ;
      RECT 2165.250000 15.890000 2168.750000 3321.270000 ;
      RECT 2155.250000 15.890000 2158.750000 3321.270000 ;
      RECT 2145.250000 15.890000 2148.750000 3321.270000 ;
      RECT 2135.250000 15.890000 2138.750000 3321.270000 ;
      RECT 2125.250000 15.890000 2128.750000 3321.270000 ;
      RECT 2115.250000 15.890000 2118.750000 3321.270000 ;
      RECT 2105.250000 15.890000 2108.750000 3321.270000 ;
      RECT 2095.250000 15.890000 2098.750000 3321.270000 ;
      RECT 2085.250000 15.890000 2088.750000 3321.270000 ;
      RECT 2075.250000 15.890000 2078.750000 3321.270000 ;
      RECT 2065.250000 15.890000 2068.750000 3321.270000 ;
      RECT 2055.250000 15.890000 2058.750000 3321.270000 ;
      RECT 2045.250000 15.890000 2048.750000 3321.270000 ;
      RECT 2035.250000 15.890000 2038.750000 3321.270000 ;
      RECT 2025.250000 15.890000 2028.750000 3321.270000 ;
      RECT 2015.250000 15.890000 2018.750000 3321.270000 ;
      RECT 2005.250000 15.890000 2008.750000 3321.270000 ;
      RECT 1995.250000 15.890000 1998.750000 3321.270000 ;
      RECT 1985.250000 15.890000 1988.750000 3321.270000 ;
      RECT 1975.250000 15.890000 1978.750000 3321.270000 ;
      RECT 1965.250000 15.890000 1968.750000 3321.270000 ;
      RECT 1955.250000 15.890000 1958.750000 3321.270000 ;
      RECT 1945.250000 15.890000 1948.750000 131.080000 ;
      RECT 1935.250000 15.890000 1938.750000 3321.270000 ;
      RECT 1925.250000 15.890000 1928.750000 3321.270000 ;
      RECT 1915.250000 15.890000 1918.750000 3321.270000 ;
      RECT 1905.250000 15.890000 1908.750000 3321.270000 ;
      RECT 1895.250000 15.890000 1898.750000 3321.270000 ;
      RECT 1885.250000 15.890000 1888.750000 3321.270000 ;
      RECT 1875.250000 15.890000 1878.750000 3321.270000 ;
      RECT 1865.250000 15.890000 1868.750000 3321.270000 ;
      RECT 1855.250000 15.890000 1858.750000 3321.270000 ;
      RECT 1845.250000 15.890000 1848.750000 106.625000 ;
      RECT 1835.250000 15.890000 1838.750000 106.625000 ;
      RECT 1825.250000 15.890000 1828.750000 106.625000 ;
      RECT 1815.250000 15.890000 1818.750000 106.625000 ;
      RECT 1805.250000 15.890000 1808.750000 106.625000 ;
      RECT 1795.250000 15.890000 1798.750000 106.625000 ;
      RECT 1785.250000 15.890000 1788.750000 106.625000 ;
      RECT 1775.250000 15.890000 1778.750000 106.625000 ;
      RECT 1765.250000 15.890000 1768.750000 3321.270000 ;
      RECT 1755.250000 15.890000 1758.750000 3321.270000 ;
      RECT 1745.250000 15.890000 1748.750000 3321.270000 ;
      RECT 1735.250000 15.890000 1738.750000 3321.270000 ;
      RECT 1725.250000 15.890000 1728.750000 3321.270000 ;
      RECT 1715.250000 15.890000 1718.750000 3321.270000 ;
      RECT 1705.250000 15.890000 1708.750000 3321.270000 ;
      RECT 1695.250000 15.890000 1698.750000 3321.270000 ;
      RECT 1685.250000 15.890000 1688.750000 3321.270000 ;
      RECT 1675.250000 15.890000 1678.750000 3321.270000 ;
      RECT 1665.250000 15.890000 1668.750000 3321.270000 ;
      RECT 1655.250000 15.890000 1658.750000 3321.270000 ;
      RECT 1645.250000 15.890000 1648.750000 3321.270000 ;
      RECT 1635.250000 15.890000 1638.750000 3321.270000 ;
      RECT 1625.250000 15.890000 1628.750000 3321.270000 ;
      RECT 1615.250000 15.890000 1618.750000 3321.270000 ;
      RECT 1605.250000 15.890000 1608.750000 3321.270000 ;
      RECT 1595.250000 15.890000 1598.750000 3321.270000 ;
      RECT 1585.250000 15.890000 1588.750000 3321.270000 ;
      RECT 1575.250000 15.890000 1578.750000 3321.270000 ;
      RECT 1565.250000 15.890000 1568.750000 3321.270000 ;
      RECT 1555.250000 15.890000 1558.750000 3321.270000 ;
      RECT 1545.250000 15.890000 1548.750000 3321.270000 ;
      RECT 1535.250000 15.890000 1538.750000 3321.270000 ;
      RECT 1525.250000 15.890000 1528.750000 3321.270000 ;
      RECT 1515.250000 15.890000 1518.750000 3321.270000 ;
      RECT 1505.250000 15.890000 1508.750000 3321.270000 ;
      RECT 1495.250000 15.890000 1498.750000 3321.270000 ;
      RECT 1485.250000 15.890000 1488.750000 3321.270000 ;
      RECT 1475.250000 15.890000 1478.750000 3321.270000 ;
      RECT 1465.250000 15.890000 1468.750000 3321.270000 ;
      RECT 1455.250000 15.890000 1458.750000 3321.270000 ;
      RECT 1445.250000 15.890000 1448.750000 3321.270000 ;
      RECT 1435.250000 15.890000 1438.750000 3321.270000 ;
      RECT 1425.250000 15.890000 1428.750000 3321.270000 ;
      RECT 1415.250000 15.890000 1418.750000 3321.270000 ;
      RECT 1405.250000 15.890000 1408.750000 3321.270000 ;
      RECT 1395.250000 15.890000 1398.750000 3321.270000 ;
      RECT 1385.250000 15.890000 1388.750000 3321.270000 ;
      RECT 1375.250000 15.890000 1378.750000 3321.270000 ;
      RECT 1365.250000 15.890000 1368.750000 3321.270000 ;
      RECT 1355.250000 15.890000 1358.750000 3321.270000 ;
      RECT 1345.250000 15.890000 1348.750000 3321.270000 ;
      RECT 1335.250000 15.890000 1338.750000 3321.270000 ;
      RECT 1325.250000 15.890000 1328.750000 3321.270000 ;
      RECT 1315.250000 15.890000 1318.750000 3321.270000 ;
      RECT 1305.250000 15.890000 1308.750000 2645.585000 ;
      RECT 1295.250000 15.890000 1298.750000 2645.585000 ;
      RECT 1285.250000 15.890000 1288.750000 2645.585000 ;
      RECT 1275.250000 15.890000 1278.750000 2645.585000 ;
      RECT 1265.250000 15.890000 1268.750000 2645.585000 ;
      RECT 1255.250000 15.890000 1258.750000 2645.585000 ;
      RECT 1245.250000 15.890000 1248.750000 3321.270000 ;
      RECT 1235.250000 15.890000 1238.750000 3321.270000 ;
      RECT 1225.250000 15.890000 1228.750000 3321.270000 ;
      RECT 1215.250000 15.890000 1218.750000 3321.270000 ;
      RECT 1205.250000 15.890000 1208.750000 3321.270000 ;
      RECT 1195.250000 15.890000 1198.750000 3321.270000 ;
      RECT 1185.250000 15.890000 1188.750000 3321.270000 ;
      RECT 1175.250000 15.890000 1178.750000 3321.270000 ;
      RECT 1165.250000 15.890000 1168.750000 3321.270000 ;
      RECT 1155.250000 15.890000 1158.750000 3321.270000 ;
      RECT 1145.250000 15.890000 1148.750000 3321.270000 ;
      RECT 1135.250000 15.890000 1138.750000 3321.270000 ;
      RECT 1125.250000 15.890000 1128.750000 3321.270000 ;
      RECT 1115.250000 15.890000 1118.750000 3321.270000 ;
      RECT 1105.250000 15.890000 1108.750000 3321.270000 ;
      RECT 1095.250000 15.890000 1098.750000 3321.270000 ;
      RECT 1085.250000 15.890000 1088.750000 3321.270000 ;
      RECT 1075.250000 15.890000 1078.750000 3321.270000 ;
      RECT 1065.250000 15.890000 1068.750000 3321.270000 ;
      RECT 1055.250000 15.890000 1058.750000 3321.270000 ;
      RECT 1045.250000 15.890000 1048.750000 3321.270000 ;
      RECT 1035.250000 15.890000 1038.750000 3321.270000 ;
      RECT 1025.250000 15.890000 1028.750000 3321.270000 ;
      RECT 1015.250000 15.890000 1018.750000 3321.270000 ;
      RECT 1005.250000 15.890000 1008.750000 3321.270000 ;
      RECT 995.250000 15.890000 998.750000 3321.270000 ;
      RECT 985.250000 15.890000 988.750000 3321.270000 ;
      RECT 975.250000 15.890000 978.750000 3321.270000 ;
      RECT 965.250000 15.890000 968.750000 3321.270000 ;
      RECT 955.250000 15.890000 958.750000 3321.270000 ;
      RECT 945.250000 15.890000 948.750000 3321.270000 ;
      RECT 935.250000 15.890000 938.750000 3321.270000 ;
      RECT 925.250000 15.890000 928.750000 3321.270000 ;
      RECT 915.250000 15.890000 918.750000 3321.270000 ;
      RECT 905.250000 15.890000 908.750000 3321.270000 ;
      RECT 895.250000 15.890000 898.750000 3321.270000 ;
      RECT 885.250000 15.890000 888.750000 3321.270000 ;
      RECT 875.250000 15.890000 878.750000 3321.270000 ;
      RECT 865.250000 15.890000 868.750000 3321.270000 ;
      RECT 855.250000 15.890000 858.750000 3321.270000 ;
      RECT 845.250000 15.890000 848.750000 3321.270000 ;
      RECT 835.250000 15.890000 838.750000 3321.270000 ;
      RECT 825.250000 15.890000 828.750000 3321.270000 ;
      RECT 815.250000 15.890000 818.750000 3321.270000 ;
      RECT 805.250000 15.890000 808.750000 3321.270000 ;
      RECT 795.250000 15.890000 798.750000 3321.270000 ;
      RECT 785.250000 15.890000 788.750000 3321.270000 ;
      RECT 775.250000 15.890000 778.750000 3321.270000 ;
      RECT 765.250000 15.890000 768.750000 3321.270000 ;
      RECT 755.250000 15.890000 758.750000 3321.270000 ;
      RECT 745.250000 15.890000 748.750000 3321.270000 ;
      RECT 735.250000 15.890000 738.750000 3321.270000 ;
      RECT 725.250000 15.890000 728.750000 3321.270000 ;
      RECT 715.250000 15.890000 718.750000 3321.270000 ;
      RECT 705.250000 15.890000 708.750000 3321.270000 ;
      RECT 695.250000 15.890000 698.750000 3321.270000 ;
      RECT 685.250000 15.890000 688.750000 3321.270000 ;
      RECT 675.250000 15.890000 678.750000 3321.270000 ;
      RECT 665.250000 15.890000 668.750000 3321.270000 ;
      RECT 655.250000 15.890000 658.750000 3321.270000 ;
      RECT 645.250000 15.890000 648.750000 3321.270000 ;
      RECT 635.250000 15.890000 638.750000 3321.270000 ;
      RECT 625.250000 15.890000 628.750000 3321.270000 ;
      RECT 615.250000 15.890000 618.750000 3321.270000 ;
      RECT 605.250000 15.890000 608.750000 3321.270000 ;
      RECT 595.250000 15.890000 598.750000 3321.270000 ;
      RECT 585.250000 15.890000 588.750000 3321.270000 ;
      RECT 575.250000 15.890000 578.750000 3321.270000 ;
      RECT 565.250000 15.890000 568.750000 3321.270000 ;
      RECT 555.250000 15.890000 558.750000 3321.270000 ;
      RECT 545.250000 15.890000 548.750000 3321.270000 ;
      RECT 535.250000 15.890000 538.750000 3321.270000 ;
      RECT 525.250000 15.890000 528.750000 3321.270000 ;
      RECT 515.250000 15.890000 518.750000 3321.270000 ;
      RECT 505.250000 15.890000 508.750000 3321.270000 ;
      RECT 495.250000 15.890000 498.750000 3321.270000 ;
      RECT 485.250000 15.890000 488.750000 3321.270000 ;
      RECT 475.250000 15.890000 478.750000 3321.270000 ;
      RECT 465.250000 15.890000 468.750000 3321.270000 ;
      RECT 455.250000 15.890000 458.750000 3321.270000 ;
      RECT 445.250000 15.890000 448.750000 3321.270000 ;
      RECT 435.250000 15.890000 438.750000 3321.270000 ;
      RECT 425.250000 15.890000 428.750000 3321.270000 ;
      RECT 415.250000 15.890000 418.750000 3321.270000 ;
      RECT 405.250000 15.890000 408.750000 3321.270000 ;
      RECT 395.250000 15.890000 398.750000 3321.270000 ;
      RECT 385.250000 15.890000 388.750000 3321.270000 ;
      RECT 375.250000 15.890000 378.750000 3321.270000 ;
      RECT 365.250000 15.890000 368.750000 3321.270000 ;
      RECT 355.250000 15.890000 358.750000 3321.270000 ;
      RECT 345.250000 15.890000 348.750000 3321.270000 ;
      RECT 335.250000 15.890000 338.750000 3321.270000 ;
      RECT 325.250000 15.890000 328.750000 3321.270000 ;
      RECT 315.250000 15.890000 318.750000 3321.270000 ;
      RECT 305.250000 15.890000 308.750000 3321.270000 ;
      RECT 295.250000 15.890000 298.750000 3321.270000 ;
      RECT 285.250000 15.890000 288.750000 3321.270000 ;
      RECT 275.250000 15.890000 278.750000 3321.270000 ;
      RECT 265.250000 15.890000 268.750000 3321.270000 ;
      RECT 255.250000 15.890000 258.750000 3321.270000 ;
      RECT 245.250000 15.890000 248.750000 3321.270000 ;
      RECT 235.250000 15.890000 238.750000 3321.270000 ;
      RECT 225.250000 15.890000 228.750000 3321.270000 ;
      RECT 215.250000 15.890000 218.750000 3321.270000 ;
      RECT 205.250000 15.890000 208.750000 3321.270000 ;
      RECT 195.250000 15.890000 198.750000 3321.270000 ;
      RECT 185.250000 15.890000 188.750000 3321.270000 ;
      RECT 175.250000 15.890000 178.750000 3321.270000 ;
      RECT 165.250000 15.890000 168.750000 3321.270000 ;
      RECT 155.250000 15.890000 158.750000 3321.270000 ;
      RECT 145.250000 15.890000 148.750000 3321.270000 ;
      RECT 135.250000 15.890000 138.750000 3321.270000 ;
      RECT 125.250000 15.890000 128.750000 3321.270000 ;
      RECT 115.250000 15.890000 118.750000 3321.270000 ;
      RECT 105.250000 15.890000 108.750000 3321.270000 ;
      RECT 95.250000 15.890000 98.750000 3321.270000 ;
      RECT 85.250000 15.890000 88.750000 3321.270000 ;
      RECT 75.250000 15.890000 78.750000 3321.270000 ;
      RECT 65.250000 15.890000 68.750000 3321.270000 ;
      RECT 55.250000 15.890000 58.750000 3321.270000 ;
      RECT 45.250000 15.890000 48.750000 132.790000 ;
      RECT 35.250000 15.890000 38.750000 3321.270000 ;
      RECT 25.250000 15.890000 28.750000 3321.270000 ;
      RECT 3100.250000 11.890000 3112.000000 3325.270000 ;
      RECT 3085.250000 11.890000 3095.750000 15.890000 ;
      RECT 3075.250000 11.890000 3081.750000 15.890000 ;
      RECT 3065.250000 11.890000 3071.750000 15.890000 ;
      RECT 3055.250000 11.890000 3061.750000 15.890000 ;
      RECT 3045.250000 11.890000 3051.750000 15.890000 ;
      RECT 3035.250000 11.890000 3041.750000 15.890000 ;
      RECT 3025.250000 11.890000 3031.750000 15.890000 ;
      RECT 3015.250000 11.890000 3021.750000 15.890000 ;
      RECT 3005.250000 11.890000 3011.750000 15.890000 ;
      RECT 2995.250000 11.890000 3001.750000 15.890000 ;
      RECT 2985.250000 11.890000 2991.750000 15.890000 ;
      RECT 2975.250000 11.890000 2981.750000 15.890000 ;
      RECT 2965.250000 11.890000 2971.750000 15.890000 ;
      RECT 2955.250000 11.890000 2961.750000 15.890000 ;
      RECT 2945.250000 11.890000 2951.750000 15.890000 ;
      RECT 2935.250000 11.890000 2941.750000 15.890000 ;
      RECT 2925.250000 11.890000 2931.750000 15.890000 ;
      RECT 2915.250000 11.890000 2921.750000 15.890000 ;
      RECT 2905.250000 11.890000 2911.750000 15.890000 ;
      RECT 2895.250000 11.890000 2901.750000 15.890000 ;
      RECT 2885.250000 11.890000 2891.750000 15.890000 ;
      RECT 2875.250000 11.890000 2881.750000 15.890000 ;
      RECT 2865.250000 11.890000 2871.750000 15.890000 ;
      RECT 2855.250000 11.890000 2861.750000 15.890000 ;
      RECT 2845.250000 11.890000 2851.750000 15.890000 ;
      RECT 2835.250000 11.890000 2841.750000 15.890000 ;
      RECT 2825.250000 11.890000 2831.750000 15.890000 ;
      RECT 2815.250000 11.890000 2821.750000 15.890000 ;
      RECT 2805.250000 11.890000 2811.750000 15.890000 ;
      RECT 2795.250000 11.890000 2801.750000 15.890000 ;
      RECT 2785.250000 11.890000 2791.750000 15.890000 ;
      RECT 2775.250000 11.890000 2781.750000 15.890000 ;
      RECT 2765.250000 11.890000 2771.750000 15.890000 ;
      RECT 2755.250000 11.890000 2761.750000 15.890000 ;
      RECT 2745.250000 11.890000 2751.750000 15.890000 ;
      RECT 2735.250000 11.890000 2741.750000 15.890000 ;
      RECT 2725.250000 11.890000 2731.750000 15.890000 ;
      RECT 2715.250000 11.890000 2721.750000 15.890000 ;
      RECT 2705.250000 11.890000 2711.750000 15.890000 ;
      RECT 2695.250000 11.890000 2701.750000 15.890000 ;
      RECT 2685.250000 11.890000 2691.750000 15.890000 ;
      RECT 2675.250000 11.890000 2681.750000 15.890000 ;
      RECT 2665.250000 11.890000 2671.750000 15.890000 ;
      RECT 2655.250000 11.890000 2661.750000 15.890000 ;
      RECT 2645.250000 11.890000 2651.750000 15.890000 ;
      RECT 2635.250000 11.890000 2641.750000 15.890000 ;
      RECT 2625.250000 11.890000 2631.750000 15.890000 ;
      RECT 2615.250000 11.890000 2621.750000 15.890000 ;
      RECT 2605.250000 11.890000 2611.750000 15.890000 ;
      RECT 2595.250000 11.890000 2601.750000 15.890000 ;
      RECT 2585.250000 11.890000 2591.750000 15.890000 ;
      RECT 2575.250000 11.890000 2581.750000 15.890000 ;
      RECT 2565.250000 11.890000 2571.750000 15.890000 ;
      RECT 2555.250000 11.890000 2561.750000 15.890000 ;
      RECT 2545.250000 11.890000 2551.750000 15.890000 ;
      RECT 2535.250000 11.890000 2541.750000 15.890000 ;
      RECT 2525.250000 11.890000 2531.750000 15.890000 ;
      RECT 2515.250000 11.890000 2521.750000 15.890000 ;
      RECT 2505.250000 11.890000 2511.750000 15.890000 ;
      RECT 2495.250000 11.890000 2501.750000 15.890000 ;
      RECT 2485.250000 11.890000 2491.750000 15.890000 ;
      RECT 2475.250000 11.890000 2481.750000 15.890000 ;
      RECT 2465.250000 11.890000 2471.750000 15.890000 ;
      RECT 2455.250000 11.890000 2461.750000 15.890000 ;
      RECT 2445.250000 11.890000 2451.750000 15.890000 ;
      RECT 2435.250000 11.890000 2441.750000 15.890000 ;
      RECT 2425.250000 11.890000 2431.750000 15.890000 ;
      RECT 2415.250000 11.890000 2421.750000 15.890000 ;
      RECT 2405.250000 11.890000 2411.750000 15.890000 ;
      RECT 2395.250000 11.890000 2401.750000 15.890000 ;
      RECT 2385.250000 11.890000 2391.750000 15.890000 ;
      RECT 2375.250000 11.890000 2381.750000 15.890000 ;
      RECT 2365.250000 11.890000 2371.750000 15.890000 ;
      RECT 2355.250000 11.890000 2361.750000 15.890000 ;
      RECT 2345.250000 11.890000 2351.750000 15.890000 ;
      RECT 2335.250000 11.890000 2341.750000 15.890000 ;
      RECT 2325.250000 11.890000 2331.750000 15.890000 ;
      RECT 2315.250000 11.890000 2321.750000 15.890000 ;
      RECT 2305.250000 11.890000 2311.750000 15.890000 ;
      RECT 2295.250000 11.890000 2301.750000 15.890000 ;
      RECT 2285.250000 11.890000 2291.750000 15.890000 ;
      RECT 2275.250000 11.890000 2281.750000 15.890000 ;
      RECT 2265.250000 11.890000 2271.750000 15.890000 ;
      RECT 2255.250000 11.890000 2261.750000 15.890000 ;
      RECT 2245.250000 11.890000 2251.750000 15.890000 ;
      RECT 2235.250000 11.890000 2241.750000 15.890000 ;
      RECT 2225.250000 11.890000 2231.750000 15.890000 ;
      RECT 2215.250000 11.890000 2221.750000 15.890000 ;
      RECT 2205.250000 11.890000 2211.750000 15.890000 ;
      RECT 2195.250000 11.890000 2201.750000 15.890000 ;
      RECT 2185.250000 11.890000 2191.750000 15.890000 ;
      RECT 2175.250000 11.890000 2181.750000 15.890000 ;
      RECT 2165.250000 11.890000 2171.750000 15.890000 ;
      RECT 2155.250000 11.890000 2161.750000 15.890000 ;
      RECT 2145.250000 11.890000 2151.750000 15.890000 ;
      RECT 2135.250000 11.890000 2141.750000 15.890000 ;
      RECT 2125.250000 11.890000 2131.750000 15.890000 ;
      RECT 2115.250000 11.890000 2121.750000 15.890000 ;
      RECT 2105.250000 11.890000 2111.750000 15.890000 ;
      RECT 2095.250000 11.890000 2101.750000 15.890000 ;
      RECT 2085.250000 11.890000 2091.750000 15.890000 ;
      RECT 2075.250000 11.890000 2081.750000 15.890000 ;
      RECT 2065.250000 11.890000 2071.750000 15.890000 ;
      RECT 2055.250000 11.890000 2061.750000 15.890000 ;
      RECT 2045.250000 11.890000 2051.750000 15.890000 ;
      RECT 2035.250000 11.890000 2041.750000 15.890000 ;
      RECT 2025.250000 11.890000 2031.750000 15.890000 ;
      RECT 2015.250000 11.890000 2021.750000 15.890000 ;
      RECT 2005.250000 11.890000 2011.750000 15.890000 ;
      RECT 1995.250000 11.890000 2001.750000 15.890000 ;
      RECT 1985.250000 11.890000 1991.750000 15.890000 ;
      RECT 1975.250000 11.890000 1981.750000 15.890000 ;
      RECT 1965.250000 11.890000 1971.750000 15.890000 ;
      RECT 1955.250000 11.890000 1961.750000 15.890000 ;
      RECT 1945.250000 11.890000 1951.750000 15.890000 ;
      RECT 1935.250000 11.890000 1941.750000 15.890000 ;
      RECT 1925.250000 11.890000 1931.750000 15.890000 ;
      RECT 1915.250000 11.890000 1921.750000 15.890000 ;
      RECT 1905.250000 11.890000 1911.750000 15.890000 ;
      RECT 1895.250000 11.890000 1901.750000 15.890000 ;
      RECT 1885.250000 11.890000 1891.750000 15.890000 ;
      RECT 1875.250000 11.890000 1881.750000 15.890000 ;
      RECT 1865.250000 11.890000 1871.750000 15.890000 ;
      RECT 1855.250000 11.890000 1861.750000 15.890000 ;
      RECT 1845.250000 11.890000 1851.750000 15.890000 ;
      RECT 1835.250000 11.890000 1841.750000 15.890000 ;
      RECT 1825.250000 11.890000 1831.750000 15.890000 ;
      RECT 1815.250000 11.890000 1821.750000 15.890000 ;
      RECT 1805.250000 11.890000 1811.750000 15.890000 ;
      RECT 1795.250000 11.890000 1801.750000 15.890000 ;
      RECT 1785.250000 11.890000 1791.750000 15.890000 ;
      RECT 1775.250000 11.890000 1781.750000 15.890000 ;
      RECT 1765.250000 11.890000 1771.750000 15.890000 ;
      RECT 1755.250000 11.890000 1761.750000 15.890000 ;
      RECT 1745.250000 11.890000 1751.750000 15.890000 ;
      RECT 1735.250000 11.890000 1741.750000 15.890000 ;
      RECT 1725.250000 11.890000 1731.750000 15.890000 ;
      RECT 1715.250000 11.890000 1721.750000 15.890000 ;
      RECT 1705.250000 11.890000 1711.750000 15.890000 ;
      RECT 1695.250000 11.890000 1701.750000 15.890000 ;
      RECT 1685.250000 11.890000 1691.750000 15.890000 ;
      RECT 1675.250000 11.890000 1681.750000 15.890000 ;
      RECT 1665.250000 11.890000 1671.750000 15.890000 ;
      RECT 1655.250000 11.890000 1661.750000 15.890000 ;
      RECT 1645.250000 11.890000 1651.750000 15.890000 ;
      RECT 1635.250000 11.890000 1641.750000 15.890000 ;
      RECT 1625.250000 11.890000 1631.750000 15.890000 ;
      RECT 1615.250000 11.890000 1621.750000 15.890000 ;
      RECT 1605.250000 11.890000 1611.750000 15.890000 ;
      RECT 1595.250000 11.890000 1601.750000 15.890000 ;
      RECT 1585.250000 11.890000 1591.750000 15.890000 ;
      RECT 1575.250000 11.890000 1581.750000 15.890000 ;
      RECT 1565.250000 11.890000 1571.750000 15.890000 ;
      RECT 1555.250000 11.890000 1561.750000 15.890000 ;
      RECT 1545.250000 11.890000 1551.750000 15.890000 ;
      RECT 1535.250000 11.890000 1541.750000 15.890000 ;
      RECT 1525.250000 11.890000 1531.750000 15.890000 ;
      RECT 1515.250000 11.890000 1521.750000 15.890000 ;
      RECT 1505.250000 11.890000 1511.750000 15.890000 ;
      RECT 1495.250000 11.890000 1501.750000 15.890000 ;
      RECT 1485.250000 11.890000 1491.750000 15.890000 ;
      RECT 1475.250000 11.890000 1481.750000 15.890000 ;
      RECT 1465.250000 11.890000 1471.750000 15.890000 ;
      RECT 1455.250000 11.890000 1461.750000 15.890000 ;
      RECT 1445.250000 11.890000 1451.750000 15.890000 ;
      RECT 1435.250000 11.890000 1441.750000 15.890000 ;
      RECT 1425.250000 11.890000 1431.750000 15.890000 ;
      RECT 1415.250000 11.890000 1421.750000 15.890000 ;
      RECT 1405.250000 11.890000 1411.750000 15.890000 ;
      RECT 1395.250000 11.890000 1401.750000 15.890000 ;
      RECT 1385.250000 11.890000 1391.750000 15.890000 ;
      RECT 1375.250000 11.890000 1381.750000 15.890000 ;
      RECT 1365.250000 11.890000 1371.750000 15.890000 ;
      RECT 1355.250000 11.890000 1361.750000 15.890000 ;
      RECT 1345.250000 11.890000 1351.750000 15.890000 ;
      RECT 1335.250000 11.890000 1341.750000 15.890000 ;
      RECT 1325.250000 11.890000 1331.750000 15.890000 ;
      RECT 1315.250000 11.890000 1321.750000 15.890000 ;
      RECT 1305.250000 11.890000 1311.750000 15.890000 ;
      RECT 1295.250000 11.890000 1301.750000 15.890000 ;
      RECT 1285.250000 11.890000 1291.750000 15.890000 ;
      RECT 1275.250000 11.890000 1281.750000 15.890000 ;
      RECT 1265.250000 11.890000 1271.750000 15.890000 ;
      RECT 1255.250000 11.890000 1261.750000 15.890000 ;
      RECT 1245.250000 11.890000 1251.750000 15.890000 ;
      RECT 1235.250000 11.890000 1241.750000 15.890000 ;
      RECT 1225.250000 11.890000 1231.750000 15.890000 ;
      RECT 1215.250000 11.890000 1221.750000 15.890000 ;
      RECT 1205.250000 11.890000 1211.750000 15.890000 ;
      RECT 1195.250000 11.890000 1201.750000 15.890000 ;
      RECT 1185.250000 11.890000 1191.750000 15.890000 ;
      RECT 1175.250000 11.890000 1181.750000 15.890000 ;
      RECT 1165.250000 11.890000 1171.750000 15.890000 ;
      RECT 1155.250000 11.890000 1161.750000 15.890000 ;
      RECT 1145.250000 11.890000 1151.750000 15.890000 ;
      RECT 1135.250000 11.890000 1141.750000 15.890000 ;
      RECT 1125.250000 11.890000 1131.750000 15.890000 ;
      RECT 1115.250000 11.890000 1121.750000 15.890000 ;
      RECT 1105.250000 11.890000 1111.750000 15.890000 ;
      RECT 1095.250000 11.890000 1101.750000 15.890000 ;
      RECT 1085.250000 11.890000 1091.750000 15.890000 ;
      RECT 1075.250000 11.890000 1081.750000 15.890000 ;
      RECT 1065.250000 11.890000 1071.750000 15.890000 ;
      RECT 1055.250000 11.890000 1061.750000 15.890000 ;
      RECT 1045.250000 11.890000 1051.750000 15.890000 ;
      RECT 1035.250000 11.890000 1041.750000 15.890000 ;
      RECT 1025.250000 11.890000 1031.750000 15.890000 ;
      RECT 1015.250000 11.890000 1021.750000 15.890000 ;
      RECT 1005.250000 11.890000 1011.750000 15.890000 ;
      RECT 995.250000 11.890000 1001.750000 15.890000 ;
      RECT 985.250000 11.890000 991.750000 15.890000 ;
      RECT 975.250000 11.890000 981.750000 15.890000 ;
      RECT 965.250000 11.890000 971.750000 15.890000 ;
      RECT 955.250000 11.890000 961.750000 15.890000 ;
      RECT 945.250000 11.890000 951.750000 15.890000 ;
      RECT 935.250000 11.890000 941.750000 15.890000 ;
      RECT 925.250000 11.890000 931.750000 15.890000 ;
      RECT 915.250000 11.890000 921.750000 15.890000 ;
      RECT 905.250000 11.890000 911.750000 15.890000 ;
      RECT 895.250000 11.890000 901.750000 15.890000 ;
      RECT 885.250000 11.890000 891.750000 15.890000 ;
      RECT 875.250000 11.890000 881.750000 15.890000 ;
      RECT 865.250000 11.890000 871.750000 15.890000 ;
      RECT 855.250000 11.890000 861.750000 15.890000 ;
      RECT 845.250000 11.890000 851.750000 15.890000 ;
      RECT 835.250000 11.890000 841.750000 15.890000 ;
      RECT 825.250000 11.890000 831.750000 15.890000 ;
      RECT 815.250000 11.890000 821.750000 15.890000 ;
      RECT 805.250000 11.890000 811.750000 15.890000 ;
      RECT 795.250000 11.890000 801.750000 15.890000 ;
      RECT 785.250000 11.890000 791.750000 15.890000 ;
      RECT 775.250000 11.890000 781.750000 15.890000 ;
      RECT 765.250000 11.890000 771.750000 15.890000 ;
      RECT 755.250000 11.890000 761.750000 15.890000 ;
      RECT 745.250000 11.890000 751.750000 15.890000 ;
      RECT 735.250000 11.890000 741.750000 15.890000 ;
      RECT 725.250000 11.890000 731.750000 15.890000 ;
      RECT 715.250000 11.890000 721.750000 15.890000 ;
      RECT 705.250000 11.890000 711.750000 15.890000 ;
      RECT 695.250000 11.890000 701.750000 15.890000 ;
      RECT 685.250000 11.890000 691.750000 15.890000 ;
      RECT 675.250000 11.890000 681.750000 15.890000 ;
      RECT 665.250000 11.890000 671.750000 15.890000 ;
      RECT 655.250000 11.890000 661.750000 15.890000 ;
      RECT 645.250000 11.890000 651.750000 15.890000 ;
      RECT 635.250000 11.890000 641.750000 15.890000 ;
      RECT 625.250000 11.890000 631.750000 15.890000 ;
      RECT 615.250000 11.890000 621.750000 15.890000 ;
      RECT 605.250000 11.890000 611.750000 15.890000 ;
      RECT 595.250000 11.890000 601.750000 15.890000 ;
      RECT 585.250000 11.890000 591.750000 15.890000 ;
      RECT 575.250000 11.890000 581.750000 15.890000 ;
      RECT 565.250000 11.890000 571.750000 15.890000 ;
      RECT 555.250000 11.890000 561.750000 15.890000 ;
      RECT 545.250000 11.890000 551.750000 15.890000 ;
      RECT 535.250000 11.890000 541.750000 15.890000 ;
      RECT 525.250000 11.890000 531.750000 15.890000 ;
      RECT 515.250000 11.890000 521.750000 15.890000 ;
      RECT 505.250000 11.890000 511.750000 15.890000 ;
      RECT 495.250000 11.890000 501.750000 15.890000 ;
      RECT 485.250000 11.890000 491.750000 15.890000 ;
      RECT 475.250000 11.890000 481.750000 15.890000 ;
      RECT 465.250000 11.890000 471.750000 15.890000 ;
      RECT 455.250000 11.890000 461.750000 15.890000 ;
      RECT 445.250000 11.890000 451.750000 15.890000 ;
      RECT 435.250000 11.890000 441.750000 15.890000 ;
      RECT 425.250000 11.890000 431.750000 15.890000 ;
      RECT 415.250000 11.890000 421.750000 15.890000 ;
      RECT 405.250000 11.890000 411.750000 15.890000 ;
      RECT 395.250000 11.890000 401.750000 15.890000 ;
      RECT 385.250000 11.890000 391.750000 15.890000 ;
      RECT 375.250000 11.890000 381.750000 15.890000 ;
      RECT 365.250000 11.890000 371.750000 15.890000 ;
      RECT 355.250000 11.890000 361.750000 15.890000 ;
      RECT 345.250000 11.890000 351.750000 15.890000 ;
      RECT 335.250000 11.890000 341.750000 15.890000 ;
      RECT 325.250000 11.890000 331.750000 15.890000 ;
      RECT 315.250000 11.890000 321.750000 15.890000 ;
      RECT 305.250000 11.890000 311.750000 15.890000 ;
      RECT 295.250000 11.890000 301.750000 15.890000 ;
      RECT 285.250000 11.890000 291.750000 15.890000 ;
      RECT 275.250000 11.890000 281.750000 15.890000 ;
      RECT 265.250000 11.890000 271.750000 15.890000 ;
      RECT 255.250000 11.890000 261.750000 15.890000 ;
      RECT 245.250000 11.890000 251.750000 15.890000 ;
      RECT 235.250000 11.890000 241.750000 15.890000 ;
      RECT 225.250000 11.890000 231.750000 15.890000 ;
      RECT 215.250000 11.890000 221.750000 15.890000 ;
      RECT 205.250000 11.890000 211.750000 15.890000 ;
      RECT 195.250000 11.890000 201.750000 15.890000 ;
      RECT 185.250000 11.890000 191.750000 15.890000 ;
      RECT 175.250000 11.890000 181.750000 15.890000 ;
      RECT 165.250000 11.890000 171.750000 15.890000 ;
      RECT 155.250000 11.890000 161.750000 15.890000 ;
      RECT 145.250000 11.890000 151.750000 15.890000 ;
      RECT 135.250000 11.890000 141.750000 15.890000 ;
      RECT 125.250000 11.890000 131.750000 15.890000 ;
      RECT 115.250000 11.890000 121.750000 15.890000 ;
      RECT 105.250000 11.890000 111.750000 15.890000 ;
      RECT 95.250000 11.890000 101.750000 15.890000 ;
      RECT 85.250000 11.890000 91.750000 15.890000 ;
      RECT 75.250000 11.890000 81.750000 15.890000 ;
      RECT 65.250000 11.890000 71.750000 15.890000 ;
      RECT 55.250000 11.890000 61.750000 15.890000 ;
      RECT 45.250000 11.890000 51.750000 15.890000 ;
      RECT 35.250000 11.890000 41.750000 15.890000 ;
      RECT 25.250000 11.890000 31.750000 15.890000 ;
      RECT 16.250000 11.890000 21.750000 15.890000 ;
      RECT 0.000000 11.890000 11.750000 3325.270000 ;
      RECT 0.000000 0.000000 3112.000000 11.890000 ;
  END
END scr1_pipe_top

END LIBRARY
